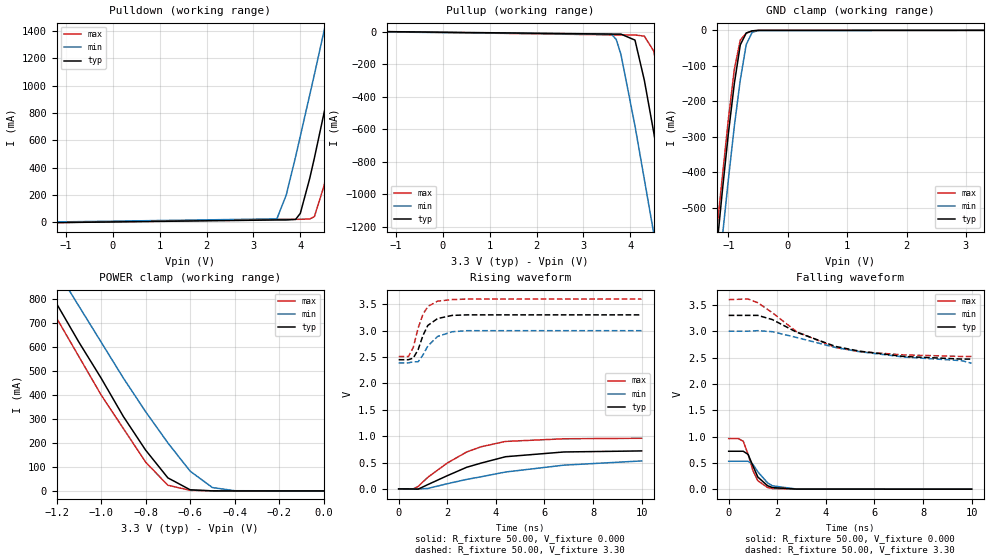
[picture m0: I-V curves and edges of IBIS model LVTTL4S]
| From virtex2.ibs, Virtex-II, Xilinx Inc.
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|   Model LVTTL4S
[Model]   LVTTL4S
Model_type   I/O
Polarity   Non-Inverting
Enable   Active-Low
Vinh = 2.0V
Vinl = 0.8V
Vmeas =   1.40V
Cref =  0pF
Rref =   1.00M
Vref =  0.000V
C_comp   10.00pF   10.00pF   10.00pF
[Temperature Range]   25.00   100.00   0.000
[Voltage Range]   3.30V   3.00V   3.60V
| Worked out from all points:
|   slope of the pulldown table from 0 to 0.495 V, typ, clamps not added: 64.8 ohm
|   slope of the pullup table from 0 to 0.495 V, typ, clamps not added: 95.5 ohm
|   GND clamp passes 1 mA (typ) near -0.57 V on its own axis
|   POWER clamp passes 1 mA (typ) near -0.52 V on its own axis
|   rising waveform, R_fixture 50.00, V_fixture 0.000: 20-80 % time 2.59ns typ, 4.21ns min, 2.05ns max; typ from 0 V to 0.72 V
|   rising waveform, R_fixture 50.00, V_fixture 3.30: 20-80 % time 511ps typ, 613ps min, 470ps max; typ from 2.45 V to 3.3 V
|   falling waveform, R_fixture 50.00, V_fixture 0.000: 20-80 % time 515ps typ, 584ps min, 453ps max; typ from 0.72 V to 0 V
|   falling waveform, R_fixture 50.00, V_fixture 3.30: 20-80 % time 3.06ns typ, 4.15ns min, 2.42ns max; typ from 3.3 V to 2.47 V
[Pulldown]
| voltage   I(typ)   I(min)   I(max)
-3.3V     -10.77mA   -7.22mA    -12.39mA
3.5V      17.22mA    24.99mA    22.01mA
3.7V      17.28mA    200mA      22.05mA
3.9V      21.2mA     480mA      22.09mA
4V        65.53mA    630mA      22.12mA
4.2V      320mA      930mA      24.26mA
4.3V      470mA      1.08A      41.45mA
4.5V      790mA      1.39A      260mA
4.9V      1.43A      2.01A      890mA
5.1V      1.76A      2.33A      1.21A
5.3V      2.09A      2.64A      1.54A
6.6V      4.26A      4.7A       3.7A
[Pullup]
| voltage   I(typ)   I(min)   I(max)
-3.3V     6.76mA     3.9mA      8.28mA
3.6V      -15.07mA   -16.2mA    -20.1mA
3.7V      -15.12mA   -48.43mA   -20.17mA
3.8V      -15.26mA   -140mA     -20.23mA
4.1V      -52.21mA   -580mA     -20.5mA
4.3V      -300mA     -910mA     -27.9mA
4.5V      -620mA     -1.24A     -120mA
4.7V      -960mA     -1.58A     -410mA
4.9V      -1.3A      -1.91A     -750mA
5.1V      -1.65A     -2.25A     -1.09A
5.3V      -2A        -2.6A      -1.43A
6.6V      -4.31A     -4.84A     -3.73A
[GND_clamp]
| voltage   I(typ)   I(min)   I(max)
-3.3V     -4.3A      -4.31A     -4.26A
-1.2V     -620mA     -740mA     -570mA
-1.1V     -450mA     -580mA     -410mA
-1V       -290mA     -420mA     -250mA
-900mV    -150mA     -270mA     -110mA
-800mV    -41.03mA   -140mA     -27.28mA
-700mV    -7.6mA     -40.21mA   -8.18mA
-600mV    -1.42mA    -5.61mA    -1.62mA
-500mV    -130uA     -670uA     -130uA
3.3V      67.85pA    43.48uA    45.6pA
[POWER_clamp]
| voltage   I(typ)   I(min)   I(max)
-3.3V     4.25A      4.22A      4.2A
-1.3V     940mA      1.07A      880mA
-1.2V     780mA      920mA      720mA
-1.1V     620mA      770mA      560mA
-1V       470mA      620mA      400mA
-900mV    310mA      470mA      260mA
-800mV    170mA      330mA      120mA
-700mV    54.34mA    200mA      23.62mA
-600mV    4.76mA     82.21mA    2.52mA
-500mV    280uA      14.02mA    260uA
-400mV    16.9uA     860uA      14.85uA
0V        67.85pA    2.04nA     61.89pA
[Ramp]
| variable   typ   min   max
dV/dt_r   0.43/2.60n   0.30/3.78n   0.58/2.00n
dV/dt_f   0.50/3.00n   0.34/3.61n   0.65/2.42n
R_load = 50.00
[Rising Waveform]
R_fixture = 50.00
V_fixture = 0.000
| time   V(typ)   V(min)   V(max)
0s        0V         0V         0V
600ps     -2.08mV    -200uV     -17.67uV
800ps     -5.41mV    -2.05mV    45.71mV
1.2ns     81.39mV    8.06mV     220mV
2ns       250mV      98.09mV    490mV
2.8ns     410mV      180mV      700mV
3.4ns     490mV      230mV      800mV
4.4ns     610mV      320mV      900mV
6.8ns     700mV      450mV      950mV
10ns      720mV      530mV      960mV
[Rising Waveform]
R_fixture = 50.00
V_fixture = 3.30
V_fixture_min = 3.00
V_fixture_max = 3.60
| time   V(typ)   V(min)   V(max)
0s        2.45V      2.39V      2.51V
400ps     2.45V      2.39V      2.51V
600ps     2.48V      2.41V      2.68V
800ps     2.64V      2.41V      3.05V
1ns       2.91V      2.54V      3.31V
1.2ns     3.1V       2.71V      3.46V
1.6ns     3.23V      2.89V      3.56V
2.2ns     3.29V      2.98V      3.59V
2.8ns     3.3V       3V         3.6V
10ns      3.3V       3V         3.6V
[Falling Waveform]
R_fixture = 50.00
V_fixture = 0.000
| time   V(typ)   V(min)   V(max)
0s        720mV      530mV      960mV
400ps     720mV      530mV      960mV
600ps     720mV      530mV      910mV
800ps     660mV      530mV      660mV
1ns       440mV      470mV      350mV
1.2ns     230mV      330mV      160mV
1.6ns     65.75mV    120mV      32.74mV
1.8ns     29.91mV    63.65mV    11.98mV
2.8ns     950uV      2.12mV     700uV
10ns      26.28uV    62.72uV    11.53uV
[Falling Waveform]
R_fixture = 50.00
V_fixture = 3.30
V_fixture_min = 3.00
V_fixture_max = 3.60
| time   V(typ)   V(min)   V(max)
0s        3.3V       3V         3.6V
800ps     3.3V       3V         3.61V
1.2ns     3.3V       3.01V      3.54V
1.8ns     3.22V      2.99V      3.35V
2.8ns     2.98V      2.88V      2.99V
4.4ns     2.71V      2.69V      2.69V
5.4ns     2.62V      2.61V      2.61V
7.2ns     2.52V      2.51V      2.55V
9.6ns     2.47V      2.44V      2.52V
10ns      2.47V      2.39V      2.52V
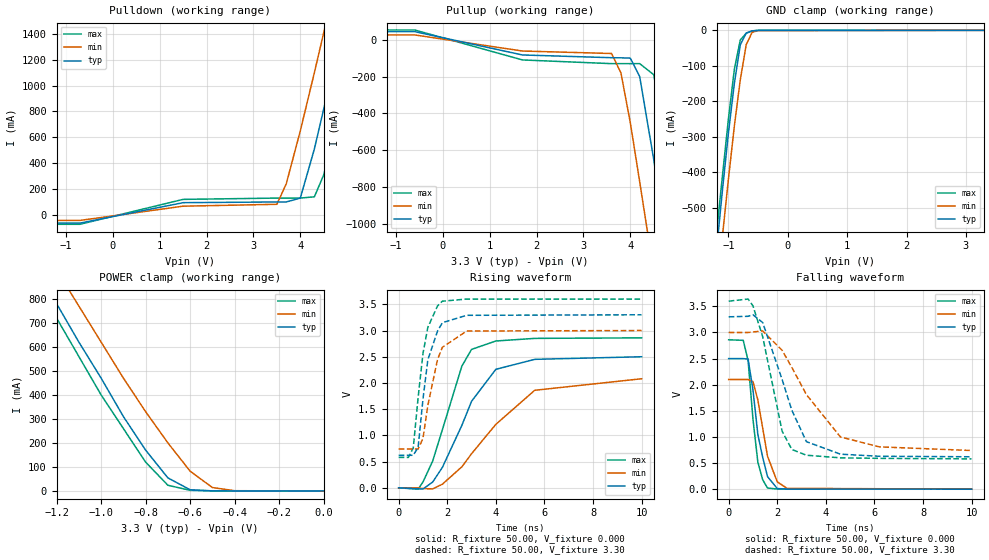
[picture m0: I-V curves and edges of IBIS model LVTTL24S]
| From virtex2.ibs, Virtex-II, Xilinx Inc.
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|   Model LVTTL24S
[Model]   LVTTL24S
Model_type   I/O
Polarity   Non-Inverting
Enable   Active-Low
Vinh = 2.0V
Vinl = 0.8V
Vmeas =   1.40V
Cref =  0pF
Rref =   1.00M
Vref =  0.000V
C_comp   10.00pF   10.00pF   10.00pF
[Temperature Range]   25.00   100.00   0.000
[Voltage Range]   3.30V   3.00V   3.60V
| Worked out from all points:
|   slope of the pulldown table from 0 to 0.495 V, typ, clamps not added: 11.1 ohm
|   slope of the pullup table from 0 to 0.495 V, typ, clamps not added: 15 ohm
|   GND clamp passes 1 mA (typ) near -0.57 V on its own axis
|   POWER clamp passes 1 mA (typ) near -0.52 V on its own axis
|   rising waveform, R_fixture 50.00, V_fixture 0.000: 20-80 % time 1.55ns typ, 2.36ns min, 1.13ns max; typ from 0 V to 2.5 V
|   rising waveform, R_fixture 50.00, V_fixture 3.30: 20-80 % time 535ps typ, 605ps min, 486ps max; typ from 0.62 V to 3.3 V
|   falling waveform, R_fixture 50.00, V_fixture 0.000: 20-80 % time 493ps typ, 524ps min, 357ps max; typ from 2.5 V to 0 V
|   falling waveform, R_fixture 50.00, V_fixture 3.30: 20-80 % time 1.08ns typ, 1.77ns min, 811ps max; typ from 3.3 V to 0.62 V
[Pulldown]
| voltage   I(typ)   I(min)   I(max)
-3.3V     -63.55mA   -42.85mA   -72.72mA
-700mV    -63.55mA   -42.85mA   -72.64mA
1.5V      94.54mA    67.4mA     120mA
3.5V      100mA      82mA       130mA
3.7V      100mA      240mA      130mA
4V        130mA      650mA      130mA
4.3V      510mA      1.1A       140mA
4.5V      820mA      1.41A      310mA
4.9V      1.47A      2.04A      930mA
5.1V      1.79A      2.35A      1.25A
5.3V      2.12A      2.67A      1.58A
6.6V      4.29A      4.73A      3.74A
[Pullup]
| voltage   I(typ)   I(min)   I(max)
-3.3V     43.55mA    25.59mA    52.52mA
-600mV    43.55mA    25.59mA    52.52mA
1.7V      -83mA      -61.63mA   -110mA
3.6V      -97.83mA   -75.1mA    -130mA
3.8V      -98.45mA   -180mA     -130mA
4V        -100mA     -450mA     -130mA
4.2V      -200mA     -770mA     -130mA
4.5V      -650mA     -1.26A     -190mA
4.9V      -1.33A     -1.93A     -780mA
5.1V      -1.68A     -2.27A     -1.12A
5.3V      -2.03A     -2.62A     -1.47A
6.6V      -4.33A     -4.85A     -3.76A
[GND_clamp]
| voltage   I(typ)   I(min)   I(max)
-3.3V     -4.3A      -4.31A     -4.26A
-1.2V     -620mA     -740mA     -570mA
-1.1V     -450mA     -580mA     -410mA
-1V       -290mA     -420mA     -250mA
-900mV    -150mA     -270mA     -110mA
-800mV    -41.03mA   -140mA     -27.28mA
-700mV    -7.6mA     -40.21mA   -8.18mA
-600mV    -1.42mA    -5.61mA    -1.62mA
-500mV    -130uA     -670uA     -130uA
3.3V      67.85pA    43.48uA    45.6pA
[POWER_clamp]
| voltage   I(typ)   I(min)   I(max)
-3.3V     4.25A      4.22A      4.2A
-1.3V     940mA      1.07A      880mA
-1.2V     780mA      920mA      720mA
-1.1V     620mA      770mA      560mA
-1V       470mA      620mA      400mA
-900mV    310mA      470mA      260mA
-800mV    170mA      330mA      120mA
-700mV    54.34mA    200mA      23.62mA
-600mV    4.76mA     82.21mA    2.52mA
-500mV    280uA      14.02mA    260uA
-400mV    16.9uA     860uA      14.85uA
0V        67.85pA    2.04nA     61.89pA
[Ramp]
| variable   typ   min   max
dV/dt_r   1.50/1.55n   1.25/2.35n   1.72/1.12n
dV/dt_f   1.61/1.13n   1.35/1.79n   1.81/0.80n
R_load = 50.00
[Rising Waveform]
R_fixture = 50.00
V_fixture = 0.000
| time   V(typ)   V(min)   V(max)
0s        0V         0V         0V
800ps     -19.43mV   -1.42mV    -26.19mV
1ns       -23.4mV    -14.97mV   110mV
1.4ns     110mV      -21.32mV   510mV
1.8ns     390mV      68.46mV    1.11V
2.6ns     1.19V      400mV      2.32V
3ns       1.65V      650mV      2.64V
4ns       2.26V      1.21V      2.8V
5.6ns     2.45V      1.86V      2.85V
10ns      2.5V       2.08V      2.86V
[Rising Waveform]
R_fixture = 50.00
V_fixture = 3.30
V_fixture_min = 3.00
V_fixture_max = 3.60
| time   V(typ)   V(min)   V(max)
0s        620mV      740mV      580mV
400ps     620mV      740mV      580mV
600ps     620mV      740mV      760mV
800ps     770mV      740mV      1.72V
1ns       1.69V      940mV      2.56V
1.2ns     2.44V      1.57V      3.06V
1.6ns     2.99V      2.45V      3.47V
1.8ns     3.15V      2.68V      3.56V
2.8ns     3.29V      2.99V      3.6V
10ns      3.3V       3V         3.6V
[Falling Waveform]
R_fixture = 50.00
V_fixture = 0.000
| time   V(typ)   V(min)   V(max)
0s        2.5V       2.1V       2.86V
600ps     2.5V       2.1V       2.85V
800ps     2.49V      2.1V       2.46V
1ns       1.9V       2.06V      1.34V
1.2ns     1.05V      1.71V      520mV
1.4ns     610mV      1.17V      180mV
1.6ns     240mV      630mV      21.62mV
2ns       11.37mV    140mV      2.42mV
2.4ns     2.38mV     16.07mV    1.74mV
10ns      13.6uV     51.08uV    3.58uV
[Falling Waveform]
R_fixture = 50.00
V_fixture = 3.30
V_fixture_min = 3.00
V_fixture_max = 3.60
| time   V(typ)   V(min)   V(max)
0s        3.3V       3V         3.6V
800ps     3.31V      3V         3.64V
1ns       3.34V      3.01V      3.51V
1.4ns     3.19V      3.03V      2.92V
2.2ns     2.1V       2.66V      1.11V
2.6ns     1.51V      2.33V      760mV
3.2ns     910mV      1.81V      650mV
4.6ns     670mV      1V         600mV
6.2ns     630mV      810mV      590mV
10ns      620mV      740mV      580mV
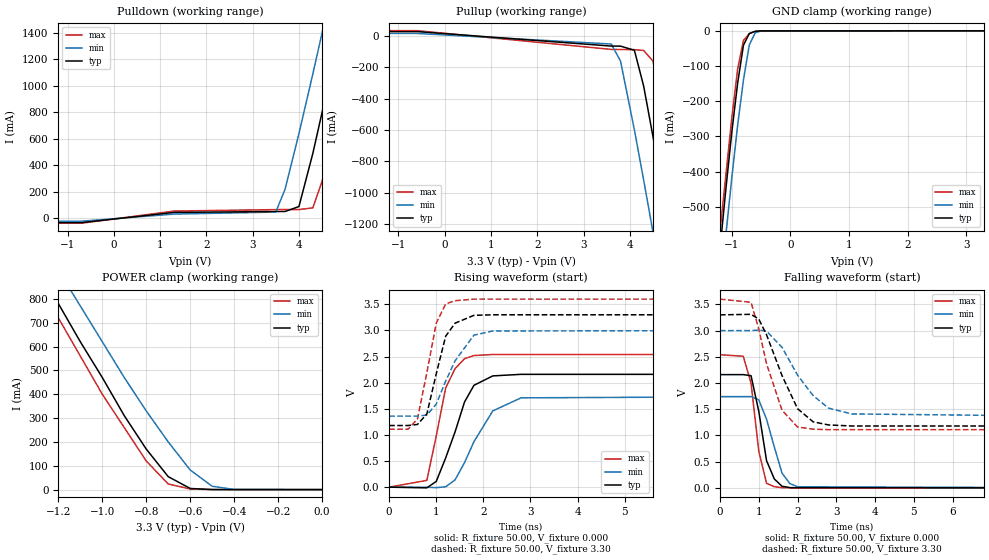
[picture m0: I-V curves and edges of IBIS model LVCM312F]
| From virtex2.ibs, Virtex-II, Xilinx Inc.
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|   Model LVCM312F
[Model]   LVCM312F
Model_type   I/O
Polarity   Non-Inverting
Enable   Active-Low
Vinh = 2.0V
Vinl = 0.8V
Vmeas =   1.65V
Cref =  0pF
Rref =   1.00M
Vref =  0.000V
C_comp   10.00pF   10.00pF   10.00pF
[Temperature Range]   25.00   100.00   0.000
[Voltage Range]   3.30V   3.00V   3.60V
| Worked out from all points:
|   slope of the pulldown table from 0 to 0.495 V, typ, clamps not added: 21.8 ohm
|   slope of the pullup table from 0 to 0.495 V, typ, clamps not added: 22.7 ohm
|   GND clamp passes 1 mA (typ) near -0.57 V on its own axis
|   POWER clamp passes 1 mA (typ) near -0.52 V on its own axis
|   rising waveform, R_fixture 50.00, V_fixture 0.000: 20-80 % time 518ps typ, 620ps min, 382ps max; typ from 0 V to 2.16 V
|   rising waveform, R_fixture 50.00, V_fixture 3.30: 20-80 % time 343ps typ, 504ps min, 323ps max; typ from 1.18 V to 3.3 V
|   falling waveform, R_fixture 50.00, V_fixture 0.000: 20-80 % time 329ps typ, 417ps min, 275ps max; typ from 2.16 V to 0 V
|   falling waveform, R_fixture 50.00, V_fixture 3.30: 20-80 % time 702ps typ, 905ps min, 570ps max; typ from 3.3 V to 1.18 V
[Pulldown]
| voltage   I(typ)   I(min)   I(max)
-3.3V     -32.1mA    -21.58mA   -36.83mA
-700mV    -32.1mA    -21.58mA   -36.83mA
1.3V      44.67mA    32.07mA    55.03mA
3.5V      51.66mA    47.4mA     66.01mA
3.7V      51.79mA    220mA      66.14mA
4V        89.06mA    640mA      66.32mA
4.3V      490mA      1.09A      79.21mA
4.5V      800mA      1.4A       280mA
4.9V      1.45A      2.02A      900mA
5.1V      1.78A      2.34A      1.23A
5.3V      2.11A      2.65A      1.56A
6.6V      4.27A      4.71A      3.72A
[Pullup]
| voltage   I(typ)   I(min)   I(max)
-3.3V     28.6mA     16.68mA    34.69mA
-600mV    28.6mA     16.68mA    34.69mA
3.6V      -63.99mA   -50.9mA    -85.36mA
3.8V      -64.43mA   -160mA     -85.91mA
4.1V      -90.87mA   -600mA     -86.68mA
4.3V      -320mA     -920mA     -92.25mA
4.5V      -640mA     -1.25A     -160mA
4.7V      -980mA     -1.59A     -440mA
4.9V      -1.32A     -1.93A     -770mA
5.1V      -1.67A     -2.27A     -1.11A
5.3V      -2.02A     -2.61A     -1.46A
6.6V      -4.32A     -4.85A     -3.75A
[GND_clamp]
| voltage   I(typ)   I(min)   I(max)
-3.3V     -4.3A      -4.31A     -4.26A
-1.2V     -620mA     -740mA     -570mA
-1.1V     -450mA     -580mA     -410mA
-1V       -290mA     -420mA     -250mA
-900mV    -150mA     -270mA     -110mA
-800mV    -41.03mA   -140mA     -27.28mA
-700mV    -7.6mA     -40.21mA   -8.18mA
-600mV    -1.42mA    -5.61mA    -1.62mA
-500mV    -130uA     -670uA     -130uA
3.3V      67.85pA    43.48uA    45.6pA
[POWER_clamp]
| voltage   I(typ)   I(min)   I(max)
-3.3V     4.25A      4.22A      4.2A
-1.3V     940mA      1.07A      880mA
-1.2V     780mA      920mA      720mA
-1.1V     620mA      770mA      560mA
-1V       470mA      620mA      400mA
-900mV    310mA      470mA      260mA
-800mV    170mA      330mA      120mA
-700mV    54.34mA    200mA      23.62mA
-600mV    4.76mA     82.21mA    2.52mA
-500mV    280uA      14.02mA    260uA
-400mV    16.9uA     860uA      14.85uA
0V        67.85pA    2.04nA     61.89pA
[Ramp]
| variable   typ   min   max
dV/dt_r   1.29/0.44n   1.04/0.60n   1.52/0.34n
dV/dt_f   1.27/0.65n   0.98/0.89n   1.50/0.50n
R_load = 50.00
[Rising Waveform]
R_fixture = 50.00
V_fixture = 0.000
| time   V(typ)   V(min)   V(max)
0s        0V         0V         0V
800ps     -13.48mV   -1.37mV    130mV
1ns       110mV      -9.52mV    980mV
1.2ns     560mV      6.51mV     1.9V
1.4ns     1.06V      140mV      2.27V
1.6ns     1.63V      470mV      2.46V
1.8ns     1.95V      870mV      2.52V
2.2ns     2.13V      1.46V      2.54V
2.8ns     2.16V      1.71V      2.54V
10ns      2.16V      1.74V      2.54V
[Rising Waveform]
R_fixture = 50.00
V_fixture = 3.30
V_fixture_min = 3.00
V_fixture_max = 3.60
| time   V(typ)   V(min)   V(max)
0s        1.18V      1.36V      1.11V
400ps     1.18V      1.36V      1.11V
600ps     1.2V       1.36V      1.3V
800ps     1.4V       1.38V      2.19V
1ns       2.17V      1.59V      3.14V
1.2ns     2.89V      2.03V      3.51V
1.4ns     3.14V      2.42V      3.57V
1.8ns     3.29V      2.91V      3.6V
2.2ns     3.3V       2.99V      3.6V
10ns      3.3V       3V         3.6V
[Falling Waveform]
R_fixture = 50.00
V_fixture = 0.000
| time   V(typ)   V(min)   V(max)
0s        2.16V      1.74V      2.54V
600ps     2.16V      1.74V      2.51V
800ps     2.14V      1.74V      2V
1ns       1.46V      1.68V      700mV
1.2ns     520mV      1.31V      87.3mV
1.4ns     170mV      780mV      22.72mV
1.6ns     30.16mV    280mV      3.53mV
1.8ns     5.55mV     81.67mV    1.05mV
2ns       1.52mV     21.29mV    590uV
10ns      -2.88uV    2.46uV     3.51uV
[Falling Waveform]
R_fixture = 50.00
V_fixture = 3.30
V_fixture_min = 3.00
V_fixture_max = 3.60
| time   V(typ)   V(min)   V(max)
0s        3.3V       3V         3.6V
800ps     3.31V      3V         3.54V
1ns       3.22V      3.01V      3.03V
1.2ns     2.92V      2.99V      2.37V
1.6ns     2.14V      2.68V      1.48V
2ns       1.51V      2.15V      1.16V
2.4ns     1.26V      1.76V      1.12V
2.8ns     1.2V       1.52V      1.11V
3.4ns     1.18V      1.41V      1.11V
10ns      1.18V      1.36V      1.11V
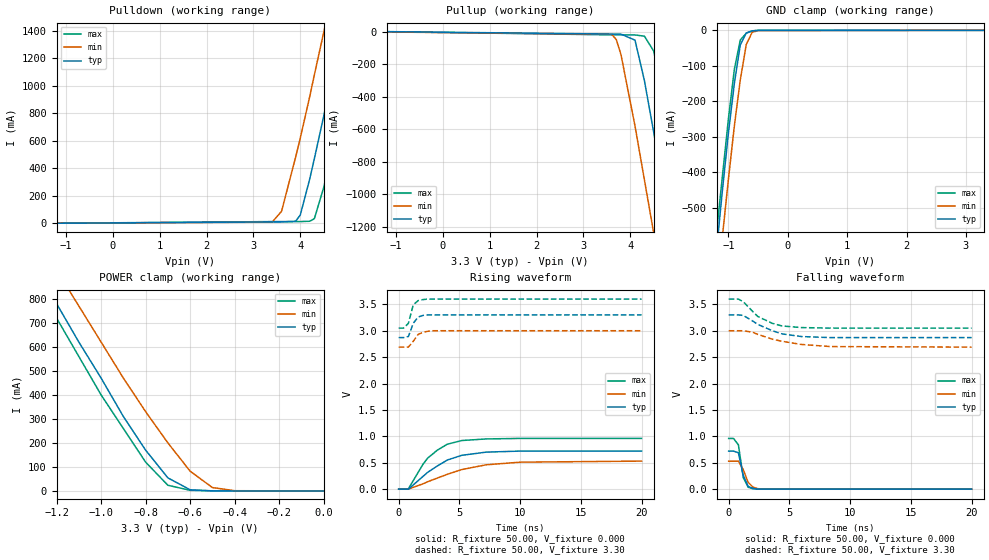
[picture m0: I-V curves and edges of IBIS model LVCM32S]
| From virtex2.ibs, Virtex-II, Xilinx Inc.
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|   Model LVCM32S
[Model]   LVCM32S
Model_type   I/O
Polarity   Non-Inverting
Enable   Active-Low
Vinh = 2.0V
Vinl = 0.8V
Vmeas =   1.65V
Cref =  0pF
Rref =   1.00M
Vref =  0.000V
C_comp   10.00pF   10.00pF   10.00pF
[Temperature Range]   25.00   100.00   0.000
[Voltage Range]   3.30V   3.00V   3.60V
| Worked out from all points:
|   slope of the pulldown table from 0 to 0.495 V, typ, clamps not added: 127 ohm
|   slope of the pullup table from 0 to 0.495 V, typ, clamps not added: 95.5 ohm
|   GND clamp passes 1 mA (typ) near -0.57 V on its own axis
|   POWER clamp passes 1 mA (typ) near -0.52 V on its own axis
|   rising waveform, R_fixture 50.00, V_fixture 0.000: 20-80 % time 2.73ns typ, 4.1ns min, 2.15ns max; typ from 0 V to 0.72 V
|   rising waveform, R_fixture 50.00, V_fixture 3.30: 20-80 % time 541ps typ, 655ps min, 377ps max; typ from 2.87 V to 3.3 V
|   falling waveform, R_fixture 50.00, V_fixture 0.000: 20-80 % time 518ps typ, 640ps min, 415ps max; typ from 0.72 V to 0 V
|   falling waveform, R_fixture 50.00, V_fixture 3.30: 20-80 % time 2.41ns typ, 3.2ns min, 1.96ns max; typ from 3.3 V to 2.87 V
[Pulldown]
| voltage   I(typ)   I(min)   I(max)
-3.3V     -5.48mA    -3.66mA    -6.34mA
3.4V      8.68mA     7.12mA     11.12mA
3.6V      8.7mA      86.09mA    11.15mA
3.9V      13.03mA    480mA      11.18mA
4V        59.94mA    620mA      11.2mA
4.2V      320mA      920mA      13.51mA
4.3V      470mA      1.08A      32.54mA
4.5V      780mA      1.39A      260mA
4.9V      1.43A      2.01A      880mA
5.1V      1.76A      2.32A      1.21A
5.3V      2.09A      2.64A      1.54A
6.6V      4.26A      4.7A       3.7A
[Pullup]
| voltage   I(typ)   I(min)   I(max)
-3.3V     6.76mA     3.9mA      8.28mA
3.6V      -15.07mA   -16.2mA    -20.1mA
3.7V      -15.12mA   -48.43mA   -20.17mA
3.8V      -15.26mA   -140mA     -20.23mA
4.1V      -52.21mA   -580mA     -20.5mA
4.3V      -300mA     -910mA     -27.9mA
4.5V      -620mA     -1.24A     -120mA
4.7V      -960mA     -1.58A     -410mA
4.9V      -1.3A      -1.91A     -750mA
5.1V      -1.65A     -2.25A     -1.09A
5.3V      -2A        -2.6A      -1.43A
6.6V      -4.31A     -4.84A     -3.73A
[GND_clamp]
| voltage   I(typ)   I(min)   I(max)
-3.3V     -4.3A      -4.31A     -4.26A
-1.2V     -620mA     -740mA     -570mA
-1.1V     -450mA     -580mA     -410mA
-1V       -290mA     -420mA     -250mA
-900mV    -150mA     -270mA     -110mA
-800mV    -41.03mA   -140mA     -27.28mA
-700mV    -7.6mA     -40.21mA   -8.18mA
-600mV    -1.42mA    -5.61mA    -1.62mA
-500mV    -130uA     -670uA     -130uA
3.3V      67.85pA    43.48uA    45.6pA
[POWER_clamp]
| voltage   I(typ)   I(min)   I(max)
-3.3V     4.25A      4.22A      4.2A
-1.3V     940mA      1.07A      880mA
-1.2V     780mA      920mA      720mA
-1.1V     620mA      770mA      560mA
-1V       470mA      620mA      400mA
-900mV    310mA      470mA      260mA
-800mV    170mA      330mA      120mA
-700mV    54.34mA    200mA      23.62mA
-600mV    4.76mA     82.21mA    2.52mA
-500mV    280uA      14.02mA    260uA
-400mV    16.9uA     860uA      14.85uA
0V        67.85pA    2.04nA     61.89pA
[Ramp]
| variable   typ   min   max
dV/dt_r   0.43/2.63n   0.32/4.05n   0.58/2.01n
dV/dt_f   0.26/2.31n   0.19/3.08n   0.33/1.84n
R_load = 50.00
[Rising Waveform]
R_fixture = 50.00
V_fixture = 0.000
| time   V(typ)   V(min)   V(max)
0s        0V         530nV      0V
800ps     -1.54mV    -150uV     5.14mV
2ns       240mV      99.95mV    470mV
2.4ns     320mV      140mV      590mV
3.2ns     440mV      210mV      740mV
4ns       550mV      280mV      850mV
5.2ns     640mV      370mV      920mV
7.2ns     700mV      460mV      950mV
10ns      720mV      510mV      960mV
20ns      720mV      530mV      960mV
[Rising Waveform]
R_fixture = 50.00
V_fixture = 3.30
V_fixture_min = 3.00
V_fixture_max = 3.60
| time   V(typ)   V(min)   V(max)
0s        2.87V      2.69V      3.05V
400ps     2.87V      2.69V      3.05V
800ps     2.89V      2.69V      3.14V
1.2ns     3.14V      2.8V       3.49V
1.6ns     3.26V      2.93V      3.57V
2ns       3.29V      2.97V      3.59V
2.4ns     3.3V       2.99V      3.6V
2.8ns     3.3V       3V         3.6V
20ns      3.3V       3V         3.6V
[Falling Waveform]
R_fixture = 50.00
V_fixture = 0.000
| time   V(typ)   V(min)   V(max)
0s        720mV      530mV      960mV
400ps     720mV      530mV      960mV
800ps     690mV      530mV      840mV
1.2ns     260mV      370mV      220mV
1.6ns     52.9mV     130mV      36.95mV
2ns       14.65mV    38.59mV    7.75mV
2.4ns     1.95mV     9.06mV     910uV
3.2ns     430uV      860uV      320uV
20ns      1.7uV      2.8uV      1.24uV
[Falling Waveform]
R_fixture = 50.00
V_fixture = 3.30
V_fixture_min = 3.00
V_fixture_max = 3.60
| time   V(typ)   V(min)   V(max)
0s        3.3V       3V         3.6V
800ps     3.3V       3V         3.6V
1.2ns     3.29V      3V         3.55V
2ns       3.18V      2.97V      3.36V
2.4ns     3.12V      2.93V      3.27V
3.6ns     3V         2.84V      3.14V
4.4ns     2.94V      2.8V       3.09V
6ns       2.89V      2.74V      3.06V
8.4ns     2.87V      2.7V       3.05V
20ns      2.87V      2.69V      3.05V
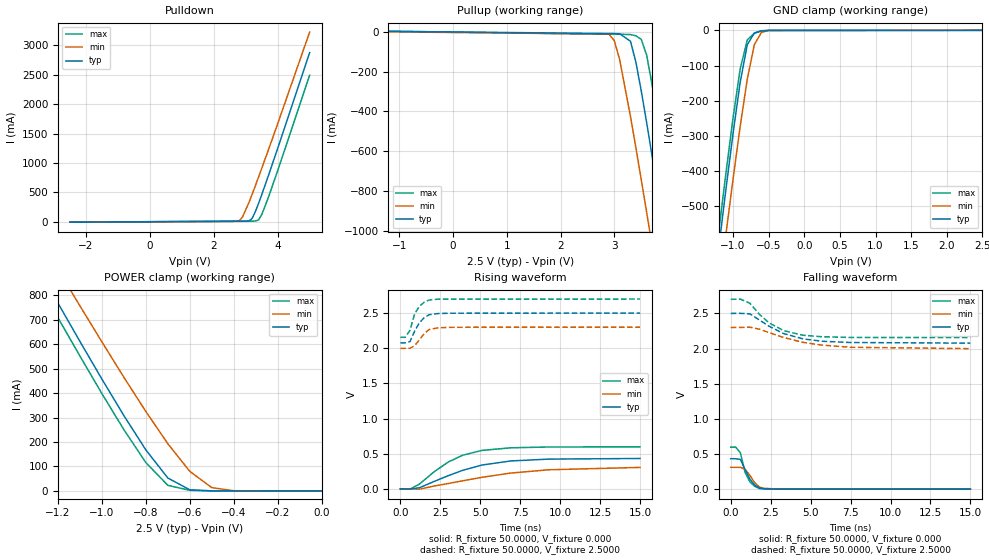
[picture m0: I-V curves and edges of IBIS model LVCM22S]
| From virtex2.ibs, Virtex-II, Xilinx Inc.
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|   Model LVCM22S
[Model]   LVCM22S
Model_type   I/O
Polarity   Non-Inverting
Enable   Active-Low
Vinh = 1.7V
Vinl = 0.7V
Vmeas =   1.2500V
Cref =  0pF
Rref =   1.0000M
Vref =  0.000V
C_comp   7.0000pF   6.0000pF   8.0000pF
[Temperature Range]   25.0000   100.0000   0.000
[Voltage Range]   2.5000V   2.3000V   2.7000V
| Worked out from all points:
|   slope of the pulldown table from 0 to 0.375 V, typ, clamps not added: 122 ohm
|   slope of the pullup table from 0 to 0.375 V, typ, clamps not added: 116 ohm
|   GND clamp passes 1 mA (typ) near -0.57 V on its own axis
|   POWER clamp passes 1 mA (typ) near -0.52 V on its own axis
|   rising waveform, R_fixture 50.0000, V_fixture 0.000: 20-80 % time 3.36ns typ, 5.09ns min, 2.41ns max; typ from 0 V to 0.433 V
|   rising waveform, R_fixture 50.0000, V_fixture 2.5000: 20-80 % time 677ps typ, 679ps min, 562ps max; typ from 2.08 V to 2.5 V
|   falling waveform, R_fixture 50.0000, V_fixture 0.000: 20-80 % time 635ps typ, 627ps min, 520ps max; typ from 0.433 V to 0 V
|   falling waveform, R_fixture 50.0000, V_fixture 2.5000: 20-80 % time 2.31ns typ, 3.08ns min, 1.78ns max; typ from 2.5 V to 2.08 V
[Pulldown]
| voltage   I(typ)   I(min)   I(max)
-2.5V     -5.481mA   -3.66mA    -6.342mA
2.6V      8.571mA    6.229mA    11mA
2.8V      8.604mA    18.89mA    11.04mA
2.9V      8.633mA    83.75mA    11.06mA
3.1V      12.78mA    327.5mA    11.1mA
3.2V      58.36mA    467.2mA    11.32mA
3.3V      171.9mA    611.7mA    13.35mA
3.4V      311.3mA    758.9mA    31.73mA
3.5V      460.3mA    908mA      121.4mA
3.7V      770.7mA    1.209A     402.1mA
4V        1.249A     1.668A     870.2mA
5V        2.877A     3.226A     2.492A
[Pullup]
| voltage   I(typ)   I(min)   I(max)
-2.5V     5.869mA    3.31mA     7.396mA
2.9V      -9.072mA   -11.85mA   -12.55mA
3V        -9.216mA   -45.04mA   -12.6mA
3.1V      -10.44mA   -141.9mA   -12.65mA
3.3V      -47.69mA   -425.5mA   -14.17mA
3.4V      -152.4mA   -582.2mA   -20.41mA
3.5V      -297mA     -743mA     -38.14mA
3.6V      -455.4mA   -906.4mA   -116.8mA
3.8V      -788.3mA   -1.238A    -410.7mA
4V        -1.13A     -1.574A    -743.1mA
4.2V      -1.477A    -1.913A    -1.085A
5V        -2.884A    -3.282A    -2.488A
[GND_clamp]
| voltage   I(typ)   I(min)   I(max)
-2.5V     -2.881A    -2.936A    -2.838A
-1.2V     -617mA     -740.6mA   -570.6mA
-1.1V     -452.1mA   -579.7mA   -406.1mA
-1V       -293.4mA   -423mA     -249mA
-900mV    -148mA     -273.4mA   -110.1mA
-800mV    -41mA      -138.5mA   -27.22mA
-700mV    -7.569mA   -40.19mA   -8.128mA
-600mV    -1.403mA   -5.589mA   -1.597mA
-500mV    -127.6uA   -662.5uA   -122uA
2.5V      397.5nA    2.548uA    351.3nA
[POWER_clamp]
| voltage   I(typ)   I(min)   I(max)
-2.5V     2.874A     2.908A     2.816A
-1.3V     925.8mA    1.055A     866.1mA
-1.2V     767.5mA    905.5mA    707.7mA
-1.1V     610.9mA    756.3mA    551.2mA
-1V       456.9mA    609.1mA    397.6mA
-900mV    307.7mA    464.5mA    250.2mA
-800mV    167.5mA    324.6mA    115.6mA
-700mV    52.75mA    192.9mA    22.81mA
-600mV    4.571mA    79.88mA    2.444mA
-500mV    271.3uA    13.45mA    251.8uA
-400mV    16.93uA    820.9uA    15.04uA
0V        397.5nA    368nA      428.7nA
[Ramp]
| variable   typ   min   max
dV/dt_r   0.2596/3.3458n   0.1834/5.0770n   0.3590/2.4854n
dV/dt_f   0.2538/2.2975n   0.1806/3.0775n   0.3264/1.8377n
R_load = 50.0000
[Rising Waveform]
R_fixture = 50.0000
V_fixture = 0.000
| time   V(typ)   V(min)   V(max)
0s        18.75uV    19.27uV    19.23uV
600ps     -1.302mV   -45.93uV   -3.675mV
1.2ns     17.12mV    -3.616mV   69.91mV
2.1ns     104.8mV    40.25mV    242.1mV
3ns       188.7mV    76.93mV    382.6mV
3.9ns     264.3mV    115.4mV    479.2mV
5.1ns     339.4mV    165.1mV    547.2mV
6.9ns     397.4mV    225.1mV    584.7mV
9.3ns     423.9mV    272.3mV    596.1mV
15ns      432.7mV    305.7mV    598.3mV
[Rising Waveform]
R_fixture = 50.0000
V_fixture = 2.5000
V_fixture_min = 2.3000
V_fixture_max = 2.7000
| time   V(typ)   V(min)   V(max)
0s        2.077V     1.999V     2.156V
300ps     2.077V     1.999V     2.156V
600ps     2.095V     2V         2.255V
900ps     2.248V     2.038V     2.495V
1.2ns     2.366V     2.123V     2.6V
1.5ns     2.437V     2.212V     2.657V
1.8ns     2.478V     2.267V     2.687V
2.4ns     2.495V     2.292V     2.699V
3.3ns     2.499V     2.299V     2.699V
15ns      2.5V       2.3V       2.7V
[Falling Waveform]
R_fixture = 50.0000
V_fixture = 0.000
| time   V(typ)   V(min)   V(max)
0s        433.1mV    310.8mV    598.3mV
300ps     433mV      310.8mV    598.5mV
600ps     423.9mV    311.1mV    519.4mV
900ps     277.3mV    280.9mV    236.6mV
1.2ns     140.3mV    195.3mV    103.2mV
1.5ns     57.22mV    90.85mV    40.1mV
1.8ns     14.84mV    29.46mV    8.6mV
2.1ns     5.989mV    12mV       3.188mV
3ns       432.7uV    1.022mV    409.4uV
15ns      1.629uV    42.31uV    57.82uV
[Falling Waveform]
R_fixture = 50.0000
V_fixture = 2.5000
V_fixture_min = 2.3000
V_fixture_max = 2.7000
| time   V(typ)   V(min)   V(max)
0s        2.5V       2.3V       2.7V
600ps     2.501V     2.3V       2.704V
1.2ns     2.493V     2.304V     2.644V
1.8ns     2.405V     2.275V     2.485V
2.4ns     2.317V     2.227V     2.365V
3.3ns     2.214V     2.158V     2.256V
4.5ns     2.139V     2.089V     2.19V
5.7ns     2.104V     2.049V     2.168V
7.5ns     2.086V     2.018V     2.158V
15ns      2.077V     1.999V     2.156V
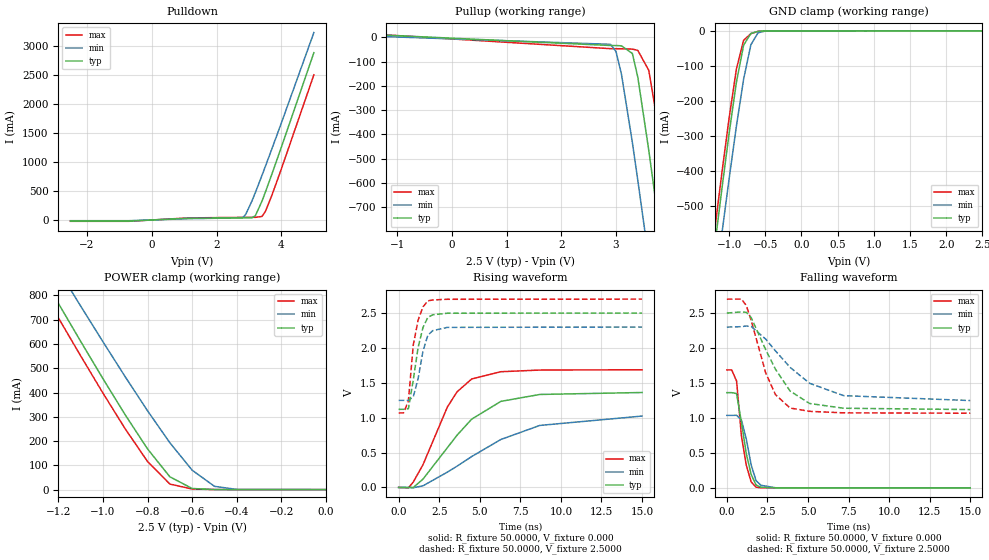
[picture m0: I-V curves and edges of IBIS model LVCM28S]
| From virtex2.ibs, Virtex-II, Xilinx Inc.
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|   Model LVCM28S
[Model]   LVCM28S
Model_type   I/O
Polarity   Non-Inverting
Enable   Active-Low
Vinh = 1.7V
Vinl = 0.7V
Vmeas =   1.2500V
Cref =  0pF
Rref =   1.0000M
Vref =  0.000V
C_comp   7.0000pF   6.0000pF   8.0000pF
[Temperature Range]   25.0000   100.0000   0.000
[Voltage Range]   2.5000V   2.3000V   2.7000V
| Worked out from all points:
|   slope of the pulldown table from 0 to 0.375 V, typ, clamps not added: 31.4 ohm
|   slope of the pullup table from 0 to 0.375 V, typ, clamps not added: 31.2 ohm
|   GND clamp passes 1 mA (typ) near -0.57 V on its own axis
|   POWER clamp passes 1 mA (typ) near -0.52 V on its own axis
|   rising waveform, R_fixture 50.0000, V_fixture 0.000: 20-80 % time 3.06ns typ, 4.76ns min, 2.02ns max; typ from 0 V to 1.36 V
|   rising waveform, R_fixture 50.0000, V_fixture 2.5000: 20-80 % time 632ps typ, 594ps min, 521ps max; typ from 1.12 V to 2.5 V
|   falling waveform, R_fixture 50.0000, V_fixture 0.000: 20-80 % time 629ps typ, 606ps min, 521ps max; typ from 1.36 V to 0 V
|   falling waveform, R_fixture 50.0000, V_fixture 2.5000: 20-80 % time 1.95ns typ, 2.84ns min, 1.36ns max; typ from 2.5 V to 1.12 V
[Pulldown]
| voltage   I(typ)   I(min)   I(max)
-2.5V     -21.46mA   -14.42mA   -24.66mA
-700mV    -21.46mA   -14.42mA   -24.66mA
1.1V      27.29mA    19.74mA    33.24mA
2.8V      34.1mA     35.31mA    43.63mA
2.9V      34.17mA    95.43mA    43.7mA
3.1V      37.35mA    336mA      43.82mA
3.2V      75.55mA    475.3mA    44.03mA
3.4V      322.2mA    766.6mA    59.14mA
3.5V      470.5mA    915.6mA    138.9mA
3.7V      780.3mA    1.217A     415.2mA
4V        1.258A     1.675A     882.3mA
5V        2.886A     3.233A     2.504A
[Pullup]
| voltage   I(typ)   I(min)   I(max)
-2.5V     21.93mA    12.45mA    27.44mA
2.9V      -33.99mA   -29.15mA   -47.02mA
3V        -34.2mA    -58.65mA   -47.21mA
3.1V      -35.29mA   -151.4mA   -47.4mA
3.3V      -66.71mA   -432.6mA   -48.79mA
3.4V      -164.6mA   -588.9mA   -54.27mA
3.6V      -464.4mA   -912.8mA   -136.1mA
3.7V      -628.6mA   -1.078A    -268.6mA
3.8V      -796.6mA   -1.244A    -423.5mA
4V        -1.138A    -1.58A     -754.7mA
4.2V      -1.485A    -1.919A    -1.096A
5V        -2.892A    -3.288A    -2.498A
[GND_clamp]
| voltage   I(typ)   I(min)   I(max)
-2.5V     -2.881A    -2.936A    -2.838A
-1.2V     -617mA     -740.6mA   -570.6mA
-1.1V     -452.1mA   -579.7mA   -406.1mA
-1V       -293.4mA   -423mA     -249mA
-900mV    -148mA     -273.4mA   -110.1mA
-800mV    -41mA      -138.5mA   -27.22mA
-700mV    -7.569mA   -40.19mA   -8.128mA
-600mV    -1.403mA   -5.589mA   -1.597mA
-500mV    -127.6uA   -662.5uA   -122uA
2.5V      397.5nA    2.548uA    351.3nA
[POWER_clamp]
| voltage   I(typ)   I(min)   I(max)
-2.5V     2.874A     2.908A     2.816A
-1.3V     925.8mA    1.055A     866.1mA
-1.2V     767.5mA    905.5mA    707.7mA
-1.1V     610.9mA    756.3mA    551.2mA
-1V       456.9mA    609.1mA    397.6mA
-900mV    307.7mA    464.5mA    250.2mA
-800mV    167.5mA    324.6mA    115.6mA
-700mV    52.75mA    192.9mA    22.81mA
-600mV    4.571mA    79.88mA    2.444mA
-500mV    271.3uA    13.45mA    251.8uA
-400mV    16.93uA    820.9uA    15.04uA
0V        397.5nA    368nA      428.7nA
[Ramp]
| variable   typ   min   max
dV/dt_r   0.8166/3.0503n   0.6138/4.7554n   1.0122/2.0714n
dV/dt_f   0.8280/1.9480n   0.6306/2.8423n   0.9792/1.4204n
R_load = 50.0000
[Rising Waveform]
R_fixture = 50.0000
V_fixture = 0.000
| time   V(typ)   V(min)   V(max)
0s        9.398uV    10.7uV     9.176uV
600ps     -2.015mV   79.52uV    -6.366mV
900ps     -1.339mV   -4.328mV   76.62mV
1.5ns     119.5mV    23.16mV    326.3mV
3ns       568.7mV    219mV      1.152V
3.6ns     749.2mV    304.8mV    1.371V
4.5ns     978.9mV    442.7mV    1.555V
6.3ns     1.234V     687.5mV    1.659V
8.7ns     1.333V     888.9mV    1.683V
15ns      1.361V     1.023V     1.687V
[Rising Waveform]
R_fixture = 50.0000
V_fixture = 2.5000
V_fixture_min = 2.3000
V_fixture_max = 2.7000
| time   V(typ)   V(min)   V(max)
0s        1.12V      1.248V     1.068V
300ps     1.12V      1.248V     1.068V
600ps     1.129V     1.248V     1.242V
900ps     1.54V      1.299V     2.041V
1.2ns     2.01V      1.561V     2.4V
1.5ns     2.294V     1.955V     2.589V
1.8ns     2.439V     2.183V     2.675V
2.1ns     2.475V     2.248V     2.688V
3ns       2.498V     2.295V     2.698V
15ns      2.5V       2.3V       2.7V
[Falling Waveform]
R_fixture = 50.0000
V_fixture = 0.000
| time   V(typ)   V(min)   V(max)
0s        1.362V     1.037V     1.687V
300ps     1.362V     1.037V     1.687V
600ps     1.349V     1.038V     1.529V
900ps     938mV      970.6mV    743.5mV
1.2ns     489.7mV    698.6mV    322.6mV
1.5ns     191.7mV    328.7mV    85.59mV
1.8ns     41.81mV    103.6mV    9.649mV
2.1ns     8.224mV    36.85mV    1.891mV
3ns       1.041mV    1.594mV    1.278mV
15ns      39.19uV    27.65uV    23.52uV
[Falling Waveform]
R_fixture = 50.0000
V_fixture = 2.5000
V_fixture_min = 2.3000
V_fixture_max = 2.7000
| time   V(typ)   V(min)   V(max)
0s        2.5V       2.3V       2.7V
900ps     2.518V     2.306V     2.7V
1.2ns     2.511V     2.316V     2.609V
1.5ns     2.436V     2.309V     2.397V
2.4ns     1.974V     2.127V     1.641V
3ns       1.696V     1.959V     1.333V
3.9ns     1.385V     1.724V     1.142V
5.1ns     1.207V     1.496V     1.095V
7.2ns     1.139V     1.319V     1.073V
15ns      1.12V      1.249V     1.068V
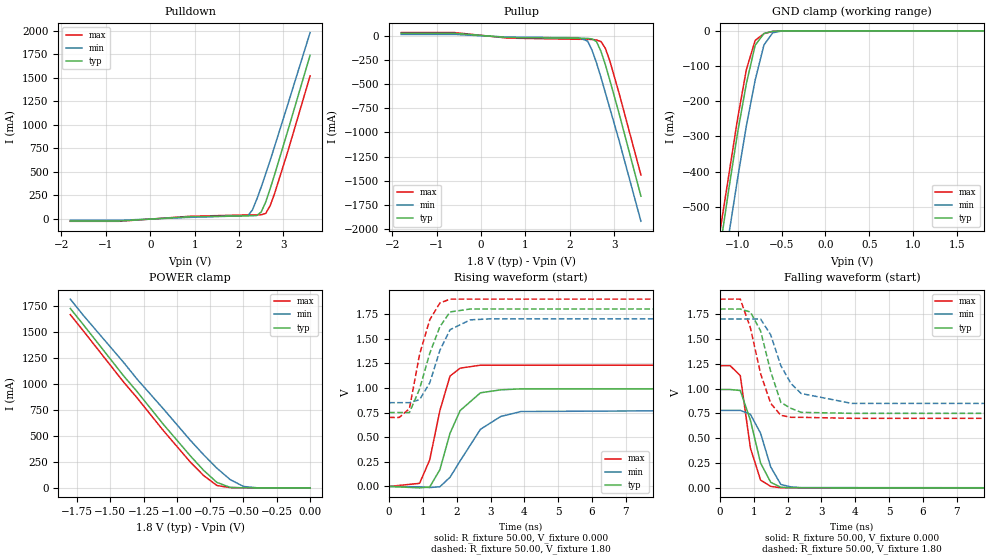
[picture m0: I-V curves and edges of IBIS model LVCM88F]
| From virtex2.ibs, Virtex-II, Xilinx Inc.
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|   Model LVCM88F
[Model]   LVCM88F
Model_type   I/O
Polarity   Non-Inverting
Enable   Active-Low
Vinh = 1.19V
Vinl = 0.4V
Vmeas =   0.90V
Cref =  0pF
Rref =   1.00M
Vref =  0.000V
C_comp   10.00pF   10.00pF   10.00pF
[Temperature Range]   25.00   100.00   0.000
[Voltage Range]   1.80V   1.70V   1.90V
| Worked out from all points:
|   slope of the pulldown table from 0 to 0.27 V, typ, clamps not added: 30.3 ohm
|   slope of the pullup table from 0 to 0.27 V, typ, clamps not added: 28.7 ohm
|   GND clamp passes 1 mA (typ) near -0.57 V on its own axis
|   POWER clamp passes 1 mA (typ) near -0.52 V on its own axis
|   rising waveform, R_fixture 50.00, V_fixture 0.000: 20-80 % time 632ps typ, 952ps min, 514ps max; typ from 0 V to 0.99 V
|   rising waveform, R_fixture 50.00, V_fixture 1.80: 20-80 % time 604ps typ, 567ps min, 492ps max; typ from 0.75 V to 1.8 V
|   falling waveform, R_fixture 50.00, V_fixture 0.000: 20-80 % time 492ps typ, 509ps min, 384ps max; typ from 0.99 V to 0 V
|   falling waveform, R_fixture 50.00, V_fixture 1.80: 20-80 % time 519ps typ, 680ps min, 562ps max; typ from 1.8 V to 0.75 V
[Pulldown]
| voltage   I(typ)   I(min)   I(max)
-1.8V     -21.46mA   -14.43mA   -24.67mA
-700mV    -21.46mA   -14.43mA   -24.67mA
900mV     24.04mA    17.53mA    28.95mA
2.2V      33.62mA    34.8mA     43.05mA
2.3V      33.91mA    95.09mA    43.19mA
2.4V      36.92mA    210mA      43.46mA
2.5V      75.26mA    340mA      45.12mA
2.6V      180mA      480mA      58.72mA
2.7V      320mA      620mA      140mA
2.8V      470mA      770mA      270mA
3.1V      940mA      1.22A      720mA
3.6V      1.74A      1.98A      1.52A
[Pullup]
| voltage   I(typ)   I(min)   I(max)
-1.8V     26.84mA    15.08mA    34.32mA
-600mV    26.84mA    15.08mA    34.32mA
600mV     -17.12mA   -12.88mA   -23.16mA
2.2V      -24.66mA   -18.96mA   -35.1mA
2.4V      -26.04mA   -54.01mA   -35.57mA
2.5V      -31.53mA   -150mA     -36.83mA
2.6V      -59.55mA   -280mA     -42.59mA
2.7V      -160mA     -430mA     -58.29mA
2.8V      -300mA     -590mA     -130mA
2.9V      -460mA     -750mA     -260mA
3.1V      -790mA     -1.07A     -580mA
3.6V      -1.66A     -1.92A     -1.44A
[GND_clamp]
| voltage   I(typ)   I(min)   I(max)
-1.8V     -1.65A     -1.74A     -1.6A
-1.2V     -620mA     -740mA     -570mA
-1.1V     -450mA     -580mA     -410mA
-1V       -290mA     -420mA     -250mA
-900mV    -150mA     -270mA     -110mA
-800mV    -40.97mA   -140mA     -27.17mA
-700mV    -7.54mA    -40.17mA   -8.08mA
-600mV    -1.39mA    -5.57mA    -1.57mA
-500mV    -120uA     -660uA     -120uA
1.8V      34.27pA    98.88nA    22.46pA
[POWER_clamp]
| voltage   I(typ)   I(min)   I(max)
-1.8V     1.73A      1.82A      1.67A
-1.7V     1.57A      1.66A      1.51A
-1.4V     1.08A      1.21A      1.02A
-1.3V     930mA      1.05A      870mA
-1.1V     610mA      760mA      550mA
-900mV    310mA      460mA      250mA
-800mV    170mA      320mA      120mA
-700mV    52.75mA    190mA      22.81mA
-600mV    4.57mA     79.88mA    2.44mA
-500mV    270uA      13.45mA    250uA
-400mV    16.38uA    820uA      14.46uA
0V        34.27pA    1.07nA     29.84pA
[Ramp]
| variable   typ   min   max
dV/dt_r   0.60/0.68n   0.47/0.90n   0.74/0.50n
dV/dt_f   0.63/0.52n   0.51/0.73n   0.72/0.41n
R_load = 50.00
[Rising Waveform]
R_fixture = 50.00
V_fixture = 0.000
| time   V(typ)   V(min)   V(max)
0s        0V         0V         0V
900ps     -14.11mV   -3.39mV    31.8mV
1.2ns     -4.99mV    -11.3mV    270mV
1.5ns     170mV      -2.72mV    770mV
1.8ns     540mV      93.12mV    1.12V
2.1ns     770mV      260mV      1.2V
2.7ns     950mV      580mV      1.23V
3.3ns     980mV      710mV      1.23V
3.9ns     990mV      760mV      1.23V
15ns      990mV      780mV      1.23V
[Rising Waveform]
R_fixture = 50.00
V_fixture = 1.80
V_fixture_min = 1.70
V_fixture_max = 1.90
| time   V(typ)   V(min)   V(max)
0s        750mV      850mV      700mV
300ps     750mV      850mV      700mV
600ps     750mV      850mV      790mV
900ps     990mV      880mV      1.34V
1.2ns     1.35V      1.05V      1.69V
1.5ns     1.62V      1.38V      1.86V
1.8ns     1.77V      1.59V      1.9V
2.4ns     1.8V       1.69V      1.9V
3ns       1.8V       1.7V       1.9V
15ns      1.8V       1.7V       1.9V
[Falling Waveform]
R_fixture = 50.00
V_fixture = 0.000
| time   V(typ)   V(min)   V(max)
0s        990mV      780mV      1.23V
300ps     990mV      780mV      1.23V
600ps     980mV      780mV      1.13V
900ps     680mV      740mV      400mV
1.2ns     250mV      550mV      78.25mV
1.5ns     55.76mV    210mV      14.41mV
1.8ns     5.78mV     34.31mV    1.55mV
2.1ns     1.39mV     9.34mV     68.3uV
2.4ns     620uV      2.36mV     -130uV
15ns      9.14uV     13.39uV    22.49uV
[Falling Waveform]
R_fixture = 50.00
V_fixture = 1.80
V_fixture_min = 1.70
V_fixture_max = 1.90
| time   V(typ)   V(min)   V(max)
0s        1.8V       1.7V       1.9V
600ps     1.8V       1.7V       1.9V
900ps     1.77V      1.7V       1.61V
1.2ns     1.58V      1.7V       1.15V
1.5ns     1.17V      1.54V      850mV
1.8ns     860mV      1.23V      730mV
2.1ns     800mV      1.05V      710mV
2.4ns     760mV      950mV      710mV
3.9ns     750mV      850mV      700mV
15ns      750mV      850mV      700mV
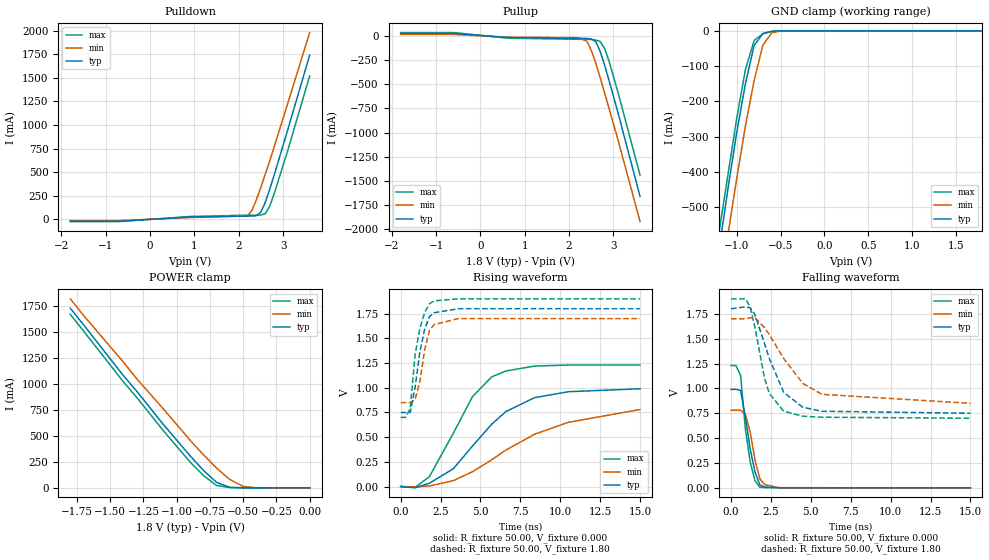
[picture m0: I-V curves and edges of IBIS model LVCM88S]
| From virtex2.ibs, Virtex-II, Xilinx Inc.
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|   Model LVCM88S
[Model]   LVCM88S
Model_type   I/O
Polarity   Non-Inverting
Enable   Active-Low
Vinh = 1.19V
Vinl = 0.4V
Vmeas =   0.90V
Cref =  0pF
Rref =   1.00M
Vref =  0.000V
C_comp   10.00pF   10.00pF   10.00pF
[Temperature Range]   25.00   100.00   0.000
[Voltage Range]   1.80V   1.70V   1.90V
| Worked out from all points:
|   slope of the pulldown table from 0 to 0.27 V, typ, clamps not added: 30.3 ohm
|   slope of the pullup table from 0 to 0.27 V, typ, clamps not added: 28.7 ohm
|   GND clamp passes 1 mA (typ) near -0.57 V on its own axis
|   POWER clamp passes 1 mA (typ) near -0.52 V on its own axis
|   rising waveform, R_fixture 50.00, V_fixture 0.000: 20-80 % time 3.53ns typ, 5.46ns min, 2.4ns max; typ from 0 V to 0.99 V
|   rising waveform, R_fixture 50.00, V_fixture 1.80: 20-80 % time 648ps typ, 592ps min, 629ps max; typ from 0.75 V to 1.8 V
|   falling waveform, R_fixture 50.00, V_fixture 0.000: 20-80 % time 642ps typ, 605ps min, 541ps max; typ from 0.99 V to 0 V
|   falling waveform, R_fixture 50.00, V_fixture 1.80: 20-80 % time 1.5ns typ, 2.36ns min, 1ns max; typ from 1.8 V to 0.75 V
[Pulldown]
| voltage   I(typ)   I(min)   I(max)
-1.8V     -21.46mA   -14.43mA   -24.67mA
-700mV    -21.46mA   -14.43mA   -24.67mA
900mV     24.04mA    17.53mA    28.95mA
2.2V      33.62mA    34.8mA     43.05mA
2.3V      33.91mA    95.09mA    43.19mA
2.4V      36.92mA    210mA      43.46mA
2.5V      75.26mA    340mA      45.12mA
2.6V      180mA      480mA      58.72mA
2.7V      320mA      620mA      140mA
2.8V      470mA      770mA      270mA
3.1V      940mA      1.22A      720mA
3.6V      1.74A      1.98A      1.52A
[Pullup]
| voltage   I(typ)   I(min)   I(max)
-1.8V     26.84mA    15.08mA    34.32mA
-600mV    26.84mA    15.08mA    34.32mA
600mV     -17.12mA   -12.88mA   -23.16mA
2.2V      -24.66mA   -18.96mA   -35.1mA
2.4V      -26.04mA   -54.01mA   -35.57mA
2.5V      -31.53mA   -150mA     -36.83mA
2.6V      -59.55mA   -280mA     -42.59mA
2.7V      -160mA     -430mA     -58.29mA
2.8V      -300mA     -590mA     -130mA
2.9V      -460mA     -750mA     -260mA
3.1V      -790mA     -1.07A     -580mA
3.6V      -1.66A     -1.92A     -1.44A
[GND_clamp]
| voltage   I(typ)   I(min)   I(max)
-1.8V     -1.65A     -1.74A     -1.6A
-1.2V     -620mA     -740mA     -570mA
-1.1V     -450mA     -580mA     -410mA
-1V       -290mA     -420mA     -250mA
-900mV    -150mA     -270mA     -110mA
-800mV    -40.97mA   -140mA     -27.17mA
-700mV    -7.54mA    -40.17mA   -8.08mA
-600mV    -1.39mA    -5.57mA    -1.57mA
-500mV    -120uA     -660uA     -120uA
1.8V      34.27pA    98.88nA    22.46pA
[POWER_clamp]
| voltage   I(typ)   I(min)   I(max)
-1.8V     1.73A      1.82A      1.67A
-1.7V     1.57A      1.66A      1.51A
-1.4V     1.08A      1.21A      1.02A
-1.3V     930mA      1.05A      870mA
-1.1V     610mA      760mA      550mA
-900mV    310mA      460mA      250mA
-800mV    170mA      320mA      120mA
-700mV    52.75mA    190mA      22.81mA
-600mV    4.57mA     79.88mA    2.44mA
-500mV    270uA      13.45mA    250uA
-400mV    16.38uA    820uA      14.46uA
0V        34.27pA    1.07nA     29.84pA
[Ramp]
| variable   typ   min   max
dV/dt_r   0.59/3.54n   0.45/4.89n   0.74/2.42n
dV/dt_f   0.63/1.50n   0.51/2.33n   0.72/1.05n
R_load = 50.00
[Rising Waveform]
R_fixture = 50.00
V_fixture = 0.000
| time   V(typ)   V(min)   V(max)
0s        0V         0V         0V
900ps     -13.24mV   -3.48mV    -8.33mV
1.8ns     33.79mV    5.98mV     100mV
3.3ns     180mV      59.36mV    540mV
4.5ns     410mV      150mV      910mV
5.7ns     630mV      270mV      1.11V
6.6ns     760mV      370mV      1.17V
8.4ns     900mV      530mV      1.22V
10.5ns    960mV      650mV      1.23V
15ns      990mV      780mV      1.23V
[Rising Waveform]
R_fixture = 50.00
V_fixture = 1.80
V_fixture_min = 1.70
V_fixture_max = 1.90
| time   V(typ)   V(min)   V(max)
0s        750mV      850mV      700mV
300ps     750mV      850mV      700mV
600ps     750mV      850mV      790mV
900ps     1V         880mV      1.33V
1.2ns     1.36V      1.06V      1.6V
1.5ns     1.59V      1.38V      1.76V
1.8ns     1.72V      1.58V      1.85V
2.1ns     1.76V      1.64V      1.88V
3.6ns     1.8V       1.7V       1.9V
15ns      1.8V       1.7V       1.9V
[Falling Waveform]
R_fixture = 50.00
V_fixture = 0.000
| time   V(typ)   V(min)   V(max)
0s        990mV      780mV      1.23V
300ps     990mV      780mV      1.23V
600ps     980mV      780mV      1.13V
900ps     710mV      740mV      590mV
1.2ns     390mV      560mV      260mV
1.5ns     160mV      280mV      70.79mV
1.8ns     31.93mV    92.62mV    7.26mV
2.1ns     7.92mV     33.8mV     2.66mV
3ns       470uV      1.29mV     940uV
15ns      -9.23uV    -2.65uV    39.44uV
[Falling Waveform]
R_fixture = 50.00
V_fixture = 1.80
V_fixture_min = 1.70
V_fixture_max = 1.90
| time   V(typ)   V(min)   V(max)
0s        1.8V       1.7V       1.9V
900ps     1.82V      1.7V       1.9V
1.2ns     1.81V      1.71V      1.82V
1.5ns     1.74V      1.71V      1.61V
2.1ns     1.45V      1.61V      1.1V
2.4ns     1.3V       1.54V      950mV
3.3ns     960mV      1.3V       770mV
4.5ns     810mV      1.05V      720mV
5.7ns     770mV      940mV      710mV
15ns      750mV      850mV      700mV
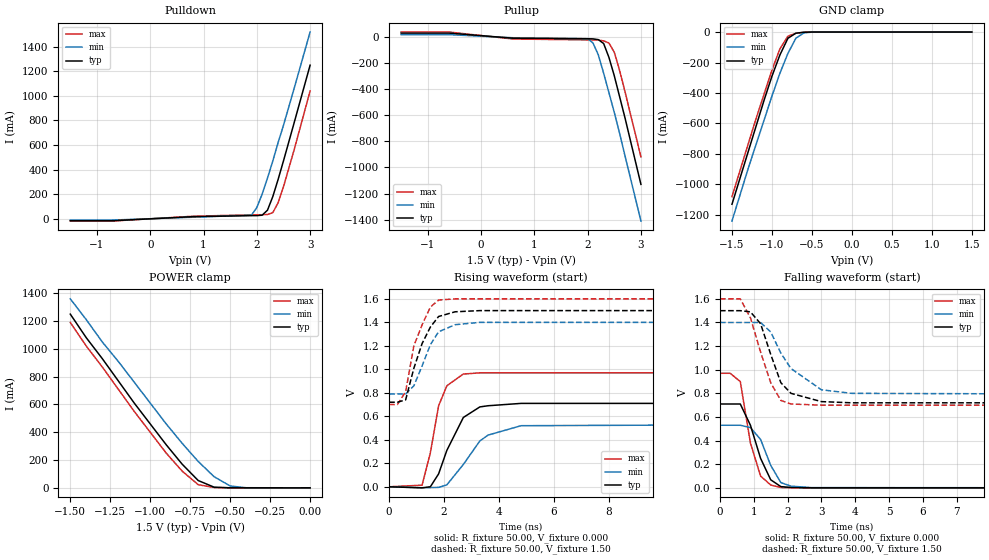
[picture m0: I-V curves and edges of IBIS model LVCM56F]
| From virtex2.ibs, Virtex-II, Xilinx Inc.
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|   Model LVCM56F
[Model]   LVCM56F
Model_type   I/O
Polarity   Non-Inverting
Enable   Active-Low
Vinh = 1.05V
Vinl = 0.3V
Vmeas =   0.75V
Cref =  0pF
Rref =   1.00M
Vref =  0.000V
C_comp   10.00pF   10.00pF   10.00pF
[Temperature Range]   25.00   100.00   0.000
[Voltage Range]   1.50V   1.40V   1.60V
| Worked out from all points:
|   slope of the pulldown table from 0 to 0.225 V, typ, clamps not added: 39.5 ohm
|   slope of the pullup table from 0 to 0.225 V, typ, clamps not added: 33.1 ohm
|   GND clamp passes 1 mA (typ) near -0.57 V on its own axis
|   POWER clamp passes 1 mA (typ) near -0.52 V on its own axis
|   rising waveform, R_fixture 50.00, V_fixture 0.000: 20-80 % time 792ps typ, 1.05ns min, 556ps max; typ from 0 V to 0.71 V
|   rising waveform, R_fixture 50.00, V_fixture 1.50: 20-80 % time 715ps typ, 694ps min, 626ps max; typ from 0.72 V to 1.5 V
|   falling waveform, R_fixture 50.00, V_fixture 0.000: 20-80 % time 542ps typ, 515ps min, 428ps max; typ from 0.71 V to 0 V
|   falling waveform, R_fixture 50.00, V_fixture 1.50: 20-80 % time 594ps typ, 878ps min, 599ps max; typ from 1.5 V to 0.72 V
[Pulldown]
| voltage   I(typ)   I(min)   I(max)
-1.5V     -16.22mA   -10.87mA   -18.68mA
-700mV    -16.22mA   -10.87mA   -18.68mA
800mV     16.72mA    12.21mA    20.07mA
1.9V      24.96mA    29.13mA    31.96mA
2V        25.29mA    91.07mA    32.16mA
2.1V      28.62mA    200mA      32.48mA
2.2V      69.4mA     330mA      34.31mA
2.3V      180mA      470mA      49.41mA
2.4V      320mA      620mA      130mA
2.5V      470mA      760mA      260mA
2.7V      780mA      1.06A      560mA
3V        1.25A      1.52A      1.04A
[Pullup]
| voltage   I(typ)   I(min)   I(max)
-1.5V     26.08mA    14.27mA    34.28mA
-600mV    26.08mA    14.27mA    34.28mA
600mV     -12.96mA   -9.43mA    -19.07mA
2V        -16.84mA   -17.11mA   -25.75mA
2.1V      -18.05mA   -49.15mA   -26mA
2.2V      -23.74mA   -140mA     -27.32mA
2.3V      -53.45mA   -280mA     -33.3mA
2.4V      -160mA     -430mA     -49.8mA
2.5V      -300mA     -580mA     -120mA
2.6V      -460mA     -740mA     -260mA
2.7V      -620mA     -910mA     -420mA
3V        -1.13A     -1.41A     -920mA
[GND_clamp]
| voltage   I(typ)   I(min)   I(max)
-1.5V     -1.13A     -1.24A     -1.08A
-1.3V     -790mA     -900mA     -740mA
-1.2V     -620mA     -740mA     -570mA
-1.1V     -450mA     -580mA     -410mA
-1V       -290mA     -420mA     -250mA
-900mV    -150mA     -270mA     -110mA
-800mV    -40.96mA   -140mA     -27.15mA
-700mV    -7.52mA    -40.16mA   -8.06mA
-600mV    -1.38mA    -5.56mA    -1.57mA
-500mV    -120uA     -650uA     -120uA
1.5V      27.96pA    98.69nA    16.96pA
[POWER_clamp]
| voltage   I(typ)   I(min)   I(max)
-1.5V     1.25A      1.36A      1.19A
-1.4V     1.08A      1.21A      1.02A
-1.3V     930mA      1.05A      870mA
-1.2V     770mA      910mA      710mA
-1.1V     610mA      760mA      550mA
-900mV    310mA      460mA      250mA
-800mV    170mA      320mA      120mA
-700mV    52.75mA    190mA      22.81mA
-600mV    4.57mA     79.88mA    2.44mA
-500mV    270uA      13.45mA    250uA
-400mV    16.38uA    820uA      14.46uA
0V        27.96pA    880pA      24.27pA
[Ramp]
| variable   typ   min   max
dV/dt_r   0.43/0.77n   0.32/1.01n   0.58/0.58n
dV/dt_f   0.47/0.64n   0.36/0.90n   0.54/0.51n
R_load = 50.00
[Rising Waveform]
R_fixture = 50.00
V_fixture = 0.000
| time   V(typ)   V(min)   V(max)
0s        0V         0V         0V
1.2ns     -9.08mV    -8.17mV    13.85mV
1.5ns     140uV      -6.76mV    290mV
1.8ns     110mV      -5.36mV    690mV
2.1ns     310mV      16.47mV    860mV
2.7ns     590mV      190mV      960mV
3.3ns     680mV      390mV      970mV
3.6ns     690mV      440mV      970mV
4.8ns     710mV      520mV      970mV
15ns      710mV      530mV      970mV
[Rising Waveform]
R_fixture = 50.00
V_fixture = 1.50
V_fixture_min = 1.40
V_fixture_max = 1.60
| time   V(typ)   V(min)   V(max)
0s        720mV      790mV      700mV
300ps     720mV      790mV      700mV
600ps     740mV      790mV      810mV
900ps     1.01V      860mV      1.2V
1.2ns     1.22V      1.03V      1.38V
1.5ns     1.36V      1.21V      1.53V
1.8ns     1.45V      1.32V      1.59V
2.4ns     1.49V      1.38V      1.6V
3.3ns     1.5V       1.4V       1.6V
15ns      1.5V       1.4V       1.6V
[Falling Waveform]
R_fixture = 50.00
V_fixture = 0.000
| time   V(typ)   V(min)   V(max)
0s        710mV      530mV      970mV
300ps     710mV      530mV      970mV
600ps     710mV      530mV      900mV
900ps     530mV      510mV      380mV
1.2ns     250mV      410mV      100mV
1.5ns     68.16mV    190mV      24.03mV
1.8ns     10.33mV    44.55mV    3.22mV
2.1ns     2.99mV     14.22mV    1.05mV
2.7ns     270uV      1.96mV     -30.55uV
15ns      11.51uV    8.69uV     22.94uV
[Falling Waveform]
R_fixture = 50.00
V_fixture = 1.50
V_fixture_min = 1.40
V_fixture_max = 1.60
| time   V(typ)   V(min)   V(max)
0s        1.5V       1.4V       1.6V
600ps     1.5V       1.4V       1.6V
900ps     1.49V      1.4V       1.44V
1.2ns     1.39V      1.4V       1.15V
1.5ns     1.13V      1.32V      890mV
1.8ns     890mV      1.14V      740mV
2.1ns     800mV      1.01V      710mV
3ns       730mV      830mV      700mV
3.9ns     720mV      800mV      700mV
15ns      720mV      790mV      700mV
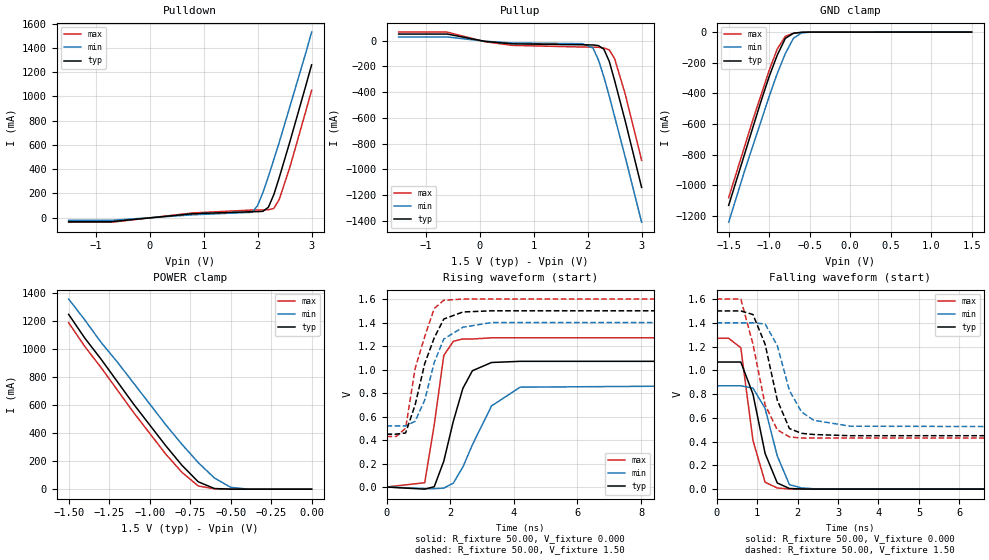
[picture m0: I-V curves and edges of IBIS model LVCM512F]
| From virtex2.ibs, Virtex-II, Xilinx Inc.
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|   Model LVCM512F
[Model]   LVCM512F
Model_type   I/O
Polarity   Non-Inverting
Enable   Active-Low
Vinh = 1.05V
Vinl = 0.3V
Vmeas =   0.75V
Cref =  0pF
Rref =   1.00M
Vref =  0.000V
C_comp   10.00pF   10.00pF   10.00pF
[Temperature Range]   25.00   100.00   0.000
[Voltage Range]   1.50V   1.40V   1.60V
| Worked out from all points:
|   slope of the pulldown table from 0 to 0.225 V, typ, clamps not added: 20.1 ohm
|   slope of the pullup table from 0 to 0.225 V, typ, clamps not added: 17 ohm
|   GND clamp passes 1 mA (typ) near -0.57 V on its own axis
|   POWER clamp passes 1 mA (typ) near -0.52 V on its own axis
|   rising waveform, R_fixture 50.00, V_fixture 0.000: 20-80 % time 640ps typ, 914ps min, 415ps max; typ from 0 V to 1.07 V
|   rising waveform, R_fixture 50.00, V_fixture 1.50: 20-80 % time 688ps typ, 619ps min, 611ps max; typ from 0.45 V to 1.5 V
|   falling waveform, R_fixture 50.00, V_fixture 0.000: 20-80 % time 466ps typ, 460ps min, 366ps max; typ from 1.07 V to 0 V
|   falling waveform, R_fixture 50.00, V_fixture 1.50: 20-80 % time 497ps typ, 547ps min, 481ps max; typ from 1.5 V to 0.45 V
[Pulldown]
| voltage   I(typ)   I(min)   I(max)
-1.5V     -32.11mA   -21.59mA   -36.84mA
-700mV    -32.11mA   -21.59mA   -36.84mA
800mV     33.08mA    24.24mA    39.59mA
1.9V      49.73mA    45.02mA    63.61mA
2V        50.15mA    100mA      64.01mA
2.1V      52.79mA    210mA      64.44mA
2.2V      86.76mA    340mA      66.01mA
2.3V      190mA      480mA      77.23mA
2.4V      330mA      620mA      150mA
2.6V      630mA      920mA      420mA
2.9V      1.1A       1.37A      890mA
3V        1.26A      1.53A      1.05A
[Pullup]
| voltage   I(typ)   I(min)   I(max)
-1.5V     50.74mA    28.13mA    65.93mA
-600mV    50.74mA    28.13mA    65.93mA
100mV     -6.48mA    -4.83mA    -8.79mA
600mV     -25.34mA   -18.46mA   -37.18mA
1.9V      -32.61mA   -24.05mA   -50.11mA
2.1V      -34.08mA   -57.96mA   -50.86mA
2.2V      -39.4mA    -150mA     -52.11mA
2.3V      -65.85mA   -280mA     -57.61mA
2.4V      -160mA     -430mA     -72.2mA
2.5V      -310mA     -590mA     -140mA
2.7V      -630mA     -910mA     -420mA
3V        -1.14A     -1.41A     -930mA
[GND_clamp]
| voltage   I(typ)   I(min)   I(max)
-1.5V     -1.13A     -1.24A     -1.08A
-1.3V     -790mA     -900mA     -740mA
-1.2V     -620mA     -740mA     -570mA
-1.1V     -450mA     -580mA     -410mA
-1V       -290mA     -420mA     -250mA
-900mV    -150mA     -270mA     -110mA
-800mV    -40.96mA   -140mA     -27.15mA
-700mV    -7.52mA    -40.16mA   -8.06mA
-600mV    -1.38mA    -5.56mA    -1.57mA
-500mV    -120uA     -650uA     -120uA
1.5V      27.96pA    98.69nA    16.96pA
[POWER_clamp]
| voltage   I(typ)   I(min)   I(max)
-1.5V     1.25A      1.36A      1.19A
-1.4V     1.08A      1.21A      1.02A
-1.3V     930mA      1.05A      870mA
-1.2V     770mA      910mA      710mA
-1.1V     610mA      760mA      550mA
-900mV    310mA      460mA      250mA
-800mV    170mA      320mA      120mA
-700mV    52.75mA    190mA      22.81mA
-600mV    4.57mA     79.88mA    2.44mA
-500mV    270uA      13.45mA    250uA
-400mV    16.38uA    820uA      14.46uA
0V        27.96pA    880pA      24.27pA
[Ramp]
| variable   typ   min   max
dV/dt_r   0.64/0.62n   0.52/0.91n   0.76/0.41n
dV/dt_f   0.63/0.42n   0.53/0.57n   0.70/0.33n
R_load = 50.00
[Rising Waveform]
R_fixture = 50.00
V_fixture = 0.000
| time   V(typ)   V(min)   V(max)
0s        0V         0V         0V
1.2ns     -18.33mV   -12.96mV   36.47mV
1.5ns     2.51mV     -14.02mV   530mV
1.8ns     220mV      -9.5mV     1.12V
2.1ns     560mV      33.17mV    1.24V
2.4ns     840mV      170mV      1.26V
2.7ns     990mV      360mV      1.26V
3.3ns     1.06V      690mV      1.27V
4.2ns     1.07V      850mV      1.27V
15ns      1.07V      870mV      1.27V
[Rising Waveform]
R_fixture = 50.00
V_fixture = 1.50
V_fixture_min = 1.40
V_fixture_max = 1.60
| time   V(typ)   V(min)   V(max)
0s        450mV      520mV      430mV
300ps     450mV      520mV      430mV
600ps     460mV      520mV      500mV
900ps     700mV      560mV      1.01V
1.2ns     1.05V      740mV      1.28V
1.5ns     1.27V      1.06V      1.52V
1.8ns     1.43V      1.26V      1.59V
2.4ns     1.49V      1.36V      1.6V
3.3ns     1.5V       1.4V       1.6V
15ns      1.5V       1.4V       1.6V
[Falling Waveform]
R_fixture = 50.00
V_fixture = 0.000
| time   V(typ)   V(min)   V(max)
0s        1.07V      870mV      1.27V
300ps     1.07V      870mV      1.27V
600ps     1.07V      870mV      1.19V
900ps     800mV      850mV      410mV
1.2ns     300mV      680mV      57.96mV
1.5ns     52.2mV     280mV      10.03mV
1.8ns     5.72mV     38.19mV    1.49mV
2.1ns     1.78mV     10.46mV    190uV
2.4ns     750uV      3.53mV     47.91uV
15ns      1.06uV     13.77uV    10uV
[Falling Waveform]
R_fixture = 50.00
V_fixture = 1.50
V_fixture_min = 1.40
V_fixture_max = 1.60
| time   V(typ)   V(min)   V(max)
0s        1.5V       1.4V       1.6V
600ps     1.5V       1.4V       1.6V
900ps     1.47V      1.4V       1.22V
1.2ns     1.22V      1.39V      710mV
1.5ns     750mV      1.21V      500mV
1.8ns     510mV      830mV      440mV
2.1ns     470mV      650mV      430mV
2.4ns     460mV      580mV      430mV
3.3ns     450mV      530mV      430mV
15ns      450mV      520mV      430mV
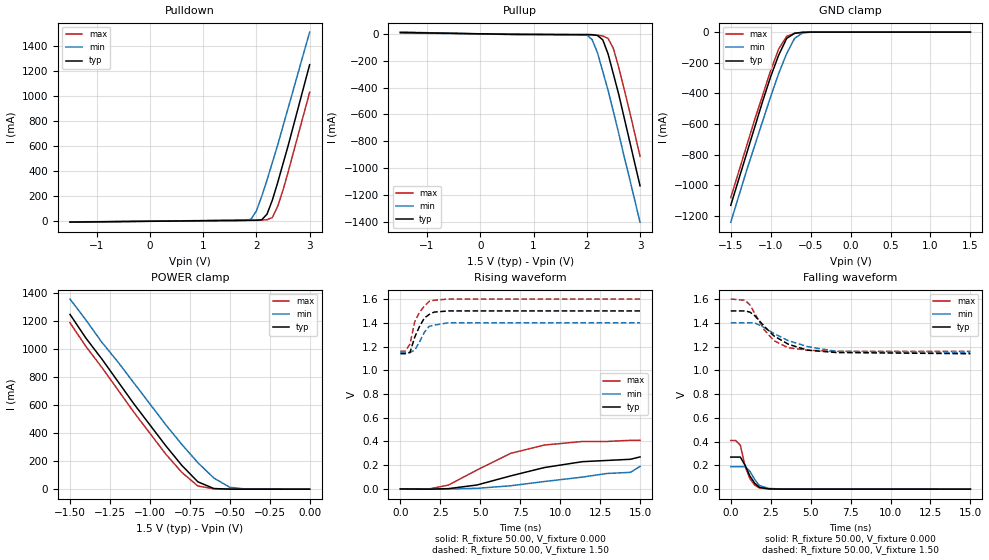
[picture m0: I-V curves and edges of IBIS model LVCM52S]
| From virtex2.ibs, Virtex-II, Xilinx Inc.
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|   Model LVCM52S
[Model]   LVCM52S
Model_type   I/O
Polarity   Non-Inverting
Enable   Active-Low
Vinh = 1.05V
Vinl = 0.3V
Vmeas =   0.75V
Cref =  0pF
Rref =   1.00M
Vref =  0.000V
C_comp   10.00pF   10.00pF   10.00pF
[Temperature Range]   25.00   100.00   0.000
[Voltage Range]   1.50V   1.40V   1.60V
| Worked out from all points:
|   slope of the pulldown table from 0 to 0.225 V, typ, clamps not added: 116 ohm
|   slope of the pullup table from 0 to 0.225 V, typ, clamps not added: 95 ohm
|   GND clamp passes 1 mA (typ) near -0.57 V on its own axis
|   POWER clamp passes 1 mA (typ) near -0.52 V on its own axis
|   rising waveform, R_fixture 50.00, V_fixture 0.000: 20-80 % time 5.24ns typ, 6.91ns min, 3.93ns max; typ from 0 V to 0.27 V
|   rising waveform, R_fixture 50.00, V_fixture 1.50: 20-80 % time 705ps typ, 651ps min, 688ps max; typ from 1.14 V to 1.5 V
|   falling waveform, R_fixture 50.00, V_fixture 0.000: 20-80 % time 647ps typ, 567ps min, 562ps max; typ from 0.27 V to 0 V
|   falling waveform, R_fixture 50.00, V_fixture 1.50: 20-80 % time 2.03ns typ, 2.6ns min, 1.37ns max; typ from 1.5 V to 1.14 V
[Pulldown]
| voltage   I(typ)   I(min)   I(max)
-1.5V     -5.49mA    -3.66mA    -6.35mA
1.7V      8.25mA     5.89mA     10.55mA
1.8V      8.32mA     6.68mA     10.67mA
1.9V      8.39mA     18.67mA    10.75mA
2V        8.66mA     83.6mA     10.82mA
2.1V      12.6mA     200mA      11.08mA
2.2V      58.25mA    330mA      13.14mA
2.3V      170mA      470mA      31.58mA
2.4V      310mA      610mA      120mA
2.5V      460mA      760mA      250mA
2.6V      610mA      910mA      400mA
3V        1.25A      1.51A      1.03A
[Pullup]
| voltage   I(typ)   I(min)   I(max)
-1.5V     9.06mA     4.92mA     12.02mA
600mV     -4.5mA     -3.27mA    -6.63mA
2V        -5.91mA    -9.56mA    -8.92mA
2.1V      -7.15mA    -43.26mA   -9.08mA
2.2V      -13.13mA   -140mA     -10.48mA
2.3V      -45.23mA   -280mA     -16.79mA
2.4V      -150mA     -420mA     -34.91mA
2.5V      -300mA     -580mA     -110mA
2.6V      -450mA     -740mA     -250mA
2.7V      -620mA     -910mA     -410mA
2.8V      -790mA     -1.07A     -570mA
3V        -1.13A     -1.4A      -910mA
[GND_clamp]
| voltage   I(typ)   I(min)   I(max)
-1.5V     -1.13A     -1.24A     -1.08A
-1.3V     -790mA     -900mA     -740mA
-1.2V     -620mA     -740mA     -570mA
-1.1V     -450mA     -580mA     -410mA
-1V       -290mA     -420mA     -250mA
-900mV    -150mA     -270mA     -110mA
-800mV    -40.96mA   -140mA     -27.15mA
-700mV    -7.52mA    -40.16mA   -8.06mA
-600mV    -1.38mA    -5.56mA    -1.57mA
-500mV    -120uA     -650uA     -120uA
1.5V      27.96pA    98.69nA    16.96pA
[POWER_clamp]
| voltage   I(typ)   I(min)   I(max)
-1.5V     1.25A      1.36A      1.19A
-1.4V     1.08A      1.21A      1.02A
-1.3V     930mA      1.05A      870mA
-1.2V     770mA      910mA      710mA
-1.1V     610mA      760mA      550mA
-900mV    310mA      460mA      250mA
-800mV    170mA      320mA      120mA
-700mV    52.75mA    190mA      22.81mA
-600mV    4.57mA     79.88mA    2.44mA
-500mV    270uA      13.45mA    250uA
-400mV    16.38uA    820uA      14.46uA
0V        27.96pA    880pA      24.27pA
[Ramp]
| variable   typ   min   max
dV/dt_r   0.15/4.83n   89.34m/5.30n   0.24/3.82n
dV/dt_f   0.21/1.95n   0.15/2.71n   0.26/1.44n
R_load = 50.00
[Rising Waveform]
R_fixture = 50.00
V_fixture = 0.000
| time   V(typ)   V(min)   V(max)
0s        0V         0V         0V
1.8ns     -1.76mV    -1.39mV    560uV
3ns       2.61mV     -130uV     32.41mV
4.8ns     33.47mV    5.32mV     160mV
6.9ns     110mV      26.84mV    300mV
9ns       180mV      62.4mV     370mV
11.4ns    230mV      100mV      400mV
12.9ns    240mV      130mV      400mV
14.4ns    250mV      140mV      410mV
15ns      270mV      190mV      410mV
[Rising Waveform]
R_fixture = 50.00
V_fixture = 1.50
V_fixture_min = 1.40
V_fixture_max = 1.60
| time   V(typ)   V(min)   V(max)
0s        1.14V      1.15V      1.16V
300ps     1.14V      1.15V      1.16V
600ps     1.15V      1.15V      1.22V
900ps     1.28V      1.17V      1.41V
1.2ns     1.37V      1.24V      1.49V
1.5ns     1.44V      1.32V      1.54V
1.8ns     1.47V      1.37V      1.58V
2.1ns     1.49V      1.38V      1.59V
3ns       1.5V       1.4V       1.6V
15ns      1.5V       1.4V       1.6V
[Falling Waveform]
R_fixture = 50.00
V_fixture = 0.000
| time   V(typ)   V(min)   V(max)
0s        270mV      190mV      410mV
300ps     270mV      190mV      410mV
600ps     270mV      190mV      370mV
900ps     200mV      190mV      190mV
1.2ns     110mV      150mV      87.61mV
1.5ns     49.67mV    81.61mV    34.57mV
1.8ns     14.94mV    29.74mV    9.89mV
2.4ns     2.3mV      5.84mV     1.22mV
3.3ns     160uV      760uV      160uV
15ns      -1.31uV    40.41uV    -14.49uV
[Falling Waveform]
R_fixture = 50.00
V_fixture = 1.50
V_fixture_min = 1.40
V_fixture_max = 1.60
| time   V(typ)   V(min)   V(max)
0s        1.5V       1.4V       1.6V
900ps     1.5V       1.4V       1.59V
1.2ns     1.49V      1.4V       1.55V
1.5ns     1.46V      1.4V       1.48V
2.1ns     1.37V      1.36V      1.34V
2.7ns     1.29V      1.31V      1.25V
3.6ns     1.22V      1.25V      1.19V
4.8ns     1.17V      1.2V       1.17V
6.6ns     1.15V      1.16V      1.16V
15ns      1.14V      1.15V      1.16V
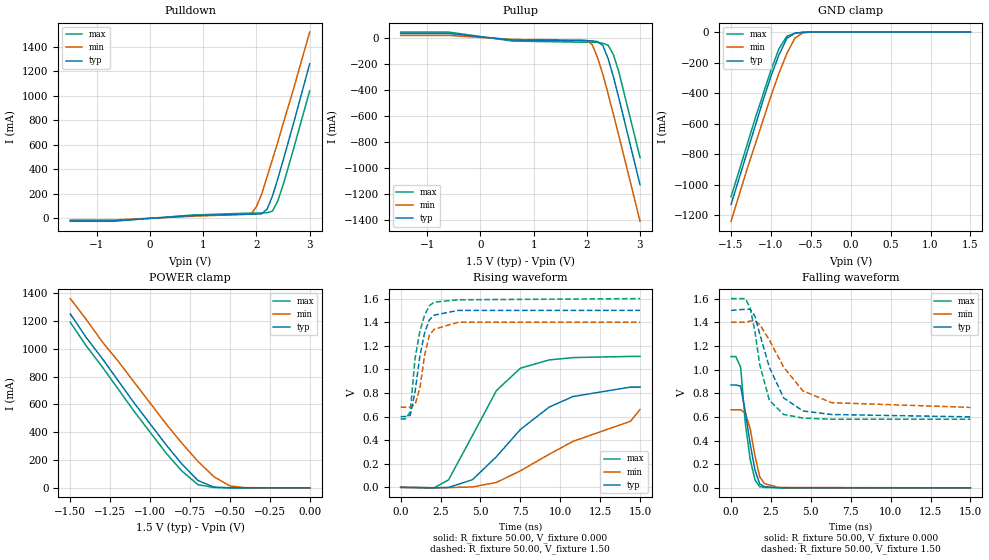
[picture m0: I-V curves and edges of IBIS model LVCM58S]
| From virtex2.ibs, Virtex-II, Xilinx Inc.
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|   Model LVCM58S
[Model]   LVCM58S
Model_type   I/O
Polarity   Non-Inverting
Enable   Active-Low
Vinh = 1.05V
Vinl = 0.3V
Vmeas =   0.75V
Cref =  0pF
Rref =   1.00M
Vref =  0.000V
C_comp   10.00pF   10.00pF   10.00pF
[Temperature Range]   25.00   100.00   0.000
[Voltage Range]   1.50V   1.40V   1.60V
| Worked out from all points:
|   slope of the pulldown table from 0 to 0.225 V, typ, clamps not added: 29.9 ohm
|   slope of the pullup table from 0 to 0.225 V, typ, clamps not added: 25.4 ohm
|   GND clamp passes 1 mA (typ) near -0.57 V on its own axis
|   POWER clamp passes 1 mA (typ) near -0.52 V on its own axis
|   rising waveform, R_fixture 50.00, V_fixture 0.000: 20-80 % time 3.9ns typ, 6.06ns min, 2.69ns max; typ from 0 V to 0.85 V
|   rising waveform, R_fixture 50.00, V_fixture 1.50: 20-80 % time 672ps typ, 574ps min, 667ps max; typ from 0.6 V to 1.5 V
|   falling waveform, R_fixture 50.00, V_fixture 0.000: 20-80 % time 644ps typ, 597ps min, 549ps max; typ from 0.87 V to 0 V
|   falling waveform, R_fixture 50.00, V_fixture 1.50: 20-80 % time 1.42ns typ, 2.1ns min, 904ps max; typ from 1.5 V to 0.6 V
[Pulldown]
| voltage   I(typ)   I(min)   I(max)
-1.5V     -21.47mA   -14.42mA   -24.67mA
-700mV    -21.47mA   -14.42mA   -24.67mA
800mV     22.14mA    16.2mA     26.52mA
1.9V      33.17mA    34.37mA    42.43mA
2V        33.53mA    94.82mA    42.7mA
2.1V      36.6mA     200mA      43.05mA
2.2V      75.06mA    340mA      44.78mA
2.3V      180mA      480mA      58.46mA
2.4V      320mA      620mA      140mA
2.5V      470mA      770mA      270mA
2.7V      780mA      1.06A      570mA
3V        1.26A      1.52A      1.04A
[Pullup]
| voltage   I(typ)   I(min)   I(max)
-1.5V     34.03mA    18.7mA     44.55mA
-600mV    34.03mA    18.7mA     44.55mA
600mV     -16.93mA   -12.32mA   -24.89mA
1.9V      -21.75mA   -16.25mA   -33.42mA
2V        -21.99mA   -20.67mA   -33.66mA
2.1V      -23.18mA   -51.96mA   -33.96mA
2.2V      -28.75mA   -150mA     -35.25mA
2.3V      -57.37mA   -280mA     -41.07mA
2.4V      -160mA     -430mA     -56.91mA
2.5V      -300mA     -590mA     -130mA
2.6V      -460mA     -750mA     -260mA
3V        -1.13A     -1.41A     -920mA
[GND_clamp]
| voltage   I(typ)   I(min)   I(max)
-1.5V     -1.13A     -1.24A     -1.08A
-1.3V     -790mA     -900mA     -740mA
-1.2V     -620mA     -740mA     -570mA
-1.1V     -450mA     -580mA     -410mA
-1V       -290mA     -420mA     -250mA
-900mV    -150mA     -270mA     -110mA
-800mV    -40.96mA   -140mA     -27.15mA
-700mV    -7.52mA    -40.16mA   -8.06mA
-600mV    -1.38mA    -5.56mA    -1.57mA
-500mV    -120uA     -650uA     -120uA
1.5V      27.96pA    98.69nA    16.96pA
[POWER_clamp]
| voltage   I(typ)   I(min)   I(max)
-1.5V     1.25A      1.36A      1.19A
-1.4V     1.08A      1.21A      1.02A
-1.3V     930mA      1.05A      870mA
-1.2V     770mA      910mA      710mA
-1.1V     610mA      760mA      550mA
-900mV    310mA      460mA      250mA
-800mV    170mA      320mA      120mA
-700mV    52.75mA    190mA      22.81mA
-600mV    4.57mA     79.88mA    2.44mA
-500mV    270uA      13.45mA    250uA
-400mV    16.38uA    820uA      14.46uA
0V        27.96pA    880pA      24.27pA
[Ramp]
| variable   typ   min   max
dV/dt_r   0.51/3.98n   0.34/4.76n   0.67/2.67n
dV/dt_f   0.54/1.39n   0.43/2.08n   0.61/0.95n
R_load = 50.00
[Rising Waveform]
R_fixture = 50.00
V_fixture = 0.000
| time   V(typ)   V(min)   V(max)
0s        0V         0V         0V
2.1ns     -4.04mV    -3.71mV    -3.21mV
3ns       -950uV     -2.12mV    63.32mV
4.5ns     64.93mV    3.52mV     440mV
6ns       260mV      41.87mV    820mV
7.5ns     490mV      140mV      1.01V
9.3ns     680mV      280mV      1.08V
10.8ns    770mV      390mV      1.1V
14.4ns    850mV      560mV      1.11V
15ns      850mV      660mV      1.11V
[Rising Waveform]
R_fixture = 50.00
V_fixture = 1.50
V_fixture_min = 1.40
V_fixture_max = 1.60
| time   V(typ)   V(min)   V(max)
0s        600mV      680mV      580mV
300ps     600mV      680mV      580mV
600ps     610mV      680mV      640mV
900ps     810mV      700mV      1.09V
1.2ns     1.11V      840mV      1.32V
1.5ns     1.31V      1.12V      1.46V
1.8ns     1.42V      1.29V      1.54V
2.1ns     1.46V      1.34V      1.57V
3.6ns     1.5V       1.4V       1.59V
15ns      1.5V       1.4V       1.6V
[Falling Waveform]
R_fixture = 50.00
V_fixture = 0.000
| time   V(typ)   V(min)   V(max)
0s        870mV      660mV      1.11V
300ps     870mV      660mV      1.11V
600ps     860mV      660mV      1.02V
900ps     640mV      630mV      540mV
1.2ns     370mV      500mV      240mV
1.5ns     150mV      270mV      66.81mV
1.8ns     32.04mV    91.74mV    9.11mV
2.1ns     9.2mV      35.3mV     3.4mV
3ns       680uV      2.65mV     640uV
15ns      -55.39uV   14.43uV    35.15uV
[Falling Waveform]
R_fixture = 50.00
V_fixture = 1.50
V_fixture_min = 1.40
V_fixture_max = 1.60
| time   V(typ)   V(min)   V(max)
0s        1.5V       1.4V       1.6V
900ps     1.51V      1.4V       1.6V
1.2ns     1.51V      1.41V      1.52V
1.5ns     1.45V      1.41V      1.32V
1.8ns     1.3V       1.38V      1.04V
2.4ns     1.02V      1.25V      740mV
3.3ns     760mV      1.02V      620mV
4.5ns     650mV      820mV      590mV
6.3ns     620mV      720mV      580mV
15ns      600mV      680mV      580mV
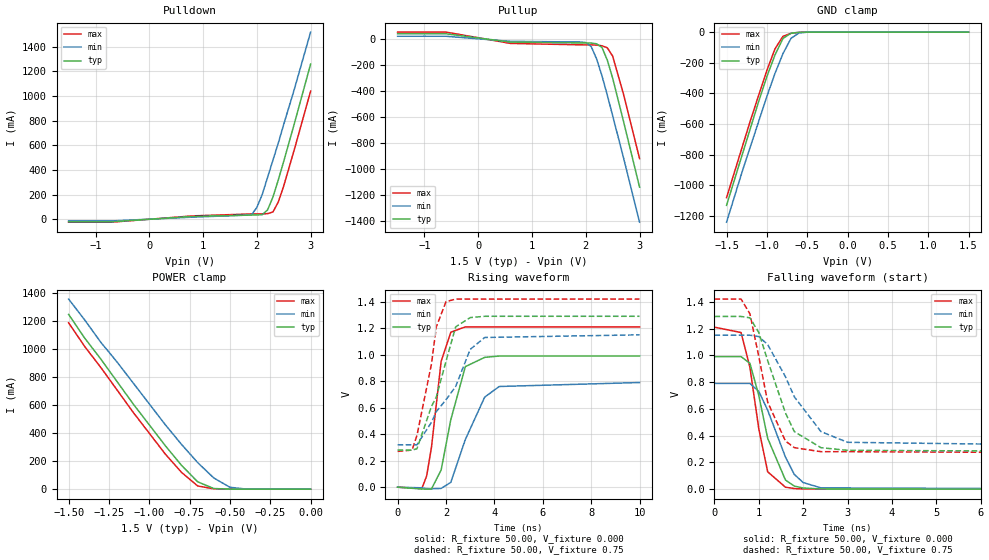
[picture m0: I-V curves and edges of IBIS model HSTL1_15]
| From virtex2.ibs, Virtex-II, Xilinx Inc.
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|   Model HSTL1_15
[Model]   HSTL1_15
Model_type   I/O
Polarity   Non-Inverting
Enable   Active-Low
Vinh = 0.85V
Vinl = 0.65V
Vmeas =   0.75V
Cref =  0pF
Rref =  50.00
Vref =   0.75V
C_comp   10.00pF   10.00pF   10.00pF
[Temperature Range]   25.00   100.00   0.000
[Voltage Range]   1.50V   1.40V   1.60V
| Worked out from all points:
|   slope of the pulldown table from 0 to 0.225 V, typ, clamps not added: 29.9 ohm
|   slope of the pullup table from 0 to 0.225 V, typ, clamps not added: 20.1 ohm
|   GND clamp passes 1 mA (typ) near -0.57 V on its own axis
|   POWER clamp passes 1 mA (typ) near -0.52 V on its own axis
|   rising waveform, R_fixture 50.00, V_fixture 0.000: 20-80 % time 677ps typ, 944ps min, 476ps max; typ from 0 V to 0.99 V
|   rising waveform, R_fixture 50.00, V_fixture 0.75: 20-80 % time 1.07ns typ, 1.47ns min, 656ps max; typ from 0.28 V to 1.29 V
|   falling waveform, R_fixture 50.00, V_fixture 0.000: 20-80 % time 480ps typ, 586ps min, 375ps max; typ from 0.99 V to 0 V
|   falling waveform, R_fixture 50.00, V_fixture 0.75: 20-80 % time 648ps typ, 805ps min, 501ps max; typ from 1.29 V to 0.28 V
[Pulldown]
| voltage   I(typ)   I(min)   I(max)
-1.5V     -21.47mA   -14.42mA   -24.67mA
-700mV    -21.47mA   -14.42mA   -24.67mA
800mV     22.14mA    16.2mA     26.52mA
1.9V      33.17mA    34.37mA    42.43mA
2V        33.53mA    94.82mA    42.7mA
2.1V      36.6mA     200mA      43.05mA
2.2V      75.06mA    340mA      44.78mA
2.3V      180mA      480mA      58.46mA
2.4V      320mA      620mA      140mA
2.5V      470mA      770mA      270mA
2.7V      780mA      1.06A      570mA
3V        1.26A      1.52A      1.04A
[Pullup]
| voltage   I(typ)   I(min)   I(max)
-1.5V     42.91mA    23.69mA    55.94mA
-600mV    42.91mA    23.69mA    55.94mA
600mV     -21.39mA   -15.57mA   -31.41mA
1.9V      -27.5mA    -20.38mA   -42.26mA
2V        -27.77mA   -24.68mA   -42.56mA
2.1V      -28.95mA   -55.13mA   -42.91mA
2.2V      -34.38mA   -150mA     -44.18mA
2.3V      -61.84mA   -280mA     -49.83mA
2.4V      -160mA     -430mA     -64.98mA
2.5V      -300mA     -590mA     -130mA
2.7V      -630mA     -910mA     -420mA
3V        -1.14A     -1.41A     -920mA
[GND_clamp]
| voltage   I(typ)   I(min)   I(max)
-1.5V     -1.13A     -1.24A     -1.08A
-1.3V     -790mA     -900mA     -740mA
-1.2V     -620mA     -740mA     -570mA
-1.1V     -450mA     -580mA     -410mA
-1V       -290mA     -420mA     -250mA
-900mV    -150mA     -270mA     -110mA
-800mV    -40.96mA   -140mA     -27.15mA
-700mV    -7.52mA    -40.16mA   -8.06mA
-600mV    -1.38mA    -5.56mA    -1.57mA
-500mV    -120uA     -650uA     -120uA
1.5V      27.96pA    98.69nA    16.96pA
[POWER_clamp]
| voltage   I(typ)   I(min)   I(max)
-1.5V     1.25A      1.36A      1.19A
-1.4V     1.08A      1.21A      1.02A
-1.3V     930mA      1.05A      870mA
-1.2V     770mA      910mA      710mA
-1.1V     610mA      760mA      550mA
-900mV    310mA      460mA      250mA
-800mV    170mA      320mA      120mA
-700mV    52.75mA    190mA      22.81mA
-600mV    4.57mA     79.88mA    2.44mA
-500mV    270uA      13.45mA    250uA
-400mV    16.38uA    820uA      14.46uA
0V        27.96pA    880pA      24.27pA
[Ramp]
| variable   typ   min   max
dV/dt_r   0.59/0.65n   0.47/0.92n   0.72/0.44n
dV/dt_f   0.54/0.69n   0.43/1.01n   0.61/0.52n
R_load = 50.00
[Rising Waveform]
R_fixture = 50.00
V_fixture = 0.000
| time   V(typ)   V(min)   V(max)
0s        0V         0V         0V
1ns       -13.99mV   -4.92mV    -11.17mV
1.2ns     -15mV      -10.76mV   84.15mV
1.4ns     -13.85mV   -12.15mV   300mV
1.8ns     130mV      -9.39mV    950mV
2.2ns     510mV      36.62mV    1.17V
2.8ns     910mV      360mV      1.21V
3.6ns     980mV      680mV      1.21V
4.2ns     990mV      760mV      1.21V
10ns      990mV      790mV      1.21V
[Rising Waveform]
R_fixture = 50.00
V_fixture = 0.75
V_fixture_min = 0.70
V_fixture_max = 0.80
| time   V(typ)   V(min)   V(max)
0s        280mV      320mV      270mV
600ps     280mV      320mV      280mV
800ps     290mV      320mV      390mV
1.4ns     610mV      490mV      930mV
1.6ns     680mV      570mV      1.21V
2ns       950mV      660mV      1.4V
2.4ns     1.21V      760mV      1.42V
3ns       1.28V      1.04V      1.42V
3.6ns     1.29V      1.13V      1.42V
10ns      1.29V      1.15V      1.42V
[Falling Waveform]
R_fixture = 50.00
V_fixture = 0.000
| time   V(typ)   V(min)   V(max)
0s        990mV      790mV      1.21V
600ps     990mV      790mV      1.17V
800ps     940mV      790mV      910mV
1ns       700mV      730mV      450mV
1.2ns     380mV      590mV      130mV
1.6ns     68.59mV    240mV      14.66mV
1.8ns     23.08mV    110mV      4.58mV
2ns       8.52mV     49.37mV    1.84mV
2.4ns     1.68mV     9.68mV     720uV
10ns      -1.8uV     -2.88uV    -3.05uV
[Falling Waveform]
R_fixture = 50.00
V_fixture = 0.75
V_fixture_min = 0.70
V_fixture_max = 0.80
| time   V(typ)   V(min)   V(max)
0s        1.29V      1.15V      1.42V
600ps     1.29V      1.15V      1.42V
800ps     1.28V      1.15V      1.31V
1ns       1.17V      1.14V      990mV
1.2ns     960mV      1.08V      650mV
1.6ns     570mV      840mV      360mV
1.8ns     430mV      690mV      310mV
2.4ns     310mV      430mV      280mV
3ns       290mV      350mV      280mV
10ns      280mV      320mV      270mV
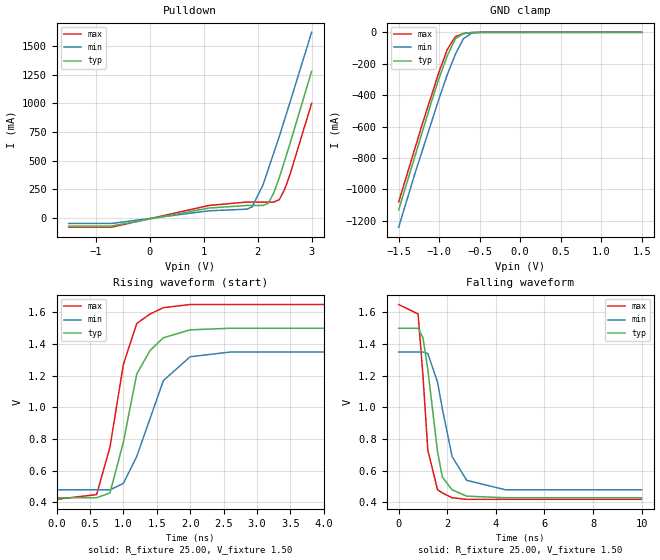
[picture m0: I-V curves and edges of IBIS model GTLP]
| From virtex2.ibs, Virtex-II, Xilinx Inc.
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|   Model GTLP
[Model]   GTLP
Model_type   I/O_open_drain
Polarity   Non-Inverting
Enable   Active-Low
Vinh = 1.1V
Vinl = 0.9V
Vmeas =   1.00V
Cref =  0F
Rref =  25.00
Vref =   1.50V
C_comp   10.00pF   10.00pF   10.00pF
[Temperature Range]   25.00   100.00   0.000
[Voltage Range]   1.50V   1.35V   1.65V
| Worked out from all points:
|   slope of the pulldown table from 0 to 0.225 V, typ, clamps not added: 9.45 ohm
|   GND clamp passes 1 mA (typ) near -0.57 V on its own axis
|   rising waveform, R_fixture 25.00, V_fixture 1.50: 20-80 % time 386ps typ, 453ps min, 359ps max; typ from 0.43 V to 1.5 V
|   falling waveform, R_fixture 25.00, V_fixture 1.50: 20-80 % time 541ps typ, 715ps min, 380ps max; typ from 1.5 V to 0.43 V
[Pulldown]
| voltage   I(typ)   I(min)   I(max)
-1.5V     -68.82mA   -46.42mA   -79.05mA
-700mV    -68.82mA   -46.42mA   -78.65mA
1.1V      87.62mA    63.65mA    110mA
1.8V      110mA      77.77mA    140mA
1.9V      110mA      98.04mA    140mA
2.1V      110mA      290mA      140mA
2.2V      130mA      430mA      140mA
2.3V      220mA      570mA      140mA
2.4V      350mA      710mA      160mA
2.5V      500mA      860mA      250mA
2.6V      650mA      1.01A      380mA
3V        1.28A      1.62A      1A
[GND_clamp]
| voltage   I(typ)   I(min)   I(max)
-1.5V     -1.13A     -1.24A     -1.08A
-1.3V     -790mA     -900mA     -740mA
-1.2V     -620mA     -740mA     -570mA
-1.1V     -450mA     -580mA     -410mA
-1V       -290mA     -420mA     -250mA
-900mV    -150mA     -270mA     -110mA
-800mV    -40.96mA   -140mA     -27.15mA
-700mV    -7.52mA    -40.16mA   -8.07mA
-600mV    -1.38mA    -5.56mA    -1.57mA
-500mV    -120uA     -650uA     -120uA
1.5V      27.96pA    460nA      15.61pA
[Ramp]
| variable   typ   min   max
dV/dt_r   0.64/0.33n   0.52/0.39n   0.74/0.31n
dV/dt_f   0.64/0.46n   0.52/0.70n   0.74/0.33n
R_load = 25.00
[Rising Waveform]
R_fixture = 25.00
V_fixture = 1.50
V_fixture_min = 1.35
V_fixture_max = 1.65
| time   V(typ)   V(min)   V(max)
0s        430mV      480mV      420mV
600ps     430mV      480mV      450mV
800ps     460mV      480mV      750mV
1ns       780mV      520mV      1.27V
1.2ns     1.21V      690mV      1.53V
1.4ns     1.36V      930mV      1.59V
1.6ns     1.44V      1.17V      1.63V
2ns       1.49V      1.32V      1.65V
2.6ns     1.5V       1.35V      1.65V
10ns      1.5V       1.35V      1.65V
[Falling Waveform]
R_fixture = 25.00
V_fixture = 1.50
V_fixture_min = 1.35
V_fixture_max = 1.65
| time   V(typ)   V(min)   V(max)
0s        1.5V       1.35V      1.65V
800ps     1.5V       1.35V      1.59V
1ns       1.44V      1.35V      1.2V
1.2ns     1.24V      1.34V      730mV
1.6ns     720mV      1.16V      480mV
1.8ns     560mV      990mV      460mV
2.2ns     480mV      690mV      430mV
2.8ns     440mV      540mV      420mV
4.4ns     430mV      480mV      420mV
10ns      430mV      480mV      420mV
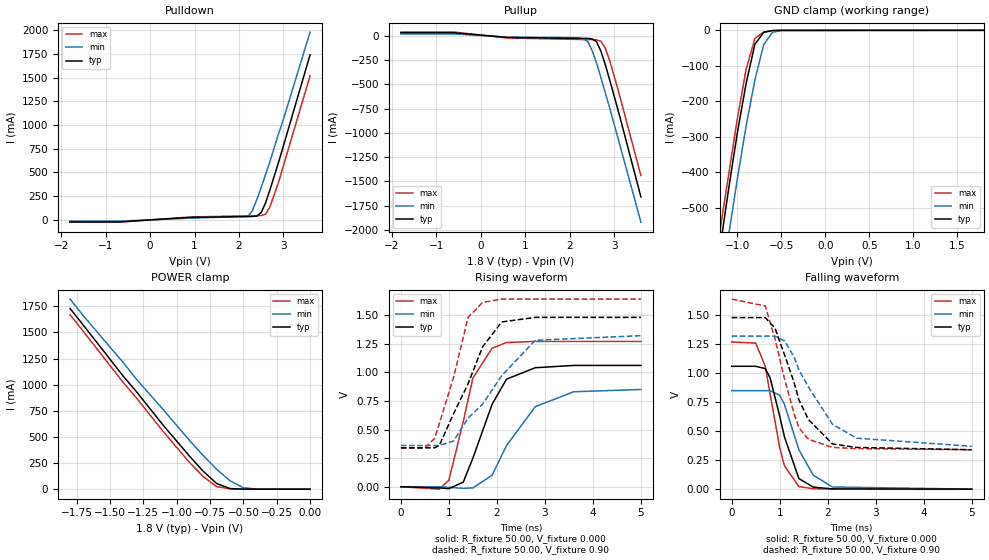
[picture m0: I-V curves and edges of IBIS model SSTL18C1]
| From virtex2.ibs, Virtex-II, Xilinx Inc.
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|   Model SSTL18C1
[Model]   SSTL18C1
Model_type   I/O
Polarity   Non-Inverting
Enable   Active-Low
Vinh = 1.025v
Vinl = 0.775v
Vmeas =   0.90V
Cref =  0pF
Rref =  50.00
Vref =   0.90V
C_comp   10.00pF   10.00pF   10.00pF
[Temperature Range]   25.00   100.00   0.000
[Voltage Range]   1.80V   1.70V   1.90V
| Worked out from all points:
|   slope of the pulldown table from 0 to 0.27 V, typ, clamps not added: 29.1 ohm
|   slope of the pullup table from 0 to 0.27 V, typ, clamps not added: 26.6 ohm
|   GND clamp passes 1 mA (typ) near -0.61 V on its own axis
|   POWER clamp passes 1 mA (typ) near -0.51 V on its own axis
|   rising waveform, R_fixture 50.00, V_fixture 0.000: 20-80 % time 588ps typ, 760ps min, 432ps max; typ from 0 V to 1.06 V
|   rising waveform, R_fixture 50.00, V_fixture 0.90: 20-80 % time 726ps typ, 1.04ns min, 496ps max; typ from 0.34 V to 1.48 V
|   falling waveform, R_fixture 50.00, V_fixture 0.000: 20-80 % time 396ps typ, 471ps min, 348ps max; typ from 1.06 V to 0 V
|   falling waveform, R_fixture 50.00, V_fixture 0.90: 20-80 % time 616ps typ, 791ps min, 492ps max; typ from 1.48 V to 0.34 V
[Pulldown]
| voltage   I(typ)   I(min)   I(max)
-1.8V     -22.43mA   -14.43mA   -25.5mA
-700mV    -22.43mA   -14.43mA   -25.5mA
900mV     24.93mA    17.53mA    29.31mA
2.2V      34.25mA    34.8mA     41.86mA
2.3V      34.66mA    95.09mA    41.97mA
2.4V      38.31mA    210mA      42.34mA
2.5V      76.54mA    340mA      44.73mA
2.6V      180mA      480mA      59.03mA
2.7V      320mA      620mA      140mA
2.9V      620mA      920mA      410mA
3V        780mA      1.06A      570mA
3.6V      1.74A      1.98A      1.52A
[Pullup]
| voltage   I(typ)   I(min)   I(max)
-1.8V     29.35mA    17.06mA    36.57mA
-600mV    29.35mA    17.06mA    36.57mA
600mV     -18.84mA   -14.55mA   -24.59mA
2.2V      -28.12mA   -21.34mA   -38.85mA
2.4V      -29.08mA   -55.84mA   -39.41mA
2.5V      -33.23mA   -150mA     -40.04mA
2.6V      -60.46mA   -280mA     -43.55mA
2.7V      -160mA     -430mA     -57.58mA
2.8V      -300mA     -590mA     -130mA
2.9V      -460mA     -750mA     -260mA
3.1V      -790mA     -1.08A     -580mA
3.6V      -1.66A     -1.92A     -1.44A
[GND_clamp]
| voltage   I(typ)   I(min)   I(max)
-1.8V     -1.65A     -1.74A     -1.6A
-1.2V     -620mA     -740mA     -570mA
-1.1V     -450mA     -580mA     -410mA
-1V       -290mA     -420mA     -250mA
-900mV    -150mA     -270mA     -110mA
-800mV    -39.2mA    -140mA     -23mA
-700mV    -5.61mA    -40.17mA   -4.8mA
-600mV    -750uA     -5.57mA    -620uA
-500mV    -57.3uA    -660uA     -36.33uA
1.8V      30.92pA    98.88nA    20.22pA
[POWER_clamp]
| voltage   I(typ)   I(min)   I(max)
-1.8V     1.73A      1.82A      1.67A
-1.7V     1.57A      1.66A      1.51A
-1.4V     1.08A      1.21A      1.02A
-1.3V     930mA      1.05A      870mA
-1.1V     610mA      760mA      550mA
-900mV    310mA      460mA      250mA
-800mV    170mA      320mA      120mA
-700mV    53.56mA    190mA      24.17mA
-600mV    5.5mA      79.88mA    3.5mA
-500mV    490uA      13.45mA    470uA
-400mV    34.21uA    820uA      28.36uA
0V        30.92pA    1.07nA     28.99pA
[Ramp]
| variable   typ   min   max
dV/dt_r   0.64/0.57n   0.51/0.80n   0.76/0.43n
dV/dt_f   0.64/0.76n   0.50/1.09n   0.72/0.59n
R_load = 50.00
[Rising Waveform]
R_fixture = 50.00
V_fixture = 0.000
| time   V(typ)   V(min)   V(max)
0s        0V         0V         0V
800ps     -9.52mV    -300uV     -21.25mV
1ns       -17.24mV   -5.02mV    56.09mV
1.3ns     40.76mV    -14.5mV    570mV
1.5ns     250mV      -9.9mV     950mV
1.9ns     720mV      100mV      1.21V
2.2ns     940mV      360mV      1.26V
2.8ns     1.04V      700mV      1.27V
3.6ns     1.06V      830mV      1.27V
5ns       1.06V      850mV      1.27V
[Rising Waveform]
R_fixture = 50.00
V_fixture = 0.90
V_fixture_min = 0.79
V_fixture_max = 1.01
| time   V(typ)   V(min)   V(max)
0s        340mV      360mV      340mV
500ps     340mV      360mV      340mV
700ps     340mV      360mV      420mV
800ps     360mV      360mV      550mV
1.1ns     640mV      400mV      960mV
1.4ns     900mV      600mV      1.48V
1.7ns     1.22V      720mV      1.61V
2.1ns     1.44V      970mV      1.64V
2.8ns     1.48V      1.28V      1.64V
5ns       1.48V      1.32V      1.64V
[Falling Waveform]
R_fixture = 50.00
V_fixture = 0.000
| time   V(typ)   V(min)   V(max)
0s        1.06V      850mV      1.27V
500ps     1.06V      850mV      1.26V
700ps     1.04V      850mV      1.06V
800ps     960mV      850mV      820mV
1ns       630mV      810mV      360mV
1.1ns     450mV      730mV      200mV
1.4ns     91.35mV    340mV      22.19mV
1.7ns     17.79mV    120mV      3.93mV
2.1ns     2.31mV     18.83mV    1.06mV
5ns       21.01uV    110uV      3.42uV
[Falling Waveform]
R_fixture = 50.00
V_fixture = 0.90
V_fixture_min = 0.79
V_fixture_max = 1.01
| time   V(typ)   V(min)   V(max)
0s        1.48V      1.32V      1.64V
700ps     1.48V      1.32V      1.58V
900ps     1.39V      1.32V      1.3V
1.1ns     1.16V      1.28V      950mV
1.3ns     920mV      1.14V      650mV
1.4ns     770mV      1.03V      530mV
1.6ns     600mV      880mV      430mV
2.1ns     390mV      560mV      360mV
2.6ns     360mV      440mV      350mV
5ns       340mV      370mV      340mV
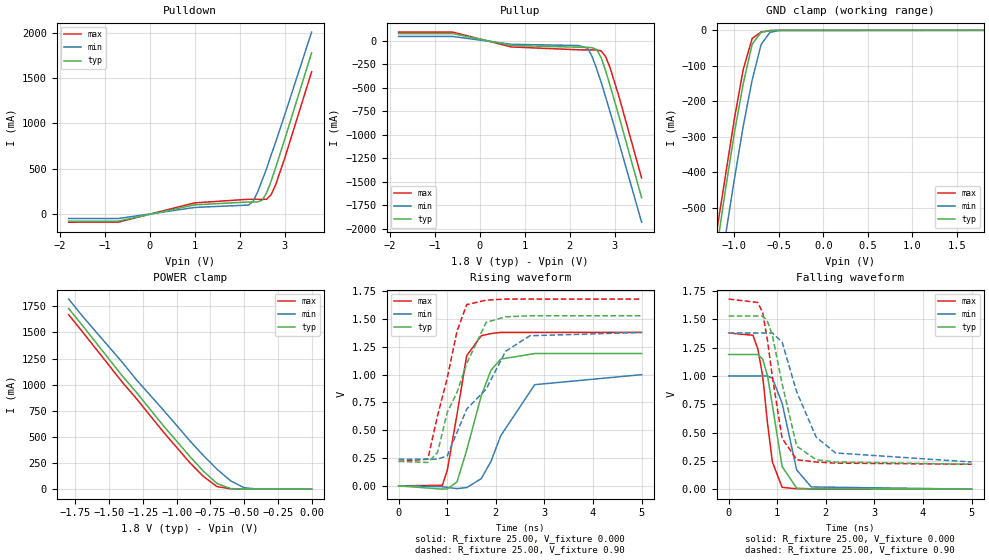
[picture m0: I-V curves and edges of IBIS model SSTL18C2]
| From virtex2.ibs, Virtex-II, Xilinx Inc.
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|   Model SSTL18C2
[Model]   SSTL18C2
Model_type   I/O
Polarity   Non-Inverting
Enable   Active-Low
Vinh = 1.025v
Vinl = 0.775v
Vmeas =   0.90V
Cref =  0pF
Rref =  25.00
Vref =   0.90V
C_comp   10.00pF   10.00pF   10.00pF
[Temperature Range]   25.00   100.00   0.000
[Voltage Range]   1.80V   1.70V   1.90V
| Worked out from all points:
|   slope of the pulldown table from 0 to 0.27 V, typ, clamps not added: 8.03 ohm
|   slope of the pullup table from 0 to 0.27 V, typ, clamps not added: 10.7 ohm
|   GND clamp passes 1 mA (typ) near -0.61 V on its own axis
|   POWER clamp passes 1 mA (typ) near -0.51 V on its own axis
|   rising waveform, R_fixture 25.00, V_fixture 0.000: 20-80 % time 448ps typ, 672ps min, 312ps max; typ from 0 V to 1.19 V
|   rising waveform, R_fixture 25.00, V_fixture 0.90: 20-80 % time 635ps typ, 945ps min, 446ps max; typ from 0.22 V to 1.53 V
|   falling waveform, R_fixture 25.00, V_fixture 0.000: 20-80 % time 266ps typ, 314ps min, 233ps max; typ from 1.19 V to 0 V
|   falling waveform, R_fixture 25.00, V_fixture 0.90: 20-80 % time 381ps typ, 563ps min, 304ps max; typ from 1.53 V to 0.22 V
[Pulldown]
| voltage   I(typ)   I(min)   I(max)
-1.8V     -82.52mA   -53.41mA   -93.7mA
-700mV    -82.52mA   -53.41mA   -93.17mA
1V        98.33mA    69.33mA    120mA
2.2V      130mA      95.95mA    160mA
2.3V      130mA      140mA      160mA
2.4V      130mA      240mA      160mA
2.5V      150mA      370mA      160mA
2.6V      230mA      500mA      160mA
2.7V      360mA      650mA      210mA
2.8V      510mA      790mA      320mA
3V        820mA      1.09A      610mA
3.6V      1.78A      2.01A      1.57A
[Pullup]
| voltage   I(typ)   I(min)   I(max)
-1.8V     73.28mA    43.61mA    89.83mA
-600mV    73.28mA    43.61mA    89.83mA
700mV     -51.79mA   -39.78mA   -67.86mA
2.2V      -71.3mA    -53.17mA   -98.46mA
2.4V      -72.65mA   -80.97mA   -99.83mA
2.5V      -76.03mA   -170mA     -100mA
2.6V      -95.5mA    -300mA     -100mA
2.7V      -180mA     -440mA     -110mA
2.8V      -320mA     -600mA     -170mA
2.9V      -480mA     -760mA     -290mA
3.1V      -810mA     -1.09A     -600mA
3.6V      -1.67A     -1.93A     -1.46A
[GND_clamp]
| voltage   I(typ)   I(min)   I(max)
-1.8V     -1.65A     -1.74A     -1.6A
-1.2V     -620mA     -740mA     -570mA
-1.1V     -450mA     -580mA     -410mA
-1V       -290mA     -420mA     -250mA
-900mV    -150mA     -270mA     -110mA
-800mV    -39.2mA    -140mA     -23mA
-700mV    -5.61mA    -40.17mA   -4.8mA
-600mV    -750uA     -5.57mA    -620uA
-500mV    -57.3uA    -660uA     -36.33uA
1.8V      30.92pA    98.88nA    20.22pA
[POWER_clamp]
| voltage   I(typ)   I(min)   I(max)
-1.8V     1.73A      1.82A      1.67A
-1.7V     1.57A      1.66A      1.51A
-1.4V     1.08A      1.21A      1.02A
-1.3V     930mA      1.05A      870mA
-1.1V     610mA      760mA      550mA
-900mV    310mA      460mA      250mA
-800mV    170mA      320mA      120mA
-700mV    53.56mA    190mA      24.17mA
-600mV    5.5mA      79.88mA    3.5mA
-500mV    490uA      13.45mA    470uA
-400mV    34.21uA    820uA      28.36uA
0V        30.92pA    1.07nA     28.99pA
[Ramp]
| variable   typ   min   max
dV/dt_r   0.71/0.43n   0.60/0.66n   0.83/0.31n
dV/dt_f   0.81/0.46n   0.68/0.73n   0.88/0.34n
R_load = 25.00
[Rising Waveform]
R_fixture = 25.00
V_fixture = 0.000
| time   V(typ)   V(min)   V(max)
0s        0V         0V         0V
900ps     -29.86mV   -8.08mV    5.3mV
1ns       -27.54mV   -13.9mV    140mV
1.2ns     34.85mV    -24.91mV   640mV
1.4ns     320mV      -15.51mV   1.17V
1.7ns     810mV      64.77mV    1.35V
1.9ns     1.04V      220mV      1.37V
2.1ns     1.14V      450mV      1.38V
2.8ns     1.19V      910mV      1.38V
5ns       1.19V      1V         1.38V
[Rising Waveform]
R_fixture = 25.00
V_fixture = 0.90
V_fixture_min = 0.79
V_fixture_max = 1.01
| time   V(typ)   V(min)   V(max)
0s        220mV      240mV      220mV
600ps     210mV      240mV      240mV
800ps     300mV      240mV      630mV
1ns       660mV      270mV      970mV
1.2ns     840mV      480mV      1.39V
1.4ns     1.1V       690mV      1.63V
1.8ns     1.47V      870mV      1.67V
2.2ns     1.52V      1.21V      1.68V
2.7ns     1.53V      1.35V      1.68V
5ns       1.53V      1.38V      1.68V
[Falling Waveform]
R_fixture = 25.00
V_fixture = 0.000
| time   V(typ)   V(min)   V(max)
0s        1.19V      1V         1.38V
500ps     1.19V      1V         1.36V
600ps     1.19V      1V         1.24V
700ps     1.15V      1V         1V
800ps     1V         1V         580mV
900ps     740mV      980mV      240mV
1.1ns     200mV      760mV      16.16mV
1.4ns     8.65mV     170mV      3.3mV
1.7ns     3.19mV     19.83mV    1.92mV
5ns       27.91uV    110uV      8.75uV
[Falling Waveform]
R_fixture = 25.00
V_fixture = 0.90
V_fixture_min = 0.79
V_fixture_max = 1.01
| time   V(typ)   V(min)   V(max)
0s        1.53V      1.38V      1.68V
600ps     1.53V      1.38V      1.65V
700ps     1.53V      1.38V      1.56V
800ps     1.48V      1.38V      1.31V
900ps     1.36V      1.38V      990mV
1.1ns     930mV      1.3V       450mV
1.4ns     380mV      860mV      260mV
1.8ns     260mV      460mV      240mV
2.2ns     240mV      320mV      230mV
5ns       220mV      240mV      220mV
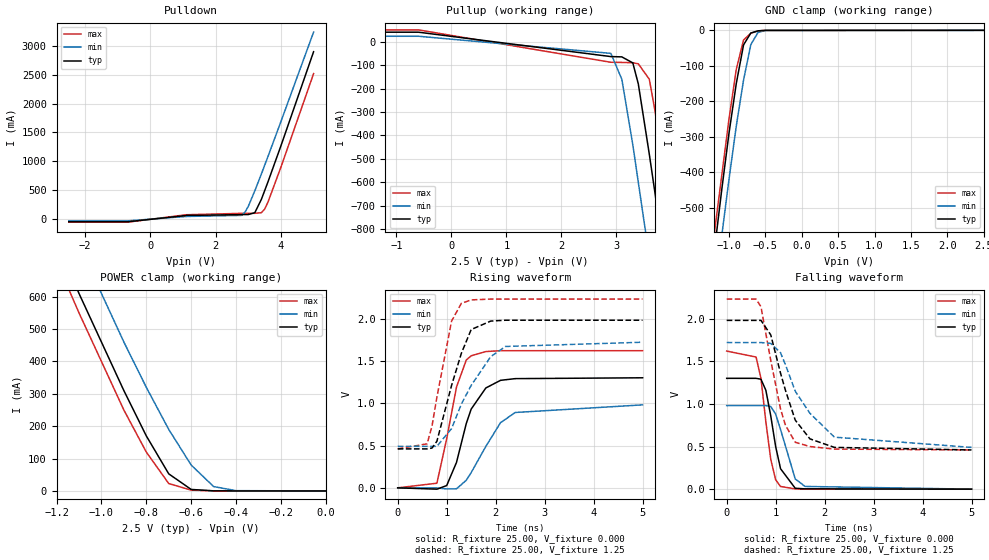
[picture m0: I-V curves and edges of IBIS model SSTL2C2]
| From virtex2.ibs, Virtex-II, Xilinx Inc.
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|   Model SSTL2C2
[Model]   SSTL2C2
Model_type   I/O
Polarity   Non-Inverting
Enable   Active-Low
Vinh = 1.43V
Vinl = 1.07V
Vmeas =   1.25V
Cref =  0pF
Rref =  25.00
Vref =   1.25V
C_comp   10.00pF   10.00pF   10.00pF
[Temperature Range]   25.00   100.00   0.000
[Voltage Range]   2.50V   2.30V   2.70V
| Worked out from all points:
|   slope of the pulldown table from 0 to 0.375 V, typ, clamps not added: 14.1 ohm
|   slope of the pullup table from 0 to 0.375 V, typ, clamps not added: 16.9 ohm
|   GND clamp passes 1 mA (typ) near -0.57 V on its own axis
|   POWER clamp passes 1 mA (typ) near -0.52 V on its own axis
|   rising waveform, R_fixture 25.00, V_fixture 0.000: 20-80 % time 446ps typ, 603ps min, 336ps max; typ from 0 V to 1.3 V
|   rising waveform, R_fixture 25.00, V_fixture 1.25: 20-80 % time 455ps typ, 673ps min, 338ps max; typ from 0.46 V to 1.98 V
|   falling waveform, R_fixture 25.00, V_fixture 0.000: 20-80 % time 252ps typ, 299ps min, 210ps max; typ from 1.3 V to 0 V
|   falling waveform, R_fixture 25.00, V_fixture 1.25: 20-80 % time 484ps typ, 738ps min, 372ps max; typ from 1.98 V to 0.46 V
[Pulldown]
| voltage   I(typ)   I(min)   I(max)
-2.5V     -48mA      -32.31mA   -55mA
-700mV    -48mA      -32.31mA   -55mA
1.1V      61.04mA    44.25mA    74.2mA
2.8V      76.79mA    63.42mA    98.27mA
2.9V      76.93mA    120mA      98.42mA
3V        77.16mA    220mA      98.56mA
3.2V      110mA      490mA      98.9mA
3.4V      340mA      780mA      110mA
3.5V      490mA      930mA      170mA
3.6V      640mA      1.08A      290mA
4V        1.27A      1.69A      900mA
5V        2.9A       3.24A      2.52A
[Pullup]
| voltage   I(typ)   I(min)   I(max)
-2.5V     40.73mA    23.34mA    50.54mA
-600mV    40.73mA    23.34mA    50.54mA
2.9V      -63.41mA   -49.71mA   -87.72mA
3.1V      -64.71mA   -160mA     -88.43mA
3.3V      -90.38mA   -440mA     -89.78mA
3.4V      -180mA     -600mA     -94.42mA
3.6V      -480mA     -920mA     -160mA
3.7V      -640mA     -1.08A     -290mA
3.8V      -810mA     -1.25A     -440mA
4V        -1.15A     -1.59A     -770mA
4.2V      -1.49A     -1.93A     -1.11A
5V        -2.9A      -3.29A     -2.51A
[GND_clamp]
| voltage   I(typ)   I(min)   I(max)
-2.5V     -2.88A     -2.94A     -2.84A
-1.2V     -620mA     -740mA     -570mA
-1.1V     -450mA     -580mA     -410mA
-1V       -290mA     -420mA     -250mA
-900mV    -150mA     -270mA     -110mA
-800mV    -41mA      -140mA     -27.22mA
-700mV    -7.57mA    -40.19mA   -8.13mA
-600mV    -1.4mA     -5.59mA    -1.6mA
-500mV    -130uA     -660uA     -120uA
2.5V      49.34pA    2.1uA      32.91pA
[POWER_clamp]
| voltage   I(typ)   I(min)   I(max)
-2.5V     2.87A      2.91A      2.82A
-1.3V     930mA      1.05A      870mA
-1.2V     770mA      910mA      710mA
-1.1V     610mA      760mA      550mA
-900mV    310mA      460mA      250mA
-800mV    170mA      320mA      120mA
-700mV    52.75mA    190mA      22.81mA
-600mV    4.57mA     79.88mA    2.44mA
-500mV    270uA      13.45mA    250uA
-400mV    16.38uA    820uA      14.46uA
0V        49.34pA    1.47nA     44.79pA
[Ramp]
| variable   typ   min   max
dV/dt_r   0.78/0.44n   0.59/0.61n   0.97/0.33n
dV/dt_f   0.88/0.72n   0.68/1.06n   1.03/0.52n
R_load = 25.00
[Rising Waveform]
R_fixture = 25.00
V_fixture = 0.000
| time   V(typ)   V(min)   V(max)
0s        0V         0V         0V
800ps     -15.79mV   -2.14mV    54.42mV
1ns       26.86mV    -12.92mV   580mV
1.2ns     300mV      -11.68mV   1.19V
1.4ns     760mV      89.38mV    1.51V
1.5ns     930mV      180mV      1.56V
1.8ns     1.18V      490mV      1.61V
2.1ns     1.27V      770mV      1.62V
2.4ns     1.29V      890mV      1.62V
5ns       1.3V       980mV      1.62V
[Rising Waveform]
R_fixture = 25.00
V_fixture = 1.25
V_fixture_min = 1.11
V_fixture_max = 1.39
| time   V(typ)   V(min)   V(max)
0s        460mV      490mV      460mV
600ps     460mV      490mV      520mV
700ps     470mV      490mV      730mV
800ps     550mV      490mV      1.07V
1.1ns     1.21V      700mV      1.97V
1.3ns     1.59V      990mV      2.18V
1.5ns     1.87V      1.21V      2.22V
1.9ns     1.97V      1.55V      2.23V
2.2ns     1.98V      1.67V      2.23V
5ns       1.98V      1.72V      2.23V
[Falling Waveform]
R_fixture = 25.00
V_fixture = 0.000
| time   V(typ)   V(min)   V(max)
0s        1.3V       980mV      1.62V
600ps     1.3V       980mV      1.55V
700ps     1.29V      980mV      1.3V
800ps     1.16V      980mV      790mV
900ps     860mV      970mV      350mV
1ns       500mV      880mV      110mV
1.1ns     240mV      700mV      31.7mV
1.4ns     10.72mV    120mV      3.04mV
1.6ns     3.72mV     32.06mV    2.02mV
5ns       9.32uV     62.63uV    0V
[Falling Waveform]
R_fixture = 25.00
V_fixture = 1.25
V_fixture_min = 1.11
V_fixture_max = 1.39
| time   V(typ)   V(min)   V(max)
0s        1.98V      1.72V      2.23V
600ps     1.98V      1.72V      2.23V
700ps     1.98V      1.72V      2.14V
900ps     1.81V      1.71V      1.51V
1.1ns     1.36V      1.6V       940mV
1.2ns     1.16V      1.46V      750mV
1.4ns     810mV      1.15V      550mV
1.7ns     590mV      890mV      500mV
2.2ns     490mV      610mV      470mV
5ns       460mV      490mV      460mV
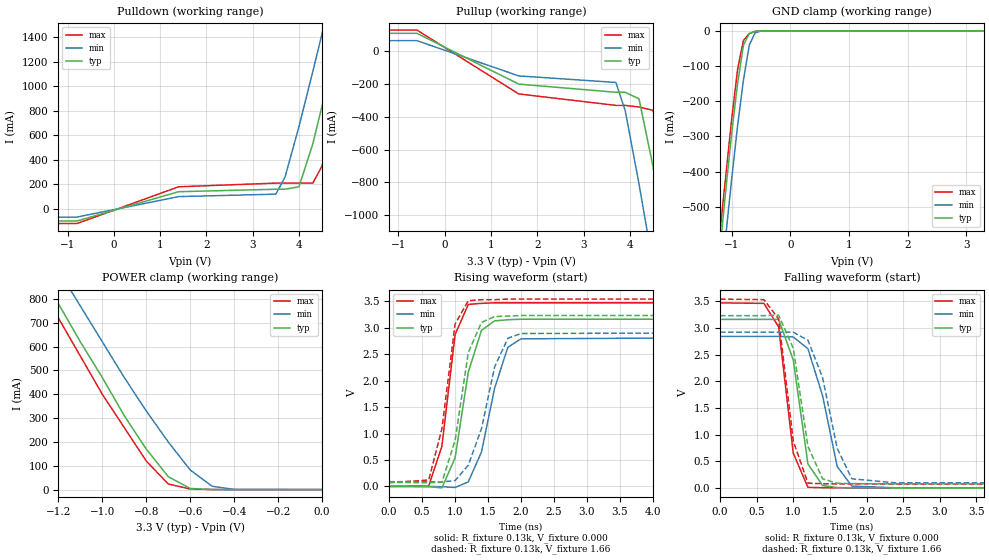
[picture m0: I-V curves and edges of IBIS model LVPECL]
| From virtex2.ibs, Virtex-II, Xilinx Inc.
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|   Model LVPECL
[Model]   LVPECL
Model_type   I/O
Polarity   Non-Inverting
Enable   Active-Low
Vinh = 1.49V
Vinl = 0.86V
Vmeas =   1.65V
Cref =  0pF
Rref =   1.00M
Vref =  0.000V
C_comp   10.00pF   10.00pF   10.00pF
[Temperature Range]   25.00   100.00   0.000
[Voltage Range]   3.30V   3.00V   3.60V
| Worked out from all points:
|   slope of the pulldown table from 0 to 0.495 V, typ, clamps not added: 7.13 ohm
|   slope of the pullup table from 0 to 0.495 V, typ, clamps not added: 6.12 ohm
|   GND clamp passes 1 mA (typ) near -0.57 V on its own axis
|   POWER clamp passes 1 mA (typ) near -0.52 V on its own axis
|   rising waveform, R_fixture 0.13k, V_fixture 0.000: 20-80 % time 282ps typ, 336ps min, 209ps max; typ from 0 V to 3.16 V
|   rising waveform, R_fixture 0.13k, V_fixture 1.66: 20-80 % time 266ps typ, 361ps min, 244ps max; typ from 0.075 V to 3.23 V
|   falling waveform, R_fixture 0.13k, V_fixture 0.000: 20-80 % time 215ps typ, 298ps min, 176ps max; typ from 3.16 V to 0 V
|   falling waveform, R_fixture 0.13k, V_fixture 1.66: 20-80 % time 222ps typ, 311ps min, 201ps max; typ from 3.23 V to 0.075 V
[Pulldown]
| voltage   I(typ)   I(min)   I(max)
-3.3V     -99.1mA    -67.11mA   -120mA
-800mV    -99.1mA    -67.11mA   -120mA
1.4V      140mA      100mA      180mA
3.5V      160mA      120mA      210mA
3.7V      160mA      260mA      210mA
4V        180mA      670mA      210mA
4.3V      530mA      1.12A      210mA
4.5V      840mA      1.43A      350mA
4.9V      1.49A      2.05A      960mA
5.1V      1.81A      2.37A      1.28A
5.3V      2.14A      2.68A      1.61A
6.6V      4.31A      4.74A      3.76A
[Pullup]
| voltage   I(typ)   I(min)   I(max)
-3.3V     110mA      65.31mA    130mA
-600mV    110mA      65.31mA    130mA
1.6V      -200mA     -150mA     -260mA
3.7V      -250mA     -190mA     -330mA
3.9V      -250mA     -360mA     -330mA
4.2V      -290mA     -810mA     -340mA
4.5V      -700mA     -1.3A      -360mA
4.7V      -1.04A     -1.63A     -540mA
4.9V      -1.38A     -1.97A     -850mA
5.1V      -1.73A     -2.31A     -1.19A
5.3V      -2.08A     -2.65A     -1.53A
6.6V      -4.38A     -4.89A     -3.83A
[GND_clamp]
| voltage   I(typ)   I(min)   I(max)
-3.3V     -4.3A      -4.31A     -4.26A
-1.2V     -620mA     -740mA     -570mA
-1.1V     -450mA     -580mA     -410mA
-1V       -290mA     -420mA     -250mA
-900mV    -150mA     -270mA     -110mA
-800mV    -41.03mA   -140mA     -27.28mA
-700mV    -7.6mA     -40.21mA   -8.18mA
-600mV    -1.42mA    -5.61mA    -1.62mA
-500mV    -130uA     -670uA     -130uA
3.3V      560pA      43.48uA    470pA
[POWER_clamp]
| voltage   I(typ)   I(min)   I(max)
-3.3V     4.25A      4.22A      4.2A
-1.3V     940mA      1.07A      880mA
-1.2V     780mA      920mA      720mA
-1.1V     620mA      770mA      560mA
-1V       470mA      620mA      400mA
-900mV    310mA      470mA      260mA
-800mV    170mA      330mA      120mA
-700mV    54.34mA    200mA      23.62mA
-600mV    4.76mA     82.21mA    2.52mA
-500mV    280uA      14.02mA    260uA
-400mV    16.91uA    860uA      14.85uA
0V        560pA      2.48nA     590pA
[Ramp]
| variable   typ   min   max
dV/dt_r   1.90/0.22n   1.71/0.29n   2.08/0.18n
dV/dt_f   1.89/0.21n   1.69/0.28n   2.07/0.16n
R_load = 0.13k
[Rising Waveform]
R_fixture = 0.13k
V_fixture = 0.000
| time   V(typ)   V(min)   V(max)
0s        0V         0V         0V
600ps     -6.99mV    21.1uV     10.23mV
800ps     -27.52mV   -5.28mV    760mV
1ns       540mV      -20.55mV   2.87V
1.2ns     2.16V      85.94mV    3.44V
1.4ns     2.95V      650mV      3.46V
1.6ns     3.13V      1.86V      3.47V
1.8ns     3.15V      2.63V      3.47V
2ns       3.16V      2.79V      3.47V
10ns      3.16V      2.84V      3.47V
[Rising Waveform]
R_fixture = 0.13k
V_fixture = 1.66
V_fixture_min = 1.51
V_fixture_max = 1.81
| time   V(typ)   V(min)   V(max)
0s        75.49mV    89.72mV    72.1mV
600ps     70.42mV    89.74mV    120mV
800ps     77.54mV    85.72mV    1.09V
1ns       870mV      110mV      3.07V
1.2ns     2.53V      400mV      3.51V
1.4ns     3.1V       1.09V      3.53V
1.6ns     3.21V      2.26V      3.53V
1.8ns     3.22V      2.8V       3.54V
2ns       3.23V      2.89V      3.54V
10ns      3.23V      2.92V      3.54V
[Falling Waveform]
R_fixture = 0.13k
V_fixture = 0.000
| time   V(typ)   V(min)   V(max)
0s        3.16V      2.84V      3.47V
600ps     3.16V      2.84V      3.46V
800ps     3.16V      2.84V      3.02V
1ns       2.4V       2.83V      650mV
1.2ns     450mV      2.61V      9.78mV
1.4ns     44.51mV    1.73V      3.34mV
1.6ns     4.88mV     400mV      1.18mV
1.8ns     1.75mV     33.07mV    420uV
2.4ns     140uV      1.15mV     21.23uV
10ns      1.74uV     790nV      -1.44uV
[Falling Waveform]
R_fixture = 0.13k
V_fixture = 1.66
V_fixture_min = 1.51
V_fixture_max = 1.81
| time   V(typ)   V(min)   V(max)
0s        3.23V      2.92V      3.54V
600ps     3.23V      2.92V      3.53V
800ps     3.24V      2.92V      3.17V
1ns       2.62V      2.92V      880mV
1.2ns     780mV      2.77V      88.64mV
1.4ns     170mV      2.07V      77.77mV
1.6ns     86.53mV    740mV      74.1mV
1.8ns     79.47mV    170mV      72.84mV
2.4ns     75.86mV    93.58mV    72.14mV
10ns      75.49mV    89.72mV    72.1mV
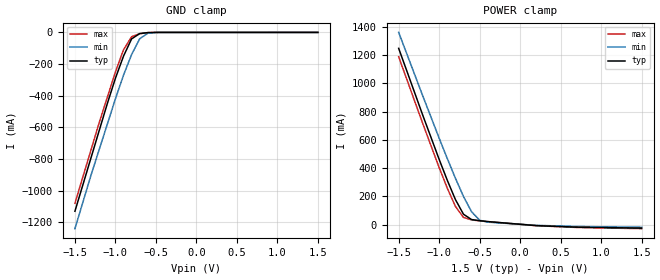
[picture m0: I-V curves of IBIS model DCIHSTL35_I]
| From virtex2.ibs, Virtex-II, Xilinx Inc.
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|   Model DCIHSTL35_I
[Model]   DCIHSTL35_I
Model_type   Input
Vinh = 1.0V
Vinl = 0.8V
Polarity   Non-Inverting
C_comp   10.00pF   10.00pF   10.00pF
[Temperature Range]   25.00   100.00   0.000
[Voltage Range]   1.50V   1.40V   1.60V
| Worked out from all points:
|   GND clamp passes 1 mA (typ) near -0.57 V on its own axis
|   POWER clamp passes 1 mA (typ) near -0.02 V on its own axis
[GND_clamp]
| voltage   I(typ)   I(min)   I(max)
-1.5V     -1.13A     -1.24A     -1.08A
-1.3V     -790mA     -900mA     -740mA
-1.2V     -620mA     -740mA     -570mA
-1.1V     -450mA     -580mA     -410mA
-1V       -290mA     -420mA     -250mA
-900mV    -150mA     -270mA     -110mA
-800mV    -40.96mA   -140mA     -27.15mA
-700mV    -7.52mA    -40.16mA   -8.06mA
-600mV    -1.38mA    -5.56mA    -1.57mA
-500mV    -120uA     -650uA     -120uA
1.5V      27.96pA    98.69nA    16.96pA
[POWER_clamp]
| voltage   I(typ)   I(min)   I(max)
-1.5V     1.248A     1.361A     1.188A
-1.2V     770.4mA    907.5mA    711mA
-1V       461.4mA    611.8mA    403mA
-900mV    313.9mA    467.9mA    257.7mA
-800mV    177.8mA    328.9mA    129.1mA
-700mV    72.97mA    199.1mA    50.22mA
-600mV    35.13mA    90.36mA    32.66mA
-500mV    26.86mA    30.52mA    25.83mA
-400mV    20.88mA    16.81mA    20.27mA
200mV     -7.873mA   -5.895mA   -8.244mA
700mV     -18.8mA    -13.98mA   -21.01mA
1.5V      -25.68mA   -19.49mA   -29.35mA
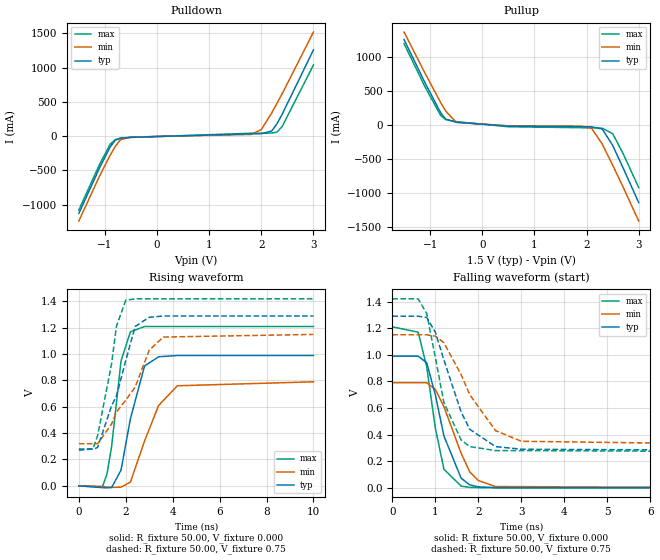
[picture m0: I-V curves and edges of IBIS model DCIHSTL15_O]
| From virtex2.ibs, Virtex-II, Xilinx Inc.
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|   Model DCIHSTL15_O
[Model]   DCIHSTL15_O
Model_type   Output
Polarity   Non-Inverting
Vmeas =   0.75V
Cref =  0pF
Rref =  50.00
Vref =   0.75V
C_comp   10.00pF   10.00pF   10.00pF
[Temperature Range]   25.00   100.00   0.000
[Voltage Range]   1.50V   1.40V   1.60V
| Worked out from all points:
|   slope of the pulldown table from 0 to 0.225 V, typ, clamps not added: 29.9 ohm
|   slope of the pullup table from 0 to 0.225 V, typ, clamps not added: 20.1 ohm
|   rising waveform, R_fixture 50.00, V_fixture 0.000: 20-80 % time 670ps typ, 942ps min, 477ps max; typ from 0 V to 0.99 V
|   rising waveform, R_fixture 50.00, V_fixture 0.75: 20-80 % time 1.06ns typ, 1.45ns min, 645ps max; typ from 0.28 V to 1.29 V
|   falling waveform, R_fixture 50.00, V_fixture 0.000: 20-80 % time 480ps typ, 580ps min, 379ps max; typ from 0.99 V to 0 V
|   falling waveform, R_fixture 50.00, V_fixture 0.75: 20-80 % time 657ps typ, 792ps min, 502ps max; typ from 1.29 V to 0.28 V
[Pulldown]
| voltage   I(typ)   I(min)   I(max)
-1.5V     -1.13A     -1.24A     -1.08A
-1.1V     -460mA     -580mA     -410mA
-900mV    -160mA     -280mA     -120mA
-800mV    -58.16mA   -150mA     -50.97mA
-700mV    -28.99mA   -51.77mA   -32.73mA
-500mV    -16.91mA   -13.5mA    -19.35mA
1.8V      32.93mA    24.13mA    42.08mA
2V        33.53mA    94.82mA    42.7mA
2.2V      75.06mA    340mA      44.78mA
2.3V      180mA      480mA      58.46mA
2.4V      320mA      620mA      140mA
3V        1.26A      1.52A      1.04A
[Pullup]
| voltage   I(typ)   I(min)   I(max)
-1.5V     1.25A      1.36A      1.19A
-1.1V     620mA      760mA      560mA
-800mV    180mA      330mA      140mA
-700mV    81.89mA    200mA      75.95mA
-500mV    37.18mA    37.14mA    47.08mA
500mV     -19.65mA   -14.37mA   -28.39mA
1.9V      -27.5mA    -20.38mA   -42.26mA
2.1V      -28.95mA   -55.13mA   -42.91mA
2.3V      -61.84mA   -280mA     -49.83mA
2.5V      -300mA     -590mA     -130mA
2.7V      -630mA     -910mA     -420mA
3V        -1.14A     -1.41A     -920mA
[Ramp]
| variable   typ   min   max
dV/dt_r   0.59/0.66n   0.47/0.92n   0.72/0.44n
dV/dt_f   0.54/0.69n   0.43/1.01n   0.61/0.52n
R_load = 50.00
[Rising Waveform]
R_fixture = 50.00
V_fixture = 0.000
| time   V(typ)   V(min)   V(max)
0s        0V         0V         0V
1ns       -13.8mV    -3.82mV    -10.26mV
1.2ns     -15.41mV   -9.83mV    88.66mV
1.4ns     -12.89mV   -12.17mV   300mV
1.8ns     120mV      -10.05mV   950mV
2.2ns     510mV      27.91mV    1.17V
2.8ns     910mV      340mV      1.21V
3.4ns     980mV      610mV      1.21V
4.2ns     990mV      760mV      1.21V
10ns      990mV      790mV      1.21V
[Rising Waveform]
R_fixture = 50.00
V_fixture = 0.75
V_fixture_min = 0.70
V_fixture_max = 0.80
| time   V(typ)   V(min)   V(max)
0s        280mV      320mV      270mV
600ps     280mV      320mV      280mV
800ps     290mV      320mV      380mV
1.4ns     610mV      470mV      930mV
1.6ns     680mV      560mV      1.21V
2ns       950mV      650mV      1.41V
2.4ns     1.21V      750mV      1.42V
3ns       1.28V      1.03V      1.42V
3.6ns     1.29V      1.13V      1.42V
10ns      1.29V      1.15V      1.42V
[Falling Waveform]
R_fixture = 50.00
V_fixture = 0.000
| time   V(typ)   V(min)   V(max)
0s        990mV      790mV      1.21V
600ps     990mV      790mV      1.17V
800ps     940mV      790mV      910mV
1ns       700mV      740mV      450mV
1.2ns     390mV      610mV      140mV
1.6ns     72.42mV    260mV      12.94mV
1.8ns     22.41mV    120mV      3.7mV
2ns       7.19mV     54.9mV     1.72mV
2.4ns     1.61mV     9.77mV     710uV
10ns      -1.45uV    -2.69uV    -550nV
[Falling Waveform]
R_fixture = 50.00
V_fixture = 0.75
V_fixture_min = 0.70
V_fixture_max = 0.80
| time   V(typ)   V(min)   V(max)
0s        1.29V      1.15V      1.42V
600ps     1.29V      1.15V      1.42V
800ps     1.28V      1.15V      1.31V
1ns       1.17V      1.14V      980mV
1.2ns     960mV      1.09V      640mV
1.6ns     570mV      850mV      360mV
1.8ns     440mV      700mV      310mV
2.4ns     310mV      430mV      280mV
3ns       290mV      350mV      280mV
10ns      280mV      320mV      270mV
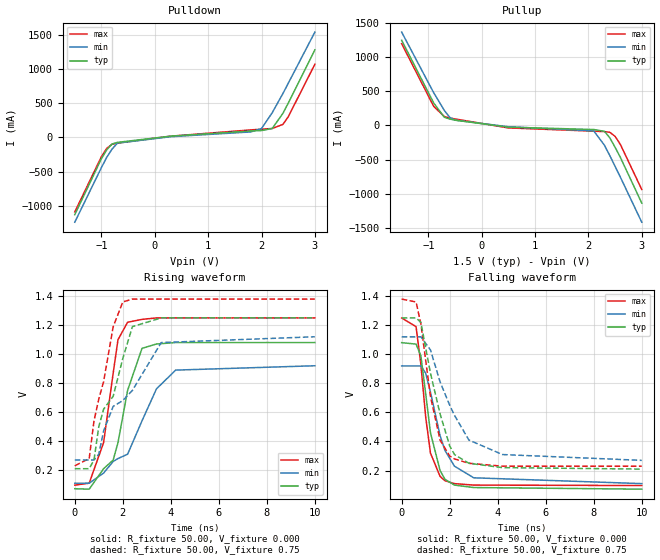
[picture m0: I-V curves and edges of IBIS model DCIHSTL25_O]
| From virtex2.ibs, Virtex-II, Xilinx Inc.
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|   Model DCIHSTL25_O
[Model]   DCIHSTL25_O
Model_type   Output
Polarity   Non-Inverting
Vmeas =   0.75V
Cref =  0pF
Rref =  50.00
Vref =   0.75V
C_comp   10.00pF   10.00pF   10.00pF
[Temperature Range]   25.00   100.00   0.000
[Voltage Range]   1.50V   1.40V   1.60V
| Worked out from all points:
|   slope of the pulldown table from 0 to 0.225 V, typ, clamps not added: 11 ohm
|   slope of the pullup table from 0 to 0.225 V, typ, clamps not added: 11.1 ohm
|   rising waveform, R_fixture 50.00, V_fixture 0.000: 20-80 % time 765ps typ, 1.67ns min, 655ps max; typ from 0.072 V to 1.08 V
|   rising waveform, R_fixture 50.00, V_fixture 0.75: 20-80 % time 1.17ns typ, 1.78ns min, 825ps max; typ from 0.21 V to 1.25 V
|   falling waveform, R_fixture 50.00, V_fixture 0.000: 20-80 % time 592ps typ, 822ps min, 463ps max; typ from 1.08 V to 0.072 V
|   falling waveform, R_fixture 50.00, V_fixture 0.75: 20-80 % time 865ps typ, 1.3ns min, 687ps max; typ from 1.25 V to 0.21 V
[Pulldown]
| voltage   I(typ)   I(min)   I(max)
-1.5V     -1.13A     -1.24A     -1.09A
-1V       -310mA     -440mA     -280mA
-900mV    -180mA     -290mA     -160mA
-800mV    -95.82mA   -170mA     -100mA
-700mV    -72.67mA   -83.99mA   -83.93mA
300mV     18.39mA    10.36mA    18.29mA
1.8V      94.12mA    79.91mA    110mA
2V        100mA      130mA      120mA
2.2V      130mA      360mA      130mA
2.4V      350mA      640mA      190mA
2.5V      500mA      790mA      300mA
3V        1.28A      1.54A      1.07A
[Pullup]
| voltage   I(typ)   I(min)   I(max)
-1.5V     1.25A      1.37A      1.2A
-900mV    330mA      480mA      280mA
-700mV    120mA      220mA      130mA
-600mV    93.98mA    120mA      110mA
-500mV    77.65mA    77.26mA    95.22mA
500mV     -25.46mA   -19.19mA   -36.42mA
2.1V      -59.79mA   -80.22mA   -84.14mA
2.3V      -86.18mA   -290mA     -90.45mA
2.4V      -180mA     -440mA     -100mA
2.5V      -320mA     -600mA     -160mA
2.6V      -470mA     -760mA     -280mA
3V        -1.14A     -1.42A     -940mA
[Ramp]
| variable   typ   min   max
dV/dt_r   0.60/0.75n   0.48/1.66n   0.69/0.56n
dV/dt_f   0.63/0.97n   0.50/1.68n   0.68/0.75n
R_load = 50.00
[Rising Waveform]
R_fixture = 50.00
V_fixture = 0.000
| time   V(typ)   V(min)   V(max)
0s        71.78mV    110mV      96.67mV
600ps     68.85mV    110mV      110mV
1.2ns     210mV      180mV      390mV
1.6ns     270mV      260mV      870mV
1.8ns     390mV      280mV      1.1V
2.2ns     750mV      310mV      1.22V
2.8ns     1.04V      540mV      1.24V
3.4ns     1.07V      760mV      1.25V
4.2ns     1.08V      890mV      1.25V
10ns      1.08V      920mV      1.25V
[Rising Waveform]
R_fixture = 50.00
V_fixture = 0.75
V_fixture_min = 0.70
V_fixture_max = 0.80
| time   V(typ)   V(min)   V(max)
0s        210mV      270mV      230mV
600ps     210mV      270mV      280mV
800ps     270mV      270mV      540mV
1ns       500mV      310mV      690mV
1.2ns     620mV      470mV      810mV
1.6ns     710mV      640mV      1.19V
2ns       970mV      680mV      1.36V
2.4ns     1.19V      750mV      1.38V
3.6ns     1.25V      1.08V      1.38V
10ns      1.25V      1.12V      1.38V
[Falling Waveform]
R_fixture = 50.00
V_fixture = 0.000
| time   V(typ)   V(min)   V(max)
0s        1.08V      920mV      1.25V
600ps     1.07V      920mV      1.19V
800ps     990mV      920mV      930mV
1ns       730mV      870mV      570mV
1.2ns     460mV      740mV      320mV
1.6ns     200mV      440mV      160mV
1.8ns     140mV      340mV      130mV
2.2ns     100mV      230mV      110mV
3ns       82.91mV    150mV      100mV
10ns      71.84mV    110mV      96.69mV
[Falling Waveform]
R_fixture = 50.00
V_fixture = 0.75
V_fixture_min = 0.70
V_fixture_max = 0.80
| time   V(typ)   V(min)   V(max)
0s        1.25V      1.12V      1.38V
600ps     1.25V      1.12V      1.36V
800ps     1.22V      1.12V      1.21V
1.2ns     870mV      1.03V      710mV
1.6ns     590mV      810mV      410mV
2ns       370mV      650mV      300mV
2.2ns     310mV      580mV      280mV
2.8ns     250mV      410mV      250mV
4.2ns     220mV      310mV      230mV
10ns      210mV      270mV      230mV
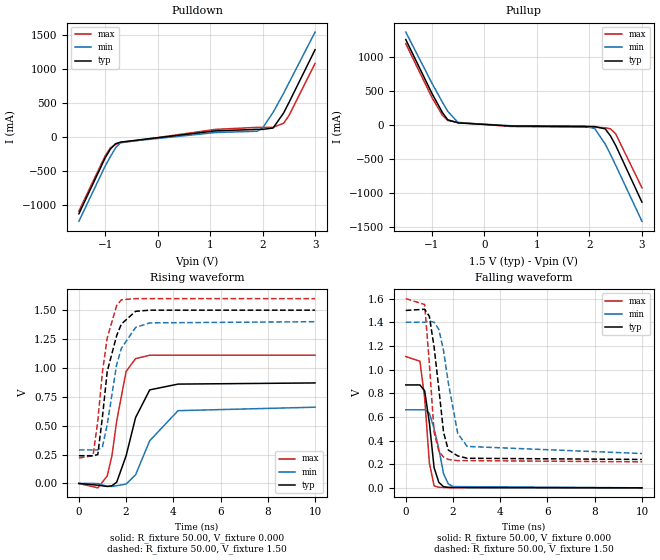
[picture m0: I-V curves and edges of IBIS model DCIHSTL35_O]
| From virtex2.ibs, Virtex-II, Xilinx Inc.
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|   Model DCIHSTL35_O
[Model]   DCIHSTL35_O
Model_type   Output
Polarity   Non-Inverting
Vmeas =   0.90V
Cref =  0pF
Rref =  50.00
Vref =   1.50V
C_comp   10.00pF   10.00pF   10.00pF
[Temperature Range]   25.00   100.00   0.000
[Voltage Range]   1.50V   1.40V   1.60V
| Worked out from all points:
|   slope of the pulldown table from 0 to 0.225 V, typ, clamps not added: 9.45 ohm
|   slope of the pullup table from 0 to 0.225 V, typ, clamps not added: 25.4 ohm
|   rising waveform, R_fixture 50.00, V_fixture 0.000: 20-80 % time 728ps typ, 960ps min, 524ps max; typ from 0 V to 0.87 V
|   rising waveform, R_fixture 50.00, V_fixture 1.50: 20-80 % time 608ps typ, 616ps min, 509ps max; typ from 0.24 V to 1.5 V
|   falling waveform, R_fixture 50.00, V_fixture 0.000: 20-80 % time 306ps typ, 432ps min, 278ps max; typ from 0.87 V to 0 V
|   falling waveform, R_fixture 50.00, V_fixture 1.50: 20-80 % time 433ps typ, 559ps min, 301ps max; typ from 1.5 V to 0.24 V
[Pulldown]
| voltage   I(typ)   I(min)   I(max)
-1.5V     -1.13A     -1.24A     -1.09A
-1V       -310mA     -430mA     -280mA
-900mV    -180mA     -290mA     -160mA
-800mV    -100mA     -160mA     -110mA
-700mV    -76.34mA   -79.31mA   -86.72mA
1.1V      87.62mA    63.65mA    110mA
1.9V      110mA      83.13mA    140mA
2V        110mA      130mA      140mA
2.2V      130mA      360mA      140mA
2.4V      350mA      640mA      200mA
2.5V      500mA      790mA      310mA
3V        1.28A      1.54A      1.08A
[Pullup]
| voltage   I(typ)   I(min)   I(max)
-1.5V     1.25A      1.36A      1.19A
-1V       460mA      610mA      400mA
-800mV    180mA      330mA      140mA
-700mV    75.36mA    200mA      64.35mA
-500mV    29.65mA    32.15mA    37.6mA
500mV     -15.56mA   -11.38mA   -22.51mA
1.9V      -21.75mA   -16.25mA   -33.42mA
2.1V      -23.18mA   -51.96mA   -33.96mA
2.3V      -57.37mA   -280mA     -41.07mA
2.4V      -160mA     -430mA     -56.91mA
2.5V      -300mA     -590mA     -130mA
3V        -1.13A     -1.41A     -920mA
[Ramp]
| variable   typ   min   max
dV/dt_r   0.52/0.71n   0.40/0.95n   0.67/0.50n
dV/dt_f   0.76/0.36n   0.67/0.55n   0.83/0.28n
R_load = 50.00
[Rising Waveform]
R_fixture = 50.00
V_fixture = 0.000
| time   V(typ)   V(min)   V(max)
0s        0V         0V         0V
800ps     -15.21mV   -750uV     -37.97mV
1.2ns     -25.88mV   -25.04mV   64.91mV
1.4ns     -20.1mV    -26.06mV   240mV
1.6ns     10.46mV    -19.7mV    540mV
2ns       240mV      -5.18mV    970mV
2.4ns     570mV      74.49mV    1.08V
3ns       810mV      370mV      1.11V
4.2ns     860mV      630mV      1.11V
10ns      870mV      660mV      1.11V
[Rising Waveform]
R_fixture = 50.00
V_fixture = 1.50
V_fixture_min = 1.40
V_fixture_max = 1.60
| time   V(typ)   V(min)   V(max)
0s        240mV      290mV      220mV
600ps     240mV      290mV      240mV
800ps     250mV      290mV      540mV
1ns       580mV      320mV      970mV
1.2ns     970mV      510mV      1.26V
1.6ns     1.28V      1.03V      1.54V
1.8ns     1.38V      1.17V      1.59V
2.4ns     1.49V      1.35V      1.6V
3ns       1.5V       1.39V      1.6V
10ns      1.5V       1.4V       1.6V
[Falling Waveform]
R_fixture = 50.00
V_fixture = 0.000
| time   V(typ)   V(min)   V(max)
0s        870mV      660mV      1.11V
600ps     870mV      660mV      1.07V
800ps     820mV      660mV      760mV
1ns       550mV      630mV      210mV
1.2ns     170mV      500mV      16.51mV
1.4ns     46.73mV    330mV      4.84mV
1.6ns     9.53mV     120mV      3.24mV
1.8ns     4.03mV     33.47mV    1.96mV
2ns       2.6mV      10.45mV    1.41mV
10ns      -600nV     0V         760nV
[Falling Waveform]
R_fixture = 50.00
V_fixture = 1.50
V_fixture_min = 1.40
V_fixture_max = 1.60
| time   V(typ)   V(min)   V(max)
0s        1.5V       1.4V       1.6V
800ps     1.51V      1.4V       1.55V
1ns       1.45V      1.41V      1.05V
1.2ns     1.19V      1.4V       470mV
1.4ns     840mV      1.34V      310mV
1.6ns     470mV      1.16V      260mV
1.8ns     320mV      890mV      240mV
2.2ns     270mV      460mV      230mV
2.6ns     250mV      350mV      230mV
10ns      240mV      290mV      220mV
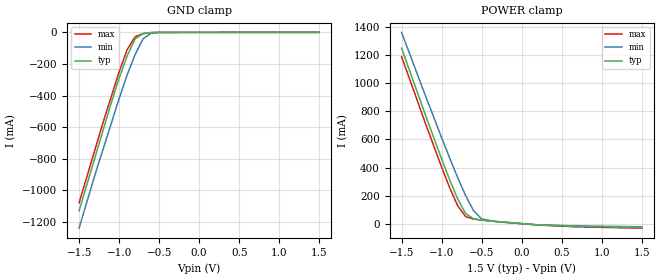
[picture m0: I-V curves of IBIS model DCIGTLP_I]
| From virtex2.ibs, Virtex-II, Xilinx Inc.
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|   Model DCIGTLP_I
[Model]   DCIGTLP_I
Model_type   Input
Vinh = 1.1V
Vinl = 0.9V
Polarity   Non-Inverting
C_comp   10.00pF   10.00pF   10.00pF
[Temperature Range]   25.00   100.00   0.000
[Voltage Range]   1.50V   1.35V   1.65V
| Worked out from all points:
|   GND clamp passes 1 mA (typ) near -0.57 V on its own axis
|   POWER clamp passes 1 mA (typ) near -0.02 V on its own axis
[GND_clamp]
| voltage   I(typ)   I(min)   I(max)
-1.5V     -1.13A     -1.24A     -1.08A
-1.3V     -790mA     -900mA     -740mA
-1.2V     -620mA     -740mA     -570mA
-1.1V     -450mA     -580mA     -410mA
-1V       -290mA     -420mA     -250mA
-900mV    -150mA     -270mA     -110mA
-800mV    -40.96mA   -140mA     -27.15mA
-700mV    -7.52mA    -40.16mA   -8.07mA
-600mV    -1.38mA    -5.56mA    -1.57mA
-500mV    -120uA     -650uA     -120uA
1.5V      27.96pA    460nA      15.61pA
[POWER_clamp]
| voltage   I(typ)   I(min)   I(max)
-1.5V     1.248A     1.361A     1.188A
-1.2V     770.4mA    907.7mA    711mA
-1V       461.4mA    612.1mA    403.1mA
-900mV    313.9mA    468.4mA    257.8mA
-800mV    177.8mA    329.7mA    129.4mA
-700mV    72.97mA    200.3mA    50.69mA
-600mV    35.13mA    92.72mA    33.15mA
-500mV    26.86mA    34.44mA    26.28mA
-300mV    15.22mA    14.3mA     15.23mA
200mV     -7.873mA   -6.898mA   -8.518mA
700mV     -18.8mA    -15.64mA   -22.09mA
1.5V      -25.68mA   -21.16mA   -30.83mA
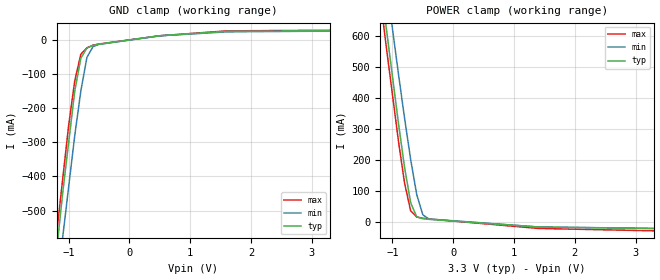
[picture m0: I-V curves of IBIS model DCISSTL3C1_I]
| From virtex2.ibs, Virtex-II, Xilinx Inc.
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|   Model DCISSTL3C1_I
[Model]   DCISSTL3C1_I
Model_type   Input
Vinh = 1.7V
Vinl = 1.3V
Polarity   Non-Inverting
C_comp   10.00pF   10.00pF   10.00pF
[Temperature Range]   25.00   100.00   0.000
[Voltage Range]   3.30V   3.00V   3.60V
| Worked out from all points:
|   GND clamp passes 1 mA (typ) near -0.04 V on its own axis
|   POWER clamp passes 1 mA (typ) near -0.06 V on its own axis
[GND_clamp]
| voltage   I(typ)   I(min)   I(max)
-3.3V     -4.3A      -4.31A     -4.26A
-1.2V     -620mA     -740mA     -570mA
-1.1V     -450mA     -580mA     -410mA
-1V       -300mA     -430mA     -250mA
-900mV    -150mA     -280mA     -120mA
-800mV    -54.01mA   -150mA     -42.4mA
-700mV    -24mA      -51.84mA   -23.98mA
-600mV    -16.42mA   -20.12mA   -15.99mA
-500mV    -12.98mA   -13.59mA   -12.47mA
500mV     11.71mA    11.39mA    11.59mA
1.6V      24.44mA    23.02mA    25.9mA
3.3V      26mA       25.18mA    27.78mA
[POWER_clamp]
| voltage   I(typ)   I(min)   I(max)
-3.3V     4.254A     4.222A     4.196A
-1.3V     941.8mA    1.075A     881.3mA
-1.2V     781.2mA    922.7mA    720.7mA
-1.1V     622.4mA    771.2mA    562.1mA
-900mV    315.6mA    475mA      258.2mA
-800mV    174.5mA    333.3mA    123.9mA
-700mV    60.87mA    200.2mA    34.54mA
-600mV    14.89mA    86.98mA    14.92mA
-500mV    9.292mA    21.84mA    10.85mA
-400mV    7.216mA    8.404mA    8.491mA
1.4V      -17.49mA   -17.44mA   -22.15mA
3.3V      -22.37mA   -21.94mA   -29.81mA
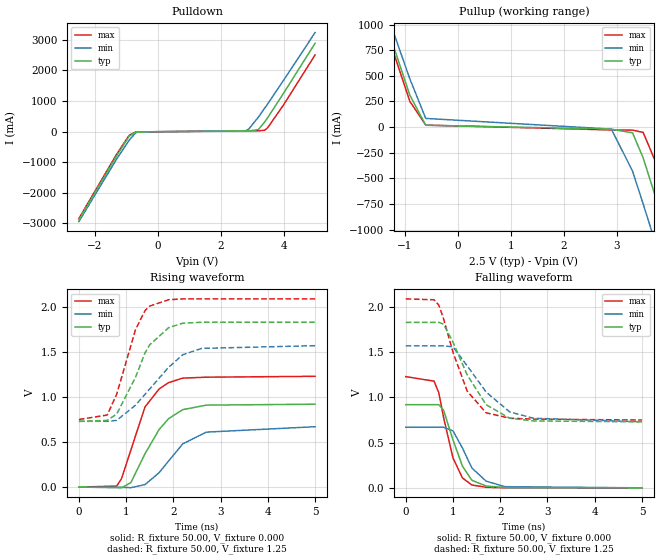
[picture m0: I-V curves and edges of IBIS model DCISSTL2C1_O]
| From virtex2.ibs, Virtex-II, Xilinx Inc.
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|   Model DCISSTL2C1_O
[Model]   DCISSTL2C1_O
Model_type   Output
Polarity   Non-Inverting
Vmeas =   1.25V
Cref =  0pF
Rref =  50.00
Vref =   1.25V
C_comp   10.00pF   10.00pF   10.00pF
[Temperature Range]   25.00   100.00   0.000
[Voltage Range]   2.50V   2.30V   2.70V
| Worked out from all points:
|   slope of the pulldown table from 0 to 0.375 V, typ, clamps not added: 62.4 ohm
|   slope of the pullup table from 0 to 0.375 V, typ, clamps not added: 51.8 ohm
|   rising waveform, R_fixture 50.00, V_fixture 0.000: 20-80 % time 606ps typ, 763ps min, 504ps max; typ from 0 V to 0.92 V
|   rising waveform, R_fixture 50.00, V_fixture 1.25: 20-80 % time 600ps typ, 864ps min, 469ps max; typ from 0.73 V to 1.83 V
|   falling waveform, R_fixture 50.00, V_fixture 0.000: 20-80 % time 380ps typ, 427ps min, 336ps max; typ from 0.92 V to 0 V
|   falling waveform, R_fixture 50.00, V_fixture 1.25: 20-80 % time 650ps typ, 813ps min, 522ps max; typ from 1.83 V to 0.73 V
[Pulldown]
| voltage   I(typ)   I(min)   I(max)
-2.5V     -2.88A     -2.94A     -2.84A
-1.3V     -790mA     -900mA     -740mA
-900mV    -150mA     -280mA     -120mA
-700mV    -18.33mA   -45.94mA   -20.52mA
-600mV    -11.26mA   -12.82mA   -12.87mA
2.8V      17.05mA    24.31mA    21.82mA
2.9V      17.1mA     87.6mA     21.85mA
3.2V      63.97mA    470mA      22.14mA
3.4V      310mA      760mA      40.63mA
3.5V      460mA      910mA      130mA
4V        1.25A      1.67A      870mA
5V        2.88A      3.23A      2.5A
[Pullup]
| voltage   I(typ)   I(min)   I(max)
-2.5V     2.87A      2.91A      2.82A
-1.5V     1.25A      1.36A      1.19A
-1.3V     930mA      1.06A      870mA
-900mV    310mA      470mA      250mA
-600mV    17.75mA    84.39mA    19mA
2.9V      -20.4mA    -19.7mA    -28.22mA
3.3V      -56.22mA   -430mA     -29.9mA
3.5V      -300mA     -750mA     -52.03mA
3.8V      -790mA     -1.24A     -420mA
4V        -1.13A     -1.58A     -750mA
4.2V      -1.48A     -1.92A     -1.09A
5V        -2.89A     -3.28A     -2.49A
[Ramp]
| variable   typ   min   max
dV/dt_r   0.55/0.61n   0.40/0.75n   0.74/0.52n
dV/dt_f   0.49/0.94n   0.35/1.16n   0.62/0.80n
R_load = 50.00
[Rising Waveform]
R_fixture = 50.00
V_fixture = 0.000
| time   V(typ)   V(min)   V(max)
0s        0V         0V         0V
800ps     -7.39mV    -1.54mV    10.39mV
900ps     -8.96mV    -3.11mV    89.52mV
1.1ns     48.63mV    -7.21mV    410mV
1.4ns     370mV      27.13mV    890mV
1.7ns     640mV      160mV      1.09V
1.9ns     760mV      290mV      1.16V
2.2ns     860mV      480mV      1.21V
2.7ns     910mV      610mV      1.22V
5ns       920mV      670mV      1.23V
[Rising Waveform]
R_fixture = 50.00
V_fixture = 1.25
V_fixture_min = 1.11
V_fixture_max = 1.39
| time   V(typ)   V(min)   V(max)
0s        730mV      730mV      750mV
600ps     740mV      730mV      800mV
800ps     810mV      740mV      1.03V
1.2ns     1.22V      910mV      1.75V
1.4ns     1.49V      1.03V      1.96V
1.5ns     1.58V      1.09V      2.01V
1.9ns     1.77V      1.33V      2.08V
2.2ns     1.82V      1.47V      2.09V
2.6ns     1.83V      1.54V      2.09V
5ns       1.83V      1.57V      2.09V
[Falling Waveform]
R_fixture = 50.00
V_fixture = 0.000
| time   V(typ)   V(min)   V(max)
0s        920mV      670mV      1.23V
600ps     920mV      670mV      1.18V
700ps     920mV      670mV      1.05V
800ps     860mV      670mV      780mV
1ns       530mV      630mV      330mV
1.2ns     240mV      440mV      110mV
1.4ns     83.63mV    220mV      31.23mV
1.7ns     20.5mV     74.09mV    6.38mV
2.1ns     2.65mV     13.04mV    730uV
5ns       -8.79uV    3.4uV      -9.26uV
[Falling Waveform]
R_fixture = 50.00
V_fixture = 1.25
V_fixture_min = 1.11
V_fixture_max = 1.39
| time   V(typ)   V(min)   V(max)
0s        1.83V      1.57V      2.09V
600ps     1.83V      1.57V      2.08V
700ps     1.83V      1.57V      2.02V
800ps     1.81V      1.57V      1.87V
1ns       1.61V      1.56V      1.5V
1.3ns     1.25V      1.35V      1.07V
1.7ns     920mV      1.06V      830mV
2.2ns     770mV      840mV      770mV
2.7ns     740mV      770mV      760mV
5ns       730mV      730mV      750mV
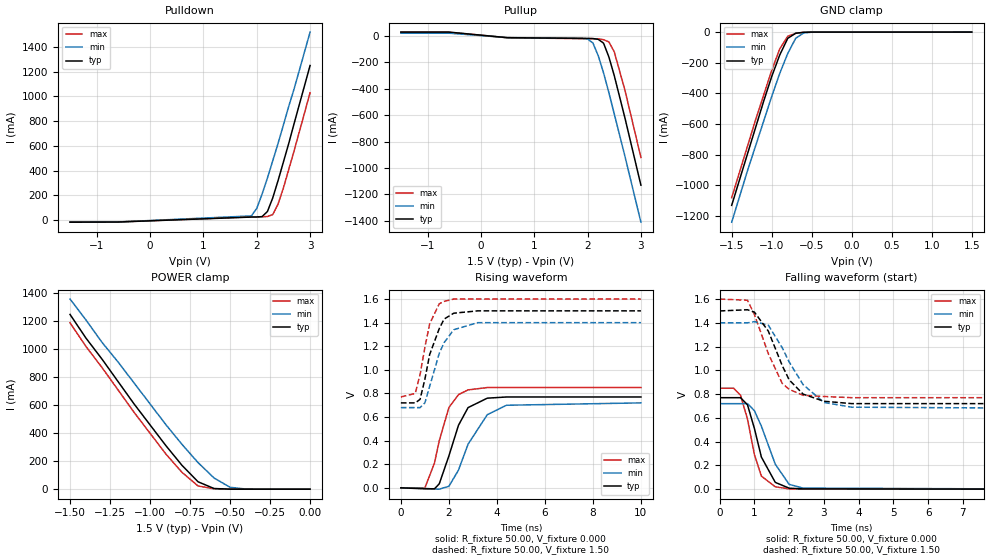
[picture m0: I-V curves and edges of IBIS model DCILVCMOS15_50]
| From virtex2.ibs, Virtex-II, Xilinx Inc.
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|   Model DCILVCMOS15_50
[Model]   DCILVCMOS15_50
Model_type   I/O
Polarity   Non-Inverting
Enable   Active-Low
Vinh = 1.05V
Vinl = 0.3V
Vmeas =   0.75V
Cref =  0pF
Rref =   1.00M
Vref =  0.000V
C_comp   10.00pF   10.00pF   10.00pF
[Temperature Range]   25.00   100.00   0.000
[Voltage Range]   1.50V   1.40V   1.60V
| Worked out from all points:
|   slope of the pulldown table from 0 to 0.225 V, typ, clamps not added: 39.1 ohm
|   slope of the pullup table from 0 to 0.225 V, typ, clamps not added: 29.7 ohm
|   GND clamp passes 1 mA (typ) near -0.57 V on its own axis
|   POWER clamp passes 1 mA (typ) near -0.52 V on its own axis
|   rising waveform, R_fixture 50.00, V_fixture 0.000: 20-80 % time 796ps typ, 1.04ns min, 661ps max; typ from 0 V to 0.77 V
|   rising waveform, R_fixture 50.00, V_fixture 1.50: 20-80 % time 641ps typ, 726ps min, 518ps max; typ from 0.72 V to 1.5 V
|   falling waveform, R_fixture 50.00, V_fixture 0.000: 20-80 % time 499ps typ, 585ps min, 423ps max; typ from 0.77 V to 0 V
|   falling waveform, R_fixture 50.00, V_fixture 1.50: 20-80 % time 738ps typ, 907ps min, 670ps max; typ from 1.5 V to 0.72 V
[Pulldown]
| voltage   I(typ)   I(min)   I(max)
-1.5V     -16.4mA    -14.51mA   -15.81mA
-600mV    -15.01mA   -14.51mA   -14.37mA
1.9V      25.12mA    34.44mA    26.86mA
2V        25.44mA    94.87mA    27.03mA
2.1V      28.77mA    210mA      27.33mA
2.2V      69.51mA    340mA      29.2mA
2.3V      180mA      480mA      45.06mA
2.4V      320mA      620mA      130mA
2.5V      470mA      770mA      260mA
2.6V      620mA      920mA      410mA
2.7V      780mA      1.06A      560mA
3V        1.25A      1.52A      1.03A
[Pullup]
| voltage   I(typ)   I(min)   I(max)
-1.5V     29.07mA    20.91mA    27.8mA
-600mV    29.07mA    20.91mA    27.8mA
500mV     -13.29mA   -12.71mA   -13.96mA
1.9V      -18.55mA   -18.09mA   -20.65mA
2V        -18.77mA   -22.46mA   -20.8mA
2.1V      -19.97mA   -53.36mA   -21.02mA
2.2V      -25.62mA   -150mA     -22.37mA
2.3V      -54.91mA   -280mA     -28.44mA
2.4V      -160mA     -430mA     -45.39mA
2.5V      -300mA     -590mA     -120mA
2.7V      -620mA     -910mA     -410mA
3V        -1.13A     -1.41A     -920mA
[GND_clamp]
| voltage   I(typ)   I(min)   I(max)
-1.5V     -1.13A     -1.24A     -1.08A
-1.3V     -790mA     -900mA     -740mA
-1.2V     -620mA     -740mA     -570mA
-1.1V     -450mA     -580mA     -410mA
-1V       -290mA     -420mA     -250mA
-900mV    -150mA     -270mA     -110mA
-800mV    -40.96mA   -140mA     -27.15mA
-700mV    -7.52mA    -40.16mA   -8.06mA
-600mV    -1.38mA    -5.56mA    -1.57mA
-500mV    -120uA     -650uA     -120uA
1.5V      27.96pA    98.69nA    16.96pA
[POWER_clamp]
| voltage   I(typ)   I(min)   I(max)
-1.5V     1.25A      1.36A      1.19A
-1.4V     1.08A      1.21A      1.02A
-1.3V     930mA      1.05A      870mA
-1.2V     770mA      910mA      710mA
-1.1V     610mA      760mA      550mA
-900mV    310mA      460mA      250mA
-800mV    170mA      320mA      120mA
-700mV    52.75mA    190mA      22.81mA
-600mV    4.57mA     79.88mA    2.44mA
-500mV    270uA      13.45mA    250uA
-400mV    16.38uA    820uA      14.46uA
0V        27.96pA    880pA      24.27pA
[Ramp]
| variable   typ   min   max
dV/dt_r   0.46/0.78n   0.43/1.01n   0.51/0.64n
dV/dt_f   0.47/0.72n   0.43/0.91n   0.50/0.61n
R_load = 50.00
[Rising Waveform]
R_fixture = 50.00
V_fixture = 0.000
| time   V(typ)   V(min)   V(max)
0s        0V         0V         0V
1ns       -8.48mV    -4.59mV    -780uV
1.4ns     -8.35mV    -10.38mV   210mV
1.6ns     34.03mV    -11.35mV   400mV
2ns       270mV      12.59mV    680mV
2.4ns     530mV      150mV      790mV
2.8ns     680mV      370mV      830mV
3.6ns     760mV      620mV      850mV
4.4ns     770mV      700mV      850mV
10ns      770mV      720mV      850mV
[Rising Waveform]
R_fixture = 50.00
V_fixture = 1.50
V_fixture_min = 1.40
V_fixture_max = 1.60
| time   V(typ)   V(min)   V(max)
0s        720mV      680mV      770mV
600ps     720mV      680mV      800mV
800ps     750mV      680mV      960mV
1ns       920mV      720mV      1.19V
1.2ns     1.13V      860mV      1.39V
1.6ns     1.35V      1.14V      1.56V
1.8ns     1.43V      1.23V      1.58V
2.2ns     1.48V      1.34V      1.6V
3.2ns     1.5V       1.4V       1.6V
10ns      1.5V       1.4V       1.6V
[Falling Waveform]
R_fixture = 50.00
V_fixture = 0.000
| time   V(typ)   V(min)   V(max)
0s        770mV      720mV      850mV
400ps     770mV      720mV      850mV
600ps     770mV      720mV      790mV
800ps     710mV      720mV      590mV
1ns       510mV      660mV      290mV
1.2ns     270mV      530mV      110mV
1.6ns     57.15mV    210mV      19.88mV
2ns       8.17mV     40.21mV    2.48mV
2.4ns     2.41mV     9.02mV     600uV
10ns      36.42uV    26.57uV    22.29uV
[Falling Waveform]
R_fixture = 50.00
V_fixture = 1.50
V_fixture_min = 1.40
V_fixture_max = 1.60
| time   V(typ)   V(min)   V(max)
0s        1.5V       1.4V       1.6V
800ps     1.51V      1.4V       1.59V
1ns       1.49V      1.41V      1.47V
1.4ns     1.33V      1.38V      1.14V
1.8ns     1.04V      1.19V      890mV
2ns       920mV      1.07V      840mV
2.4ns     800mV      880mV      790mV
3ns       740mV      730mV      780mV
3.8ns     720mV      690mV      770mV
10ns      720mV      680mV      770mV
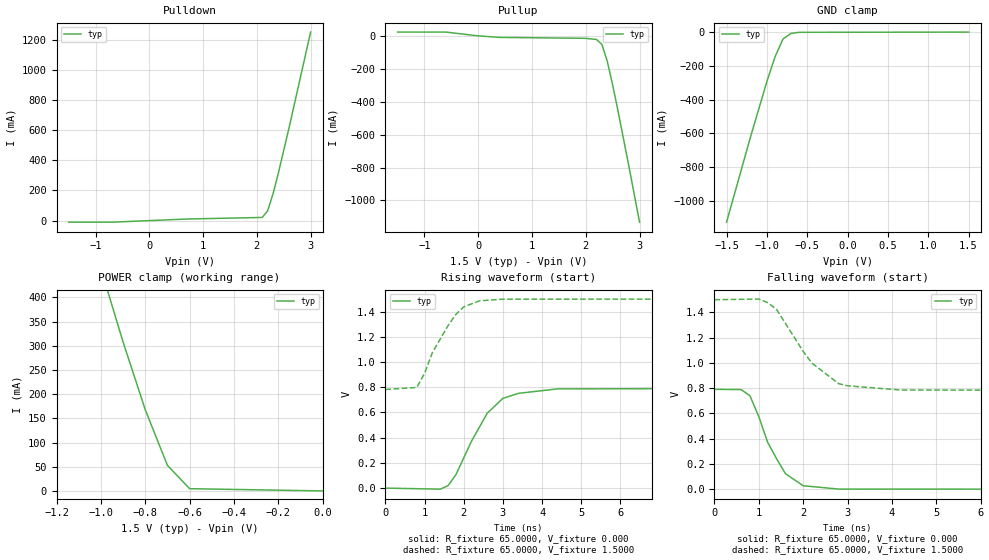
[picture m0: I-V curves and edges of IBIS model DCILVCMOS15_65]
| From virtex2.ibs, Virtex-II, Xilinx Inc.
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|   Model DCILVCMOS15_65
[Model]   DCILVCMOS15_65
Model_type   I/O
Polarity   Non-Inverting
Enable   Active-Low
Vinh = 1.05V
Vinl = 0.3V
Vmeas =   0.75V
Cref =  0pF
Rref =   1.00M
Vref =  0.000V
C_comp   7.0000pF   NA   NA
[Temperature Range]   25.0000   NA   NA
[Voltage Range]   1.5000V   NA   NA
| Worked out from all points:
|   slope of the pulldown table from 0 to 0.225 V, typ, clamps not added: 58.8 ohm
|   slope of the pullup table from 0 to 0.225 V, typ, clamps not added: 37.5 ohm
|   GND clamp passes 1 mA (typ) near -0.57 V on its own axis
|   POWER clamp passes 1 mA (typ) near -0.52 V on its own axis
|   rising waveform, R_fixture 65.0000, V_fixture 0.000: 20-80 % time 819ps typ, NA min, NA max; typ from 0 V to 0.79 V
|   rising waveform, R_fixture 65.0000, V_fixture 1.5000: 20-80 % time 732ps typ, NA min, NA max; typ from 0.782 V to 1.5 V
|   falling waveform, R_fixture 65.0000, V_fixture 0.000: 20-80 % time 611ps typ, NA min, NA max; typ from 0.79 V to 0 V
|   falling waveform, R_fixture 65.0000, V_fixture 1.5000: 20-80 % time 911ps typ, NA min, NA max; typ from 1.5 V to 0.782 V
[Pulldown]
| voltage   I(typ)   I(min)   I(max)
-1.5V     -10.89mA   NA         NA
-700mV    -10.89mA   NA         NA
700mV     10.17mA    NA         NA
2.1V      20.64mA    NA         NA
2.2V      63.82mA    NA         NA
2.3V      175.9mA    NA         NA
2.4V      314.8mA    NA         NA
2.6V      617.3mA    NA         NA
3V        1.252A     NA         NA
[Pullup]
| voltage   I(typ)   I(min)   I(max)
-1.5V     22.99mA    NA         NA
-600mV    22.99mA    NA         NA
0V        -4.6nA     NA         NA
400mV     -9.254mA   NA         NA
2V        -14.9mA    NA         NA
2.2V      -21.92mA   NA         NA
2.3V      -52.01mA   NA         NA
2.4V      -155.2mA   NA         NA
2.5V      -299.2mA   NA         NA
2.6V      -457.5mA   NA         NA
2.8V      -790.2mA   NA         NA
3V        -1.132A    NA         NA
[GND_clamp]
| voltage   I(typ)   I(min)   I(max)
-1.5V     -1.127A    NA         NA
-1.2V     -617mA     NA         NA
-1V       -293.4mA   NA         NA
-900mV    -148mA     NA         NA
-800mV    -41mA      NA         NA
-700mV    -7.588mA   NA         NA
-600mV    -1.413mA   NA         NA
1.5V      218.4nA    NA         NA
[POWER_clamp]
| voltage   I(typ)   I(min)   I(max)
-1.5V     1.246A     NA         NA
-1.1V     610.9mA    NA         NA
-900mV    307.7mA    NA         NA
-800mV    167.8mA    NA         NA
-700mV    52.78mA    NA         NA
-600mV    4.607mA    NA         NA
0V        218.4nA    NA         NA
[Ramp]
| variable   typ   min   max
dV/dt_r   0.4743/0.8211n   NA   NA
dV/dt_f   0.4305/0.9045n   NA   NA
R_load = 65.0000
[Rising Waveform]
R_fixture = 65.0000
V_fixture = 0.000
| time   V(typ)   V(min)   V(max)
0s        10.73uV    NA         NA
1.4ns     -8.408mV   NA         NA
1.6ns     20.23mV    NA         NA
1.8ns     106.7mV    NA         NA
2.2ns     373.9mV    NA         NA
2.6ns     594.6mV    NA         NA
3ns       712.4mV    NA         NA
3.4ns     752.2mV    NA         NA
4.4ns     787.3mV    NA         NA
10ns      790.5mV    NA         NA
[Rising Waveform]
R_fixture = 65.0000
V_fixture = 1.5000
V_fixture_min = 1.4000
V_fixture_max = 1.6000
| time   V(typ)   V(min)   V(max)
0s        782.5mV    NA         NA
800ps     798.9mV    NA         NA
1ns       911.4mV    NA         NA
1.2ns     1.077V     NA         NA
1.6ns     1.29V      NA         NA
1.8ns     1.379V     NA         NA
2ns       1.438V     NA         NA
2.4ns     1.486V     NA         NA
3ns       1.499V     NA         NA
10ns      1.5V       NA         NA
[Falling Waveform]
R_fixture = 65.0000
V_fixture = 0.000
| time   V(typ)   V(min)   V(max)
0s        790.5mV    NA         NA
600ps     788.2mV    NA         NA
800ps     739.8mV    NA         NA
1ns       573.8mV    NA         NA
1.2ns     371.1mV    NA         NA
1.4ns     241.4mV    NA         NA
1.6ns     122.7mV    NA         NA
2ns       27.27mV    NA         NA
2.8ns     594.3uV    NA         NA
10ns      -6.526uV   NA         NA
[Falling Waveform]
R_fixture = 65.0000
V_fixture = 1.5000
V_fixture_min = 1.4000
V_fixture_max = 1.6000
| time   V(typ)   V(min)   V(max)
0s        1.5V       NA         NA
1ns       1.505V     NA         NA
1.2ns     1.477V     NA         NA
1.4ns     1.423V     NA         NA
2ns       1.091V     NA         NA
2.2ns     997.3mV    NA         NA
2.8ns     835.1mV    NA         NA
3ns       818.2mV    NA         NA
4.2ns     785mV      NA         NA
10ns      782.5mV    NA         NA
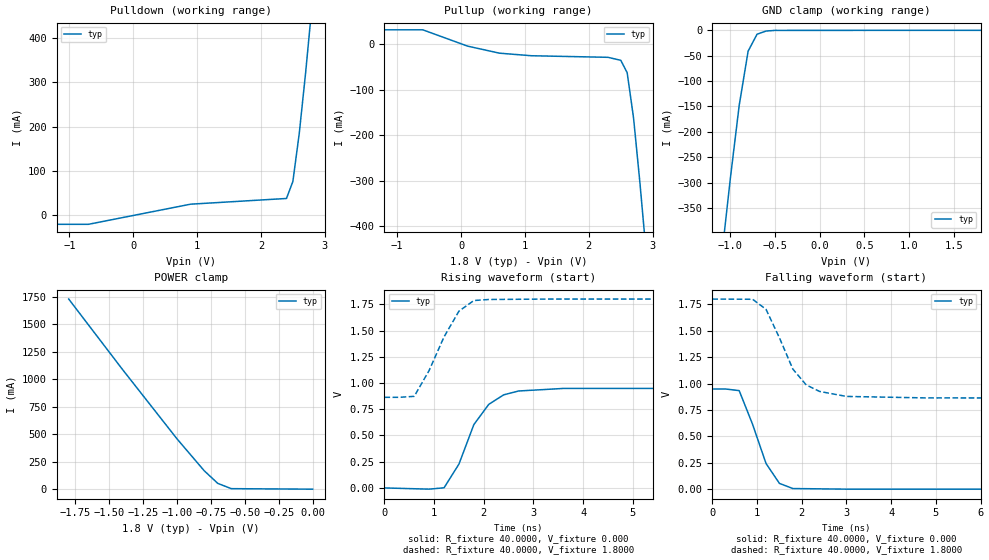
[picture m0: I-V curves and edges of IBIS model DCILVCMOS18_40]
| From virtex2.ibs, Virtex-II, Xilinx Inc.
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|   Model DCILVCMOS18_40
[Model]   DCILVCMOS18_40
Model_type   I/O
Polarity   Non-Inverting
Enable   Active-Low
Vinh = 1.19V
Vinl = 0.4V
Vmeas = 0.9V
Cref =  0pF
Rref =  1.0000M
Vref =  0.000V
C_comp   7.0000pF   NA   NA
[Temperature Range]   25.0000   NA   NA
[Voltage Range]   1.8000V   NA   NA
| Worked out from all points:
|   slope of the pulldown table from 0 to 0.27 V, typ, clamps not added: 30.2 ohm
|   slope of the pullup table from 0 to 0.27 V, typ, clamps not added: 24.6 ohm
|   GND clamp passes 1 mA (typ) near -0.57 V on its own axis
|   POWER clamp passes 1 mA (typ) near -0.52 V on its own axis
|   rising waveform, R_fixture 40.0000, V_fixture 0.000: 20-80 % time 591ps typ, NA min, NA max; typ from 0 V to 0.948 V
|   rising waveform, R_fixture 40.0000, V_fixture 1.8000: 20-80 % time 595ps typ, NA min, NA max; typ from 0.864 V to 1.8 V
|   falling waveform, R_fixture 40.0000, V_fixture 0.000: 20-80 % time 522ps typ, NA min, NA max; typ from 0.948 V to 0 V
|   falling waveform, R_fixture 40.0000, V_fixture 1.8000: 20-80 % time 671ps typ, NA min, NA max; typ from 1.8 V to 0.864 V
[Pulldown]
| voltage   I(typ)   I(min)   I(max)
-1.8V     -21.54mA   NA         NA
-700mV    -21.54mA   NA         NA
900mV     24.08mA    NA         NA
2.4V      36.97mA    NA         NA
2.5V      75.31mA    NA         NA
2.6V      184.1mA    NA         NA
2.7V      322.1mA    NA         NA
3V        780.2mA    NA         NA
3.6V      1.743A     NA         NA
[Pullup]
| voltage   I(typ)   I(min)   I(max)
-1.8V     31.33mA    NA         NA
-600mV    31.33mA    NA         NA
100mV     -4.464mA   NA         NA
600mV     -20.01mA   NA         NA
1.1V      -25.66mA   NA         NA
2.3V      -29.13mA   NA         NA
2.5V      -35.71mA   NA         NA
2.6V      -62.88mA   NA         NA
2.7V      -162.2mA   NA         NA
2.8V      -304.9mA   NA         NA
2.9V      -462.6mA   NA         NA
3.6V      -1.658A    NA         NA
[GND_clamp]
| voltage   I(typ)   I(min)   I(max)
-1.8V     -1.649A    NA         NA
-1.1V     -452.1mA   NA         NA
-1V       -293.4mA   NA         NA
-900mV    -148mA     NA         NA
-800mV    -41.01mA   NA         NA
-700mV    -7.602mA   NA         NA
-600mV    -1.419mA   NA         NA
-500mV    -128.9uA   NA         NA
1.8V      272.1nA    NA         NA
[POWER_clamp]
| voltage   I(typ)   I(min)   I(max)
-1.8V     1.731A     NA         NA
-1.4V     1.085A     NA         NA
-1V       456.9mA    NA         NA
-800mV    167.8mA    NA         NA
-700mV    52.78mA    NA         NA
-600mV    4.607mA    NA         NA
0V        272.1nA    NA         NA
[Ramp]
| variable   typ   min   max
dV/dt_r   0.5690/0.6206n   NA   NA
dV/dt_f   0.5618/0.7239n   NA   NA
R_load = 40.0000
[Rising Waveform]
R_fixture = 40.0000
V_fixture = 0.000
| time   V(typ)   V(min)   V(max)
0s        6.403uV    NA         NA
900ps     -11.78mV   NA         NA
1.2ns     1.417mV    NA         NA
1.5ns     227.4mV    NA         NA
1.8ns     604mV      NA         NA
2.1ns     796.6mV    NA         NA
2.4ns     887.3mV    NA         NA
2.7ns     923.8mV    NA         NA
3.6ns     948.2mV    NA         NA
15ns      948.3mV    NA         NA
[Rising Waveform]
R_fixture = 40.0000
V_fixture = 1.8000
V_fixture_min = 1.7000
V_fixture_max = 1.9000
| time   V(typ)   V(min)   V(max)
0s        863.6mV    NA         NA
300ps     863.6mV    NA         NA
600ps     873mV      NA         NA
900ps     1.12V      NA         NA
1.2ns     1.44V      NA         NA
1.5ns     1.685V     NA         NA
1.8ns     1.786V     NA         NA
2.1ns     1.796V     NA         NA
3.3ns     1.8V       NA         NA
15ns      1.8V       NA         NA
[Falling Waveform]
R_fixture = 40.0000
V_fixture = 0.000
| time   V(typ)   V(min)   V(max)
0s        948.4mV    NA         NA
300ps     948.3mV    NA         NA
600ps     933.1mV    NA         NA
900ps     613.5mV    NA         NA
1.2ns     243.4mV    NA         NA
1.5ns     54.75mV    NA         NA
1.8ns     5.899mV    NA         NA
3ns       222.7uV    NA         NA
15ns      -13.91uV   NA         NA
[Falling Waveform]
R_fixture = 40.0000
V_fixture = 1.8000
V_fixture_min = 1.7000
V_fixture_max = 1.9000
| time   V(typ)   V(min)   V(max)
0s        1.8V       NA         NA
900ps     1.798V     NA         NA
1.2ns     1.703V     NA         NA
1.5ns     1.433V     NA         NA
1.8ns     1.137V     NA         NA
2.1ns     986.6mV    NA         NA
2.4ns     925.1mV    NA         NA
3ns       878.1mV    NA         NA
4.8ns     863.9mV    NA         NA
15ns      863.6mV    NA         NA
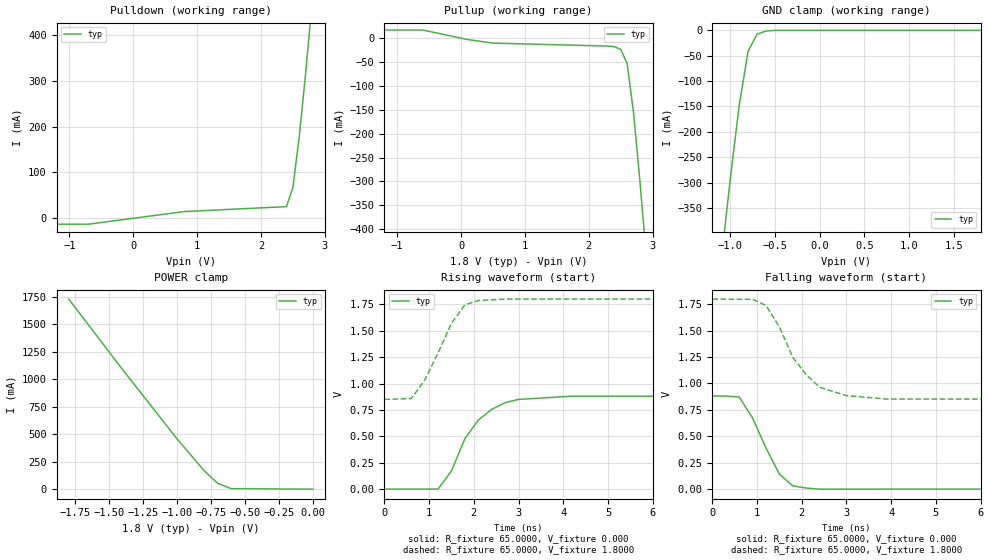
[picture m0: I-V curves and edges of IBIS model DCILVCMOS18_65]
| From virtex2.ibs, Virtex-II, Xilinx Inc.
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|   Model DCILVCMOS18_65
[Model]   DCILVCMOS18_65
Model_type   I/O
Polarity   Non-Inverting
Enable   Active-Low
Vinh = 1.19V
Vinl = 0.4V
Vmeas =   0.9V
Cref =  0pF
Rref =  1.0000M
Vref =  0.000V
C_comp   7.0000pF   NA   NA
[Temperature Range]   25.0000   NA   NA
[Voltage Range]   1.8000V   NA   NA
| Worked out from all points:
|   slope of the pulldown table from 0 to 0.27 V, typ, clamps not added: 47.8 ohm
|   slope of the pullup table from 0 to 0.27 V, typ, clamps not added: 44 ohm
|   GND clamp passes 1 mA (typ) near -0.57 V on its own axis
|   POWER clamp passes 1 mA (typ) near -0.52 V on its own axis
|   rising waveform, R_fixture 65.0000, V_fixture 0.000: 20-80 % time 747ps typ, NA min, NA max; typ from 0 V to 0.881 V
|   rising waveform, R_fixture 65.0000, V_fixture 1.8000: 20-80 % time 657ps typ, NA min, NA max; typ from 0.85 V to 1.8 V
|   falling waveform, R_fixture 65.0000, V_fixture 0.000: 20-80 % time 606ps typ, NA min, NA max; typ from 0.881 V to 0 V
|   falling waveform, R_fixture 65.0000, V_fixture 1.8000: 20-80 % time 818ps typ, NA min, NA max; typ from 1.8 V to 0.85 V
[Pulldown]
| voltage   I(typ)   I(min)   I(max)
-1.8V     -13.61mA   NA         NA
-700mV    -13.61mA   NA         NA
800mV     14.01mA    NA         NA
2.4V      24.86mA    NA         NA
2.5V      66.76mA    NA         NA
2.6V      178mA      NA         NA
2.7V      316.7mA    NA         NA
3V        775.5mA    NA         NA
3.6V      1.738A     NA         NA
[Pullup]
| voltage   I(typ)   I(min)   I(max)
-1.8V     17.46mA    NA         NA
-600mV    17.46mA    NA         NA
100mV     -2.499mA   NA         NA
500mV     -9.941mA   NA         NA
2.3V      -16.24mA   NA         NA
2.4V      -17.46mA   NA         NA
2.5V      -23.2mA    NA         NA
2.6V      -53.01mA   NA         NA
2.7V      -155.8mA   NA         NA
2.8V      -299.8mA   NA         NA
2.9V      -457.9mA   NA         NA
3.6V      -1.654A    NA         NA
[GND_clamp]
| voltage   I(typ)   I(min)   I(max)
-1.8V     -1.649A    NA         NA
-1.1V     -452.1mA   NA         NA
-1V       -293.4mA   NA         NA
-900mV    -148mA     NA         NA
-800mV    -41.01mA   NA         NA
-700mV    -7.602mA   NA         NA
-600mV    -1.419mA   NA         NA
-500mV    -128.9uA   NA         NA
1.8V      272.1nA    NA         NA
[POWER_clamp]
| voltage   I(typ)   I(min)   I(max)
-1.8V     1.731A     NA         NA
-1.4V     1.085A     NA         NA
-1V       456.9mA    NA         NA
-800mV    167.8mA    NA         NA
-700mV    52.78mA    NA         NA
-600mV    4.607mA    NA         NA
0V        272.1nA    NA         NA
[Ramp]
| variable   typ   min   max
dV/dt_r   0.5285/0.7909n   NA   NA
dV/dt_f   0.5699/0.8767n   NA   NA
R_load = 65.0000
[Rising Waveform]
R_fixture = 65.0000
V_fixture = 0.000
| time   V(typ)   V(min)   V(max)
0s        10.53uV    NA         NA
1.2ns     889.7uV    NA         NA
1.5ns     173.2mV    NA         NA
1.8ns     478.8mV    NA         NA
2.1ns     653.8mV    NA         NA
2.4ns     755.9mV    NA         NA
2.7ns     819.2mV    NA         NA
3ns       850.1mV    NA         NA
4.2ns     880.4mV    NA         NA
15ns      880.9mV    NA         NA
[Rising Waveform]
R_fixture = 65.0000
V_fixture = 1.8000
V_fixture_min = 1.7000
V_fixture_max = 1.9000
| time   V(typ)   V(min)   V(max)
0s        850.1mV    NA         NA
600ps     857.7mV    NA         NA
900ps     1.032V     NA         NA
1.2ns     1.29V      NA         NA
1.5ns     1.571V     NA         NA
1.8ns     1.746V     NA         NA
2.1ns     1.786V     NA         NA
2.7ns     1.8V       NA         NA
3ns       1.8V       NA         NA
15ns      1.8V       NA         NA
[Falling Waveform]
R_fixture = 65.0000
V_fixture = 0.000
| time   V(typ)   V(min)   V(max)
0s        880.9mV    NA         NA
300ps     880.9mV    NA         NA
600ps     871.8mV    NA         NA
900ps     672.2mV    NA         NA
1.2ns     388.4mV    NA         NA
1.5ns     140.5mV    NA         NA
1.8ns     29.17mV    NA         NA
2.1ns     9.371mV    NA         NA
2.4ns     -1.481mV   NA         NA
15ns      -7.201uV   NA         NA
[Falling Waveform]
R_fixture = 65.0000
V_fixture = 1.8000
V_fixture_min = 1.7000
V_fixture_max = 1.9000
| time   V(typ)   V(min)   V(max)
0s        1.8V       NA         NA
900ps     1.798V     NA         NA
1.2ns     1.739V     NA         NA
1.5ns     1.535V     NA         NA
1.8ns     1.248V     NA         NA
2.1ns     1.083V     NA         NA
2.4ns     964mV      NA         NA
3ns       884.7mV    NA         NA
3.9ns     852.8mV    NA         NA
15ns      850.1mV    NA         NA
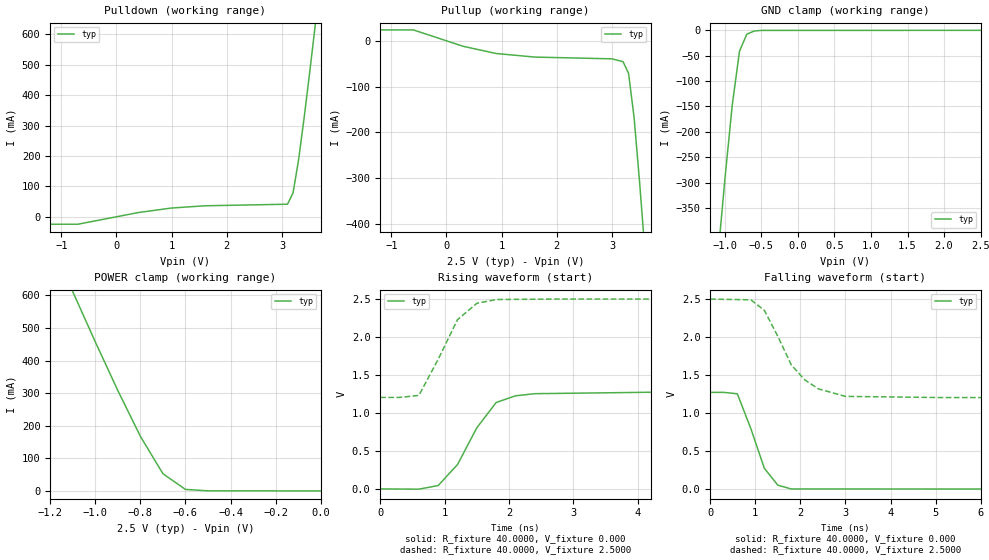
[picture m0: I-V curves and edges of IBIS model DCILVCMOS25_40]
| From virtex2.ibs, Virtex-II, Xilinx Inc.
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|   Model DCILVCMOS25_40
[Model]   DCILVCMOS25_40
Model_type   I/O
Polarity   Non-Inverting
Enable   Active-Low
Vinh = 1.7V
Vinl = 0.7V
Vmeas =   1.25V
Cref =  0pF
Rref =   1.00M
Vref =  0.000V
C_comp   7.0000pF   NA   NA
[Temperature Range]   25.0000   NA   NA
[Voltage Range]   2.5000V   NA   NA
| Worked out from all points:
|   slope of the pulldown table from 0 to 0.375 V, typ, clamps not added: 27.8 ohm
|   slope of the pullup table from 0 to 0.375 V, typ, clamps not added: 27.7 ohm
|   GND clamp passes 1 mA (typ) near -0.57 V on its own axis
|   POWER clamp passes 1 mA (typ) near -0.52 V on its own axis
|   rising waveform, R_fixture 40.0000, V_fixture 0.000: 20-80 % time 564ps typ, NA min, NA max; typ from 0 V to 1.27 V
|   rising waveform, R_fixture 40.0000, V_fixture 2.5000: 20-80 % time 470ps typ, NA min, NA max; typ from 1.21 V to 2.5 V
|   falling waveform, R_fixture 40.0000, V_fixture 0.000: 20-80 % time 472ps typ, NA min, NA max; typ from 1.27 V to 0 V
|   falling waveform, R_fixture 40.0000, V_fixture 2.5000: 20-80 % time 760ps typ, NA min, NA max; typ from 2.5 V to 1.21 V
[Pulldown]
| voltage   I(typ)   I(min)   I(max)
-2.5V     -24.24mA   NA         NA
-700mV    -24.24mA   NA         NA
400mV     14.29mA    NA         NA
1V        29.01mA    NA         NA
1.6V      36.31mA    NA         NA
3.1V      41.57mA    NA         NA
3.2V      78.58mA    NA         NA
3.3V      186.4mA    NA         NA
3.4V      324.1mA    NA         NA
3.5V      472.2mA    NA         NA
3.6V      625.7mA    NA         NA
5V        2.888A     NA         NA
[Pullup]
| voltage   I(typ)   I(min)   I(max)
-2.5V     24.74mA    NA         NA
-600mV    24.74mA    NA         NA
300mV     -11.11mA   NA         NA
900mV     -26.96mA   NA         NA
1.6V      -34.79mA   NA         NA
3V        -38.65mA   NA         NA
3.2V      -44.91mA   NA         NA
3.3V      -70.25mA   NA         NA
3.4V      -166.8mA   NA         NA
3.5V      -308.7mA   NA         NA
3.6V      -466mA     NA         NA
5V        -2.893A    NA         NA
[GND_clamp]
| voltage   I(typ)   I(min)   I(max)
-2.5V     -2.881A    NA         NA
-1.1V     -452.1mA   NA         NA
-1V       -293.4mA   NA         NA
-900mV    -148.1mA   NA         NA
-800mV    -41.04mA   NA         NA
-700mV    -7.632mA   NA         NA
-600mV    -1.432mA   NA         NA
-500mV    -131.2uA   NA         NA
2.5V      397.5nA    NA         NA
[POWER_clamp]
| voltage   I(typ)   I(min)   I(max)
-2.5V     2.874A     NA         NA
-1.1V     610.9mA    NA         NA
-1V       456.9mA    NA         NA
-900mV    307.7mA    NA         NA
-800mV    167.5mA    NA         NA
-700mV    52.78mA    NA         NA
-600mV    4.607mA    NA         NA
-500mV    279.3uA    NA         NA
0V        397.5nA    NA         NA
[Ramp]
| variable   typ   min   max
dV/dt_r   0.7638/0.5264n   NA   NA
dV/dt_f   0.7770/0.8296n   NA   NA
R_load = 40.0000
[Rising Waveform]
R_fixture = 40.0000
V_fixture = 0.000
| time   V(typ)   V(min)   V(max)
0s        7.936uV    NA         NA
600ps     -3.2mV     NA         NA
900ps     44.76mV    NA         NA
1.2ns     321mV      NA         NA
1.5ns     805mV      NA         NA
1.8ns     1.138V     NA         NA
2.1ns     1.226V     NA         NA
2.4ns     1.254V     NA         NA
4.2ns     1.273V     NA         NA
15ns      1.273V     NA         NA
[Rising Waveform]
R_fixture = 40.0000
V_fixture = 2.5000
V_fixture_min = 2.3000
V_fixture_max = 2.7000
| time   V(typ)   V(min)   V(max)
0s        1.205V     NA         NA
300ps     1.205V     NA         NA
600ps     1.231V     NA         NA
900ps     1.708V     NA         NA
1.2ns     2.229V     NA         NA
1.5ns     2.444V     NA         NA
1.8ns     2.494V     NA         NA
2.7ns     2.5V       NA         NA
15ns      2.5V       NA         NA
[Falling Waveform]
R_fixture = 40.0000
V_fixture = 0.000
| time   V(typ)   V(min)   V(max)
0s        1.273V     NA         NA
300ps     1.273V     NA         NA
600ps     1.254V     NA         NA
900ps     797.5mV    NA         NA
1.2ns     274.1mV    NA         NA
1.5ns     52.08mV    NA         NA
1.8ns     2.714mV    NA         NA
15ns      35.61uV    NA         NA
[Falling Waveform]
R_fixture = 40.0000
V_fixture = 2.5000
V_fixture_min = 2.3000
V_fixture_max = 2.7000
| time   V(typ)   V(min)   V(max)
0s        2.5V       NA         NA
900ps     2.49V      NA         NA
1.2ns     2.352V     NA         NA
1.5ns     2.009V     NA         NA
1.8ns     1.632V     NA         NA
2.1ns     1.436V     NA         NA
2.4ns     1.319V     NA         NA
3ns       1.22V      NA         NA
5.1ns     1.205V     NA         NA
15ns      1.205V     NA         NA
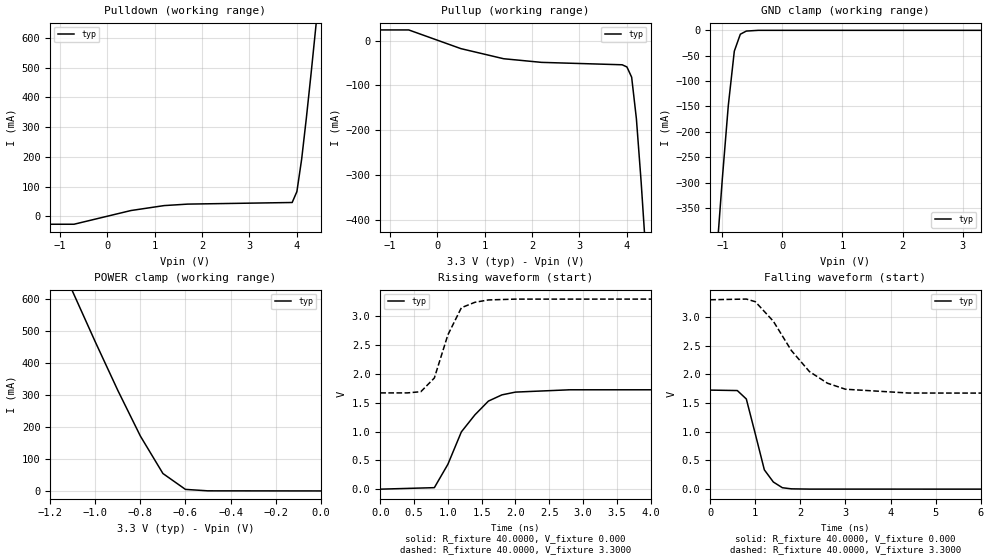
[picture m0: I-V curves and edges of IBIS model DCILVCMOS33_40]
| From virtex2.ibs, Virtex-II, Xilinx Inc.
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|   Model DCILVCMOS33_40
[Model]   DCILVCMOS33_40
Model_type   I/O
Polarity   Non-Inverting
Enable   Active-Low
Vinh = 2.0V
Vinl = 0.8V
Vmeas =   1.65V
Cref =  0pF
Rref =   1.00M
Vref =  0.000V
C_comp   7.0000pF   NA   NA
[Temperature Range]   25.0000   NA   NA
[Voltage Range]   3.3000V   NA   NA
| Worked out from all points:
|   slope of the pulldown table from 0 to 0.495 V, typ, clamps not added: 26 ohm
|   slope of the pullup table from 0 to 0.495 V, typ, clamps not added: 27.6 ohm
|   GND clamp passes 1 mA (typ) near -0.57 V on its own axis
|   POWER clamp passes 1 mA (typ) near -0.52 V on its own axis
|   rising waveform, R_fixture 40.0000, V_fixture 0.000: 20-80 % time 519ps typ, NA min, NA max; typ from 0 V to 1.73 V
|   rising waveform, R_fixture 40.0000, V_fixture 3.3000: 20-80 % time 308ps typ, NA min, NA max; typ from 1.67 V to 3.3 V
|   falling waveform, R_fixture 40.0000, V_fixture 0.000: 20-80 % time 335ps typ, NA min, NA max; typ from 1.73 V to 0 V
|   falling waveform, R_fixture 40.0000, V_fixture 3.3000: 20-80 % time 940ps typ, NA min, NA max; typ from 3.3 V to 1.67 V
[Pulldown]
| voltage   I(typ)   I(min)   I(max)
-3.3V     -26.92mA   NA         NA
-700mV    -26.92mA   NA         NA
500mV     19.2mA     NA         NA
1.2V      35.85mA    NA         NA
1.7V      40.85mA    NA         NA
3.9V      46.25mA    NA         NA
4V        83.11mA    NA         NA
4.1V      192mA      NA         NA
4.2V      331.6mA    NA         NA
4.3V      481.9mA    NA         NA
4.5V      796.2mA    NA         NA
6.6V      4.268A     NA         NA
[Pullup]
| voltage   I(typ)   I(min)   I(max)
-3.3V     23.49mA    NA         NA
-600mV    23.49mA    NA         NA
500mV     -18.08mA   NA         NA
1.4V      -40.51mA   NA         NA
2.2V      -48.62mA   NA         NA
3.9V      -53.96mA   NA         NA
4V        -58.78mA   NA         NA
4.1V      -81.59mA   NA         NA
4.2V      -174mA     NA         NA
4.3V      -314.4mA   NA         NA
4.5V      -635mA     NA         NA
6.6V      -4.317A    NA         NA
[GND_clamp]
| voltage   I(typ)   I(min)   I(max)
-3.3V     -4.301A    NA         NA
-1.1V     -452.1mA   NA         NA
-1V       -293.4mA   NA         NA
-900mV    -148.1mA   NA         NA
-800mV    -41.07mA   NA         NA
-700mV    -7.668mA   NA         NA
-600mV    -1.449mA   NA         NA
-400mV    -8.141uA   NA         NA
3.3V      540.8nA    NA         NA
[POWER_clamp]
| voltage   I(typ)   I(min)   I(max)
-3.3V     4.254A     NA         NA
-1.1V     621.4mA    NA         NA
-1V       465.1mA    NA         NA
-900mV    313.6mA    NA         NA
-800mV    171.2mA    NA         NA
-700mV    54.37mA    NA         NA
-600mV    4.797mA    NA         NA
-500mV    289.2uA    NA         NA
0V        540.8nA    NA         NA
[Ramp]
| variable   typ   min   max
dV/dt_r   1.0356/0.4397n   NA   NA
dV/dt_f   0.9774/0.9182n   NA   NA
R_load = 40.0000
[Rising Waveform]
R_fixture = 40.0000
V_fixture = 0.000
| time   V(typ)   V(min)   V(max)
0s        10.36uV    NA         NA
800ps     26.21mV    NA         NA
1ns       431.1mV    NA         NA
1.2ns     994.9mV    NA         NA
1.4ns     1.29V      NA         NA
1.6ns     1.529V     NA         NA
1.8ns     1.637V     NA         NA
2ns       1.685V     NA         NA
2.8ns     1.725V     NA         NA
10ns      1.726V     NA         NA
[Rising Waveform]
R_fixture = 40.0000
V_fixture = 3.3000
V_fixture_min = 3.0000
V_fixture_max = 3.6000
| time   V(typ)   V(min)   V(max)
0s        1.671V     NA         NA
400ps     1.671V     NA         NA
600ps     1.692V     NA         NA
800ps     1.93V      NA         NA
1ns       2.678V     NA         NA
1.2ns     3.15V      NA         NA
1.4ns     3.244V     NA         NA
1.6ns     3.285V     NA         NA
2ns       3.299V     NA         NA
10ns      3.3V       NA         NA
[Falling Waveform]
R_fixture = 40.0000
V_fixture = 0.000
| time   V(typ)   V(min)   V(max)
0s        1.726V     NA         NA
600ps     1.718V     NA         NA
800ps     1.571V     NA         NA
1ns       959.9mV    NA         NA
1.2ns     336.5mV    NA         NA
1.4ns     124.5mV    NA         NA
1.6ns     25.14mV    NA         NA
1.8ns     5.577mV    NA         NA
2.2ns     1.174mV    NA         NA
10ns      2.961uV    NA         NA
[Falling Waveform]
R_fixture = 40.0000
V_fixture = 3.3000
V_fixture_min = 3.0000
V_fixture_max = 3.6000
| time   V(typ)   V(min)   V(max)
0s        3.3V       NA         NA
800ps     3.312V     NA         NA
1ns       3.266V     NA         NA
1.4ns     2.925V     NA         NA
1.8ns     2.415V     NA         NA
2.2ns     2.049V     NA         NA
2.6ns     1.846V     NA         NA
3ns       1.741V     NA         NA
4.4ns     1.675V     NA         NA
10ns      1.671V     NA         NA
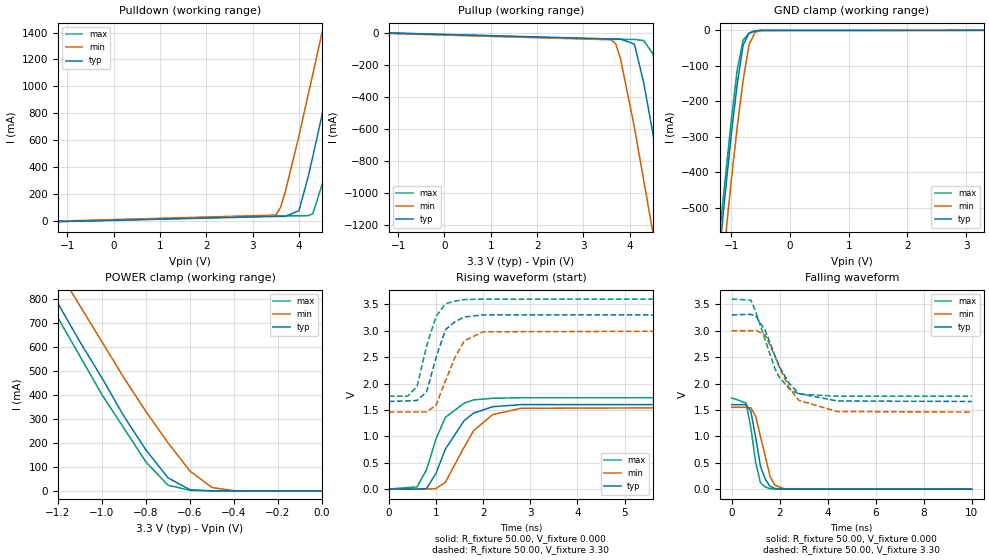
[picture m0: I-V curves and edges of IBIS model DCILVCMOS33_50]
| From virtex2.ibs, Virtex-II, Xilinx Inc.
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|   Model DCILVCMOS33_50
[Model]   DCILVCMOS33_50
Model_type   I/O
Polarity   Non-Inverting
Enable   Active-Low
Vinh = 2.0V
Vinl = 0.8V
Vmeas =   1.65V
Cref =  0pF
Rref =   1.00M
Vref =  0.000V
C_comp   10.00pF   10.00pF   10.00pF
[Temperature Range]   25.00   100.00   0.000
[Voltage Range]   3.30V   3.00V   3.60V
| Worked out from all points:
|   slope of the pulldown table from 0 to 0.495 V, typ, clamps not added: 32.3 ohm
|   slope of the pullup table from 0 to 0.495 V, typ, clamps not added: 38.4 ohm
|   GND clamp passes 1 mA (typ) near -0.57 V on its own axis
|   POWER clamp passes 1 mA (typ) near -0.52 V on its own axis
|   rising waveform, R_fixture 50.00, V_fixture 0.000: 20-80 % time 576ps typ, 604ps min, 445ps max; typ from 0 V to 1.6 V
|   rising waveform, R_fixture 50.00, V_fixture 3.30: 20-80 % time 336ps typ, 449ps min, 340ps max; typ from 1.66 V to 3.3 V
|   falling waveform, R_fixture 50.00, V_fixture 0.000: 20-80 % time 416ps typ, 491ps min, 376ps max; typ from 1.6 V to 0 V
|   falling waveform, R_fixture 50.00, V_fixture 3.30: 20-80 % time 1ns typ, 996ps min, 893ps max; typ from 3.3 V to 1.66 V
[Pulldown]
| voltage   I(typ)   I(min)   I(max)
-3.3V     -21.65mA   -19.86mA   -21.8mA
3.5V      34.6mA     44.62mA    38.71mA
3.6V      34.64mA    100mA      38.74mA
3.7V      34.69mA    210mA      38.78mA
4V        77.2mA     630mA      38.89mA
4.2V      330mA      940mA      40.79mA
4.3V      480mA      1.09A      55.46mA
4.5V      790mA      1.4A       270mA
4.9V      1.44A      2.02A      890mA
5.1V      1.77A      2.33A      1.22A
5.3V      2.1A       2.65A      1.55A
6.6V      4.27A      4.71A      3.71A
[Pullup]
| voltage   I(typ)   I(min)   I(max)
-3.3V     16.86mA    13.72mA    16.49mA
3.6V      -37.66mA   -42.86mA   -40.19mA
3.7V      -37.77mA   -69.63mA   -40.32mA
3.8V      -37.96mA   -160mA     -40.45mA
4.1V      -69.61mA   -590mA     -40.87mA
4.3V      -310mA     -920mA     -47.66mA
4.5V      -630mA     -1.25A     -130mA
4.7V      -970mA     -1.58A     -420mA
4.9V      -1.31A     -1.92A     -750mA
5.1V      -1.66A     -2.26A     -1.09A
5.3V      -2.01A     -2.61A     -1.44A
6.6V      -4.31A     -4.84A     -3.74A
[GND_clamp]
| voltage   I(typ)   I(min)   I(max)
-3.3V     -4.3A      -4.31A     -4.26A
-1.2V     -620mA     -740mA     -570mA
-1.1V     -450mA     -580mA     -410mA
-1V       -290mA     -420mA     -250mA
-900mV    -150mA     -270mA     -110mA
-800mV    -41.03mA   -140mA     -27.28mA
-700mV    -7.6mA     -40.21mA   -8.18mA
-600mV    -1.42mA    -5.61mA    -1.62mA
-500mV    -130uA     -670uA     -130uA
3.3V      67.85pA    43.48uA    45.6pA
[POWER_clamp]
| voltage   I(typ)   I(min)   I(max)
-3.3V     4.25A      4.22A      4.2A
-1.3V     940mA      1.07A      880mA
-1.2V     780mA      920mA      720mA
-1.1V     620mA      770mA      560mA
-1V       470mA      620mA      400mA
-900mV    310mA      470mA      260mA
-800mV    170mA      330mA      120mA
-700mV    54.34mA    200mA      23.62mA
-600mV    4.76mA     82.21mA    2.52mA
-500mV    280uA      14.02mA    260uA
-400mV    16.9uA     860uA      14.85uA
0V        67.85pA    2.04nA     61.89pA
[Ramp]
| variable   typ   min   max
dV/dt_r   0.96/0.52n   0.93/0.57n   1.04/0.43n
dV/dt_f   0.98/0.99n   0.92/0.98n   1.11/0.83n
R_load = 50.00
[Rising Waveform]
R_fixture = 50.00
V_fixture = 0.000
| time   V(typ)   V(min)   V(max)
0s        0V         0V         0V
600ps     -2.17mV    46.96uV    42.03mV
800ps     8.09mV     -900uV     370mV
1ns       300mV      10.79mV    950mV
1.2ns     760mV      130mV      1.36V
1.6ns     1.3V       800mV      1.63V
1.8ns     1.44V      1.11V      1.69V
2.2ns     1.56V      1.41V      1.72V
2.8ns     1.6V       1.53V      1.73V
10ns      1.6V       1.55V      1.73V
[Rising Waveform]
R_fixture = 50.00
V_fixture = 3.30
V_fixture_min = 3.00
V_fixture_max = 3.60
| time   V(typ)   V(min)   V(max)
0s        1.66V      1.46V      1.76V
400ps     1.67V      1.46V      1.76V
600ps     1.68V      1.46V      1.95V
800ps     1.84V      1.46V      2.71V
1ns       2.49V      1.59V      3.27V
1.2ns     3.02V      2.05V      3.51V
1.4ns     3.17V      2.49V      3.56V
1.6ns     3.26V      2.81V      3.59V
2ns       3.3V       2.98V      3.6V
10ns      3.3V       3V         3.6V
[Falling Waveform]
R_fixture = 50.00
V_fixture = 0.000
| time   V(typ)   V(min)   V(max)
0s        1.6V       1.55V      1.73V
600ps     1.6V       1.55V      1.63V
800ps     1.47V      1.54V      1.16V
1ns       970mV      1.38V      500mV
1.2ns     430mV      990mV      120mV
1.4ns     190mV      620mV      42.64mV
1.6ns     52.11mV    240mV      8.09mV
1.8ns     12.91mV    74.61mV    2.16mV
2.2ns     1.53mV     6.55mV     590uV
10ns      2.72uV     3.42uV     1.92uV
[Falling Waveform]
R_fixture = 50.00
V_fixture = 3.30
V_fixture_min = 3.00
V_fixture_max = 3.60
| time   V(typ)   V(min)   V(max)
0s        3.3V       3V         3.6V
800ps     3.31V      3V         3.58V
1ns       3.28V      3.01V      3.36V
1.4ns     3V         2.92V      2.82V
1.8ns     2.53V      2.52V      2.28V
2ns       2.31V      2.29V      2.11V
2.4ns     2V         1.92V      1.9V
2.8ns     1.81V      1.68V      1.8V
4.4ns     1.67V      1.47V      1.76V
10ns      1.66V      1.46V      1.76V
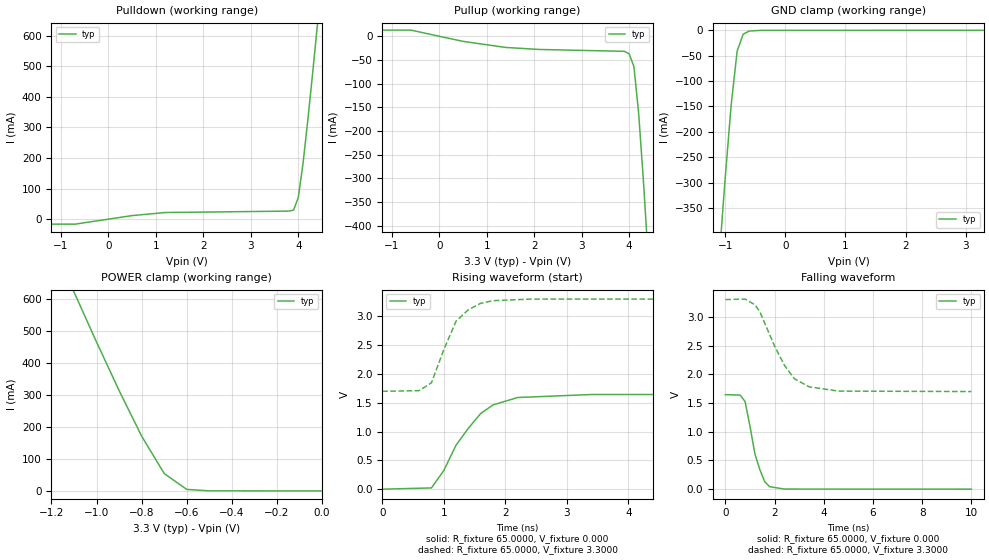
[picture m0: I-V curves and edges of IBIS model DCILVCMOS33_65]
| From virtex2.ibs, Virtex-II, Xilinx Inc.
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|   Model DCILVCMOS33_65
[Model]   DCILVCMOS33_65
Model_type   I/O
Polarity   Non-Inverting
Enable   Active-Low
Vinh = 2.0V
Vinl = 0.8V
Vmeas =   1.65V
Cref =  0pF
Rref =   1.00M
Vref =  0.000V
C_comp   7.0000pF   NA   NA
[Temperature Range]   25.0000   NA   NA
[Voltage Range]   3.3000V   NA   NA
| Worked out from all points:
|   slope of the pulldown table from 0 to 0.495 V, typ, clamps not added: 42.9 ohm
|   slope of the pullup table from 0 to 0.495 V, typ, clamps not added: 48.1 ohm
|   GND clamp passes 1 mA (typ) near -0.57 V on its own axis
|   POWER clamp passes 1 mA (typ) near -0.52 V on its own axis
|   rising waveform, R_fixture 65.0000, V_fixture 0.000: 20-80 % time 601ps typ, NA min, NA max; typ from 0 V to 1.65 V
|   rising waveform, R_fixture 65.0000, V_fixture 3.3000: 20-80 % time 404ps typ, NA min, NA max; typ from 1.7 V to 3.3 V
|   falling waveform, R_fixture 65.0000, V_fixture 0.000: 20-80 % time 514ps typ, NA min, NA max; typ from 1.65 V to 0 V
|   falling waveform, R_fixture 65.0000, V_fixture 3.3000: 20-80 % time 1.11ns typ, NA min, NA max; typ from 3.3 V to 1.7 V
[Pulldown]
| voltage   I(typ)   I(min)   I(max)
-3.3V     -16.31mA   NA         NA
-700mV    -16.31mA   NA         NA
500mV     11.65mA    NA         NA
1.2V      21.67mA    NA         NA
3.8V      26.28mA    NA         NA
3.9V      29.65mA    NA         NA
4V        71.39mA    NA         NA
4.1V      183.8mA    NA         NA
4.2V      324.4mA    NA         NA
4.3V      475.2mA    NA         NA
4.5V      789.9mA    NA         NA
6.6V      4.263A     NA         NA
[Pullup]
| voltage   I(typ)   I(min)   I(max)
-3.3V     13.45mA    NA         NA
-600mV    13.45mA    NA         NA
500mV     -10.39mA   NA         NA
1.4V      -23.22mA   NA         NA
2.1V      -27.49mA   NA         NA
3.9V      -31.44mA   NA         NA
4V        -36.8mA    NA         NA
4.1V      -63.72mA   NA         NA
4.2V      -162.7mA   NA         NA
4.3V      -305.3mA   NA         NA
4.5V      -627.3mA   NA         NA
6.6V      -4.31A     NA         NA
[GND_clamp]
| voltage   I(typ)   I(min)   I(max)
-3.3V     -4.301A    NA         NA
-1.1V     -452.1mA   NA         NA
-1V       -293.4mA   NA         NA
-900mV    -148.1mA   NA         NA
-800mV    -41.07mA   NA         NA
-700mV    -7.668mA   NA         NA
-600mV    -1.449mA   NA         NA
-400mV    -8.141uA   NA         NA
3.3V      540.8nA    NA         NA
[POWER_clamp]
| voltage   I(typ)   I(min)   I(max)
-3.3V     4.254A     NA         NA
-1.1V     621.4mA    NA         NA
-1V       465.1mA    NA         NA
-900mV    313.6mA    NA         NA
-800mV    171.2mA    NA         NA
-700mV    54.37mA    NA         NA
-600mV    4.797mA    NA         NA
-500mV    289.2uA    NA         NA
0V        540.8nA    NA         NA
[Ramp]
| variable   typ   min   max
dV/dt_r   0.9870/0.5441n   NA   NA
dV/dt_f   0.9606/1.1061n   NA   NA
R_load = 65.0000
[Rising Waveform]
R_fixture = 65.0000
V_fixture = 0.000
| time   V(typ)   V(min)   V(max)
0s        17.08uV    NA         NA
800ps     21.59mV    NA         NA
1ns       323.1mV    NA         NA
1.2ns     763.9mV    NA         NA
1.4ns     1.057V     NA         NA
1.6ns     1.313V     NA         NA
1.8ns     1.462V     NA         NA
2.2ns     1.591V     NA         NA
3.4ns     1.643V     NA         NA
10ns      1.645V     NA         NA
[Rising Waveform]
R_fixture = 65.0000
V_fixture = 3.3000
V_fixture_min = 3.0000
V_fixture_max = 3.6000
| time   V(typ)   V(min)   V(max)
0s        1.699V     NA         NA
600ps     1.71V      NA         NA
800ps     1.847V     NA         NA
1ns       2.42V      NA         NA
1.2ns     2.916V     NA         NA
1.4ns     3.115V     NA         NA
1.6ns     3.226V     NA         NA
1.8ns     3.272V     NA         NA
2.4ns     3.299V     NA         NA
10ns      3.3V       NA         NA
[Falling Waveform]
R_fixture = 65.0000
V_fixture = 0.000
| time   V(typ)   V(min)   V(max)
0s        1.645V     NA         NA
600ps     1.638V     NA         NA
800ps     1.526V     NA         NA
1ns       1.097V     NA         NA
1.2ns     611.8mV    NA         NA
1.4ns     341.1mV    NA         NA
1.6ns     129.7mV    NA         NA
1.8ns     43.4mV     NA         NA
2.4ns     1.764mV    NA         NA
10ns      2.586uV    NA         NA
[Falling Waveform]
R_fixture = 65.0000
V_fixture = 3.3000
V_fixture_min = 3.0000
V_fixture_max = 3.6000
| time   V(typ)   V(min)   V(max)
0s        3.3V       NA         NA
800ps     3.309V     NA         NA
1.2ns     3.209V     NA         NA
1.4ns     3.09V      NA         NA
2ns       2.49V      NA         NA
2.4ns     2.156V     NA         NA
2.8ns     1.922V     NA         NA
3.4ns     1.782V     NA         NA
4.6ns     1.707V     NA         NA
10ns      1.699V     NA         NA
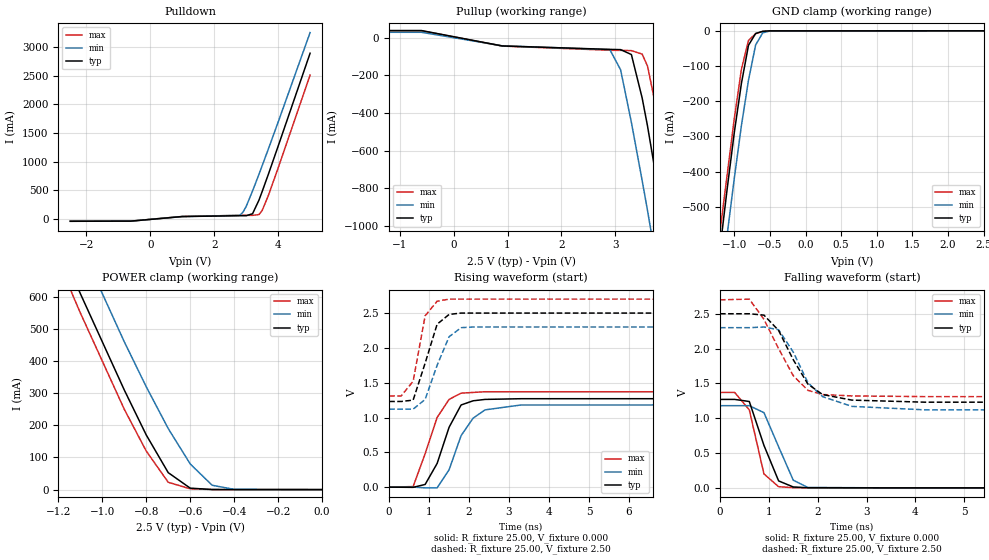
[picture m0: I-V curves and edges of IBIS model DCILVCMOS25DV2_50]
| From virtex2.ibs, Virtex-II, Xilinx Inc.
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|   Model DCILVCMOS25DV2_50
[Model]   DCILVCMOS25DV2_50
Model_type   I/O
Polarity   Non-Inverting
Enable   Active-Low
Vinh = 1.7V
Vinl = 0.7V
Vmeas =   1.25V
Cref =  0pF
Rref =   1.00M
Vref =  0.000V
C_comp   10.00pF   10.00pF   10.00pF
[Temperature Range]   25.00   100.00   0.000
[Voltage Range]   2.50V   2.30V   2.70V
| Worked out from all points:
|   slope of the pulldown table from 0 to 0.375 V, typ, clamps not added: 17.9 ohm
|   slope of the pullup table from 0 to 0.375 V, typ, clamps not added: 17.5 ohm
|   GND clamp passes 1 mA (typ) near -0.57 V on its own axis
|   POWER clamp passes 1 mA (typ) near -0.52 V on its own axis
|   rising waveform, R_fixture 25.00, V_fixture 0.000: 20-80 % time 532ps typ, 561ps min, 542ps max; typ from 0 V to 1.27 V
|   rising waveform, R_fixture 25.00, V_fixture 2.50: 20-80 % time 417ps typ, 471ps min, 266ps max; typ from 1.23 V to 2.5 V
|   falling waveform, R_fixture 25.00, V_fixture 0.000: 20-80 % time 403ps typ, 438ps min, 268ps max; typ from 1.27 V to 0 V
|   falling waveform, R_fixture 25.00, V_fixture 2.50: 20-80 % time 602ps typ, 638ps min, 633ps max; typ from 2.5 V to 1.23 V
[Pulldown]
| voltage   I(typ)   I(min)   I(max)
-2.5V     -37.66mA   -34.1mA    -37.09mA
-600mV    -34.29mA   -34.1mA    -33.64mA
1V        45.1mA     44.22mA    46.86mA
2.8V      59.9mA     66.29mA    65.7mA
2.9V      60.01mA    120mA      65.8mA
3V        60.24mA    220mA      65.89mA
3.2V      93.83mA    490mA      66.18mA
3.4V      330mA      780mA      78.51mA
3.5V      480mA      930mA      150mA
3.7V      790mA      1.23A      420mA
4V        1.27A      1.69A      890mA
5V        2.89A      3.25A      2.51A
[Pullup]
| voltage   I(typ)   I(min)   I(max)
-2.5V     39.29mA    30.07mA    38.18mA
-600mV    39.29mA    30.07mA    38.18mA
900mV     -42.78mA   -42.07mA   -43.49mA
2.9V      -61.15mA   -62.42mA   -65.81mA
3.1V      -62.44mA   -170mA     -66.34mA
3.3V      -88.52mA   -450mA     -67.7mA
3.5V      -320mA     -760mA     -86.3mA
3.6V      -470mA     -920mA     -150mA
3.8V      -810mA     -1.26A     -430mA
4V        -1.15A     -1.59A     -760mA
4.2V      -1.49A     -1.93A     -1.1A
5V        -2.9A      -3.3A      -2.5A
[GND_clamp]
| voltage   I(typ)   I(min)   I(max)
-2.5V     -2.88A     -2.94A     -2.84A
-1.2V     -620mA     -740mA     -570mA
-1.1V     -450mA     -580mA     -410mA
-1V       -290mA     -420mA     -250mA
-900mV    -150mA     -270mA     -110mA
-800mV    -41mA      -140mA     -27.22mA
-700mV    -7.57mA    -40.19mA   -8.13mA
-600mV    -1.4mA     -5.59mA    -1.6mA
-500mV    -130uA     -660uA     -120uA
2.5V      49.34pA    2.1uA      32.91pA
[POWER_clamp]
| voltage   I(typ)   I(min)   I(max)
-2.5V     2.87A      2.91A      2.82A
-1.3V     930mA      1.05A      870mA
-1.2V     770mA      910mA      710mA
-1.1V     610mA      760mA      550mA
-900mV    310mA      460mA      250mA
-800mV    170mA      320mA      120mA
-700mV    52.75mA    190mA      22.81mA
-600mV    4.57mA     79.88mA    2.44mA
-500mV    270uA      13.45mA    250uA
-400mV    16.38uA    820uA      14.46uA
0V        49.34pA    1.47nA     44.79pA
[Ramp]
| variable   typ   min   max
dV/dt_r   0.76/0.46n   0.71/0.59n   0.82/0.38n
dV/dt_f   0.76/0.68n   0.71/0.66n   0.83/0.55n
R_load = 25.00
[Rising Waveform]
R_fixture = 25.00
V_fixture = 0.000
| time   V(typ)   V(min)   V(max)
0s        0V         0V         0V
600ps     -2.7mV     130uV      8.45mV
900ps     38.59mV    -9.51mV    480mV
1.2ns     340mV      -10.17mV   1V
1.5ns     860mV      250mV      1.26V
1.8ns     1.18V      740mV      1.35V
2.1ns     1.24V      990mV      1.36V
2.4ns     1.26V      1.11V      1.37V
3.3ns     1.27V      1.18V      1.37V
15ns      1.27V      1.18V      1.37V
[Rising Waveform]
R_fixture = 25.00
V_fixture = 2.50
V_fixture_min = 2.30
V_fixture_max = 2.70
| time   V(typ)   V(min)   V(max)
0s        1.23V      1.12V      1.31V
300ps     1.23V      1.12V      1.31V
600ps     1.25V      1.12V      1.52V
900ps     1.78V      1.26V      2.46V
1.2ns     2.34V      1.75V      2.67V
1.5ns     2.48V      2.16V      2.7V
1.8ns     2.5V       2.29V      2.7V
2.1ns     2.5V       2.3V       2.7V
15ns      2.5V       2.3V       2.7V
[Falling Waveform]
R_fixture = 25.00
V_fixture = 0.000
| time   V(typ)   V(min)   V(max)
0s        1.27V      1.18V      1.37V
300ps     1.27V      1.18V      1.37V
600ps     1.24V      1.18V      1.12V
900ps     610mV      1.08V      200mV
1.2ns     100mV      590mV      16.52mV
1.5ns     12.69mV    110mV      3.17mV
1.8ns     1.59mV     5.98mV     850uV
3.3ns     110uV      150uV      2.01uV
15ns      5.16uV     -21uV      -14.66uV
[Falling Waveform]
R_fixture = 25.00
V_fixture = 2.50
V_fixture_min = 2.30
V_fixture_max = 2.70
| time   V(typ)   V(min)   V(max)
0s        2.5V       2.3V       2.7V
600ps     2.5V       2.3V       2.71V
900ps     2.48V      2.31V      2.42V
1.2ns     2.26V      2.27V      2V
1.5ns     1.84V      1.95V      1.61V
1.8ns     1.49V      1.51V      1.4V
2.1ns     1.34V      1.31V      1.34V
2.7ns     1.26V      1.17V      1.32V
4.2ns     1.23V      1.12V      1.31V
15ns      1.23V      1.12V      1.31V
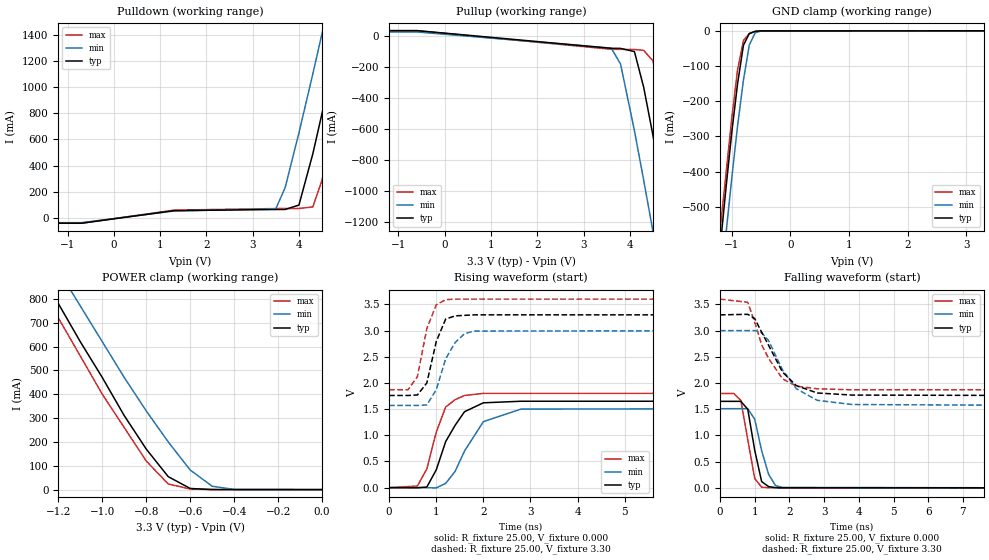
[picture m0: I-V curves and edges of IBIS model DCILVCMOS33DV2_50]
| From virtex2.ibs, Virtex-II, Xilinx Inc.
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|   Model DCILVCMOS33DV2_50
[Model]   DCILVCMOS33DV2_50
Model_type   I/O
Polarity   Non-Inverting
Enable   Active-Low
Vinh = 2.0V
Vinl = 0.8V
Vmeas =   1.65V
Cref =  0pF
Rref =   1.00M
Vref =  0.000V
C_comp   10.00pF   10.00pF   10.00pF
[Temperature Range]   25.00   100.00   0.000
[Voltage Range]   3.30V   3.00V   3.60V
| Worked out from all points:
|   slope of the pulldown table from 0 to 0.495 V, typ, clamps not added: 17.5 ohm
|   slope of the pullup table from 0 to 0.495 V, typ, clamps not added: 18.5 ohm
|   GND clamp passes 1 mA (typ) near -0.57 V on its own axis
|   POWER clamp passes 1 mA (typ) near -0.52 V on its own axis
|   rising waveform, R_fixture 25.00, V_fixture 0.000: 20-80 % time 506ps typ, 562ps min, 358ps max; typ from 0 V to 1.65 V
|   rising waveform, R_fixture 25.00, V_fixture 3.30: 20-80 % time 277ps typ, 374ps min, 274ps max; typ from 1.76 V to 3.3 V
|   falling waveform, R_fixture 25.00, V_fixture 0.000: 20-80 % time 284ps typ, 347ps min, 290ps max; typ from 1.65 V to 0 V
|   falling waveform, R_fixture 25.00, V_fixture 3.30: 20-80 % time 794ps typ, 802ps min, 679ps max; typ from 3.3 V to 1.76 V
[Pulldown]
| voltage   I(typ)   I(min)   I(max)
-3.3V     -40.16mA   -35.89mA   -40.18mA
-700mV    -40.16mA   -35.89mA   -40.18mA
1.3V      55.88mA    53.38mA    59.94mA
3.5V      64.69mA    70.42mA    71.84mA
3.7V      64.84mA    230mA      71.98mA
4V        98.38mA    650mA      72.17mA
4.3V      490mA      1.1A       84.39mA
4.5V      800mA      1.41A      290mA
4.9V      1.45A      2.03A      910mA
5.1V      1.78A      2.35A      1.23A
5.3V      2.11A      2.66A      1.56A
6.6V      4.28A      4.72A      3.72A
[Pullup]
| voltage   I(typ)   I(min)   I(max)
-3.3V     35.26mA    26.59mA    34.69mA
-600mV    35.26mA    26.59mA    34.69mA
3.6V      -79.04mA   -77.8mA    -85.36mA
3.8V      -79.55mA   -180mA     -85.91mA
4.1V      -100mA     -610mA     -86.68mA
4.3V      -330mA     -930mA     -92.25mA
4.5V      -640mA     -1.26A     -160mA
4.7V      -980mA     -1.6A      -440mA
4.9V      -1.32A     -1.93A     -770mA
5.1V      -1.67A     -2.28A     -1.11A
5.3V      -2.02A     -2.62A     -1.46A
6.6V      -4.32A     -4.86A     -3.75A
[GND_clamp]
| voltage   I(typ)   I(min)   I(max)
-3.3V     -4.3A      -4.31A     -4.26A
-1.2V     -620mA     -740mA     -570mA
-1.1V     -450mA     -580mA     -410mA
-1V       -290mA     -420mA     -250mA
-900mV    -150mA     -270mA     -110mA
-800mV    -41.03mA   -140mA     -27.28mA
-700mV    -7.6mA     -40.21mA   -8.18mA
-600mV    -1.42mA    -5.61mA    -1.62mA
-500mV    -130uA     -670uA     -130uA
3.3V      67.85pA    43.48uA    45.6pA
[POWER_clamp]
| voltage   I(typ)   I(min)   I(max)
-3.3V     4.25A      4.22A      4.2A
-1.3V     940mA      1.07A      880mA
-1.2V     780mA      920mA      720mA
-1.1V     620mA      770mA      560mA
-1V       470mA      620mA      400mA
-900mV    310mA      470mA      260mA
-800mV    170mA      330mA      120mA
-700mV    54.34mA    200mA      23.62mA
-600mV    4.76mA     82.21mA    2.52mA
-500mV    280uA      14.02mA    260uA
-400mV    16.9uA     860uA      14.85uA
0V        67.85pA    2.04nA     61.89pA
[Ramp]
| variable   typ   min   max
dV/dt_r   0.99/0.43n   0.91/0.55n   1.08/0.35n
dV/dt_f   0.92/0.74n   0.86/0.79n   1.04/0.61n
R_load = 25.00
[Rising Waveform]
R_fixture = 25.00
V_fixture = 0.000
| time   V(typ)   V(min)   V(max)
0s        0V         0V         0V
600ps     -1.87mV    47.93uV    31.12mV
800ps     11.93mV    -1.3mV     360mV
1ns       340mV      -4.03mV    1.06V
1.2ns     880mV      81.83mV    1.54V
1.4ns     1.19V      310mV      1.68V
1.6ns     1.45V      700mV      1.76V
2ns       1.62V      1.26V      1.8V
2.8ns     1.65V      1.5V       1.8V
10ns      1.65V      1.51V      1.8V
[Rising Waveform]
R_fixture = 25.00
V_fixture = 3.30
V_fixture_min = 3.00
V_fixture_max = 3.60
| time   V(typ)   V(min)   V(max)
0s        1.76V      1.57V      1.87V
400ps     1.76V      1.57V      1.87V
600ps     1.77V      1.57V      2.12V
800ps     2V         1.58V      3.04V
1ns       2.79V      1.87V      3.49V
1.2ns     3.22V      2.46V      3.59V
1.4ns     3.28V      2.77V      3.6V
1.6ns     3.29V      2.94V      3.6V
1.8ns     3.3V       2.99V      3.6V
10ns      3.3V       3V         3.6V
[Falling Waveform]
R_fixture = 25.00
V_fixture = 0.000
| time   V(typ)   V(min)   V(max)
0s        1.65V      1.51V      1.8V
400ps     1.65V      1.51V      1.8V
600ps     1.65V      1.51V      1.67V
800ps     1.5V       1.51V      920mV
1ns       720mV      1.31V      180mV
1.2ns     120mV      710mV      11.92mV
1.4ns     23.92mV    260mV      3.97mV
1.6ns     4.58mV     43.06mV    1.51mV
1.8ns     1.81mV     8.31mV     860uV
10ns      0V         3.04uV     2.09uV
[Falling Waveform]
R_fixture = 25.00
V_fixture = 3.30
V_fixture_min = 3.00
V_fixture_max = 3.60
| time   V(typ)   V(min)   V(max)
0s        3.3V       3V         3.6V
800ps     3.31V      3V         3.54V
1ns       3.23V      3V         3.16V
1.2ns     2.97V      2.96V      2.73V
1.4ns     2.72V      2.81V      2.47V
1.8ns     2.21V      2.25V      2.08V
2.2ns     1.95V      1.89V      1.94V
2.8ns     1.81V      1.67V      1.89V
3.8ns     1.77V      1.59V      1.87V
10ns      1.76V      1.57V      1.87V
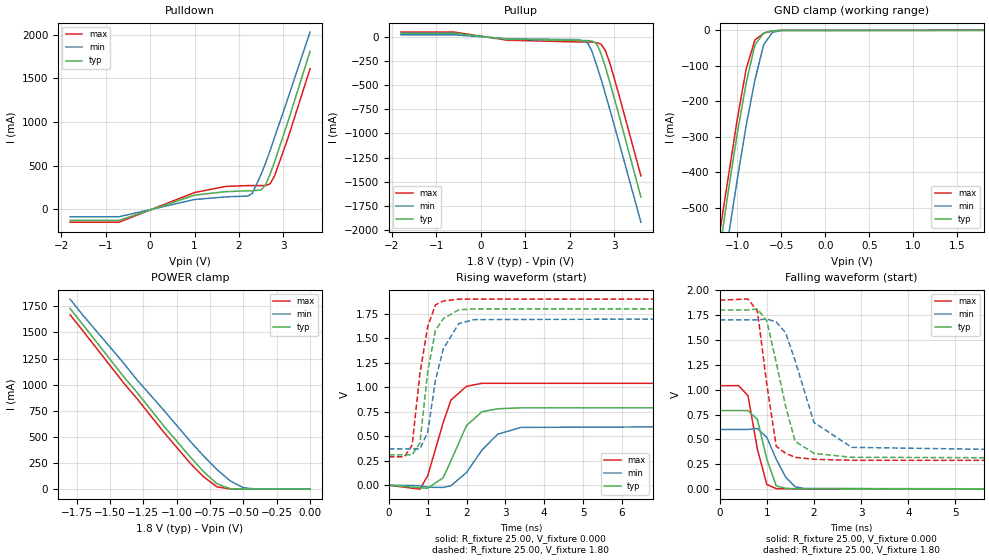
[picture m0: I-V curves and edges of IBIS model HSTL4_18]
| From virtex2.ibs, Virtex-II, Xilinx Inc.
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|   Model HSTL4_18
[Model]   HSTL4_18
Model_type   I/O
Polarity   Non-Inverting
Enable   Active-Low
Vinh = 1.2V
Vinl = 1.0V
Vmeas =   1.10V
Cref =  0pF
Rref =  25.00
Vref =   1.80V
C_comp   10.00pF   10.00pF   10.00pF
[Temperature Range]   25.00   100.00   0.000
[Voltage Range]   1.80V   1.70V   1.90V
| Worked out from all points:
|   slope of the pulldown table from 0 to 0.27 V, typ, clamps not added: 5.17 ohm
|   slope of the pullup table from 0 to 0.27 V, typ, clamps not added: 19.5 ohm
|   GND clamp passes 1 mA (typ) near -0.57 V on its own axis
|   POWER clamp passes 1 mA (typ) near -0.52 V on its own axis
|   rising waveform, R_fixture 25.00, V_fixture 0.000: 20-80 % time 555ps typ, 708ps min, 491ps max; typ from 0 V to 0.79 V
|   rising waveform, R_fixture 25.00, V_fixture 1.80: 20-80 % time 314ps typ, 413ps min, 327ps max; typ from 0.31 V to 1.8 V
|   falling waveform, R_fixture 25.00, V_fixture 0.000: 20-80 % time 272ps typ, 364ps min, 269ps max; typ from 0.79 V to 0 V
|   falling waveform, R_fixture 25.00, V_fixture 1.80: 20-80 % time 437ps typ, 551ps min, 284ps max; typ from 1.8 V to 0.31 V
[Pulldown]
| voltage   I(typ)   I(min)   I(max)
-1.8V     -130mA     -87.54mA   -150mA
-700mV    -130mA     -87.54mA   -150mA
1V        160mA      110mA      190mA
1.7V      200mA      140mA      260mA
2.2V      210mA      150mA      270mA
2.3V      210mA      180mA      270mA
2.5V      220mA      400mA      270mA
2.6V      280mA      530mA      270mA
2.7V      400mA      670mA      290mA
2.8V      540mA      820mA      380mA
3.1V      1A         1.27A      810mA
3.6V      1.81A      2.03A      1.61A
[Pullup]
| voltage   I(typ)   I(min)   I(max)
-1.8V     39.53mA    22.35mA    50.25mA
-600mV    39.53mA    22.35mA    50.25mA
600mV     -25.23mA   -18.99mA   -34.06mA
2.2V      -36.44mA   -27.71mA   -51.87mA
2.4V      -37.84mA   -60.77mA   -52.52mA
2.5V      -43.04mA   -150mA     -53.71mA
2.6V      -68.77mA   -290mA     -59.14mA
2.7V      -170mA     -430mA     -73.59mA
2.8V      -310mA     -590mA     -140mA
2.9V      -470mA     -750mA     -270mA
3.1V      -800mA     -1.08A     -590mA
3.6V      -1.66A     -1.92A     -1.44A
[GND_clamp]
| voltage   I(typ)   I(min)   I(max)
-1.8V     -1.65A     -1.74A     -1.6A
-1.2V     -620mA     -740mA     -570mA
-1.1V     -450mA     -580mA     -410mA
-1V       -290mA     -420mA     -250mA
-900mV    -150mA     -270mA     -110mA
-800mV    -40.97mA   -140mA     -27.17mA
-700mV    -7.54mA    -40.17mA   -8.08mA
-600mV    -1.39mA    -5.57mA    -1.57mA
-500mV    -120uA     -660uA     -120uA
1.8V      34.27pA    98.88nA    22.46pA
[POWER_clamp]
| voltage   I(typ)   I(min)   I(max)
-1.8V     1.73A      1.82A      1.67A
-1.7V     1.57A      1.66A      1.51A
-1.4V     1.08A      1.21A      1.02A
-1.3V     930mA      1.05A      870mA
-1.1V     610mA      760mA      550mA
-900mV    310mA      460mA      250mA
-800mV    170mA      320mA      120mA
-700mV    52.75mA    190mA      22.81mA
-600mV    4.57mA     79.88mA    2.44mA
-500mV    270uA      13.45mA    250uA
-400mV    16.38uA    820uA      14.46uA
0V        34.27pA    1.07nA     29.84pA
[Ramp]
| variable   typ   min   max
dV/dt_r   0.47/0.54n   0.36/0.71n   0.62/0.41n
dV/dt_f   0.89/0.33n   0.80/0.52n   0.97/0.25n
R_load = 25.00
[Rising Waveform]
R_fixture = 25.00
V_fixture = 0.000
| time   V(typ)   V(min)   V(max)
0s        0V         0V         0V
800ps     -25.6mV    -4.61mV    -40.36mV
1ns       -31.45mV   -20.26mV   95.89mV
1.4ns     77.16mV    -22.8mV    640mV
1.6ns     250mV      -5.11mV    870mV
2ns       610mV      130mV      1.01V
2.4ns     750mV      360mV      1.04V
2.8ns     780mV      520mV      1.04V
3.4ns     790mV      590mV      1.04V
10ns      790mV      600mV      1.04V
[Rising Waveform]
R_fixture = 25.00
V_fixture = 1.80
V_fixture_min = 1.70
V_fixture_max = 1.90
| time   V(typ)   V(min)   V(max)
0s        310mV      370mV      290mV
400ps     310mV      370mV      290mV
600ps     310mV      370mV      410mV
800ps     430mV      370mV      1.14V
1ns       1.16V      540mV      1.62V
1.2ns     1.58V      1.07V      1.84V
1.4ns     1.7V       1.39V      1.88V
1.8ns     1.79V      1.65V      1.9V
2.2ns     1.8V       1.69V      1.9V
10ns      1.8V       1.7V       1.9V
[Falling Waveform]
R_fixture = 25.00
V_fixture = 0.000
| time   V(typ)   V(min)   V(max)
0s        790mV      600mV      1.04V
400ps     790mV      600mV      1.04V
600ps     790mV      600mV      940mV
800ps     700mV      610mV      400mV
1ns       300mV      520mV      47.06mV
1.2ns     32.48mV    300mV      5.04mV
1.4ns     8.29mV     120mV      3.92mV
1.6ns     4.5mV      23.67mV    2.63mV
1.8ns     2.99mV     7.06mV     1.78mV
10ns      0V         0V         -770nV
[Falling Waveform]
R_fixture = 25.00
V_fixture = 1.80
V_fixture_min = 1.70
V_fixture_max = 1.90
| time   V(typ)   V(min)   V(max)
0s        1.8V       1.7V       1.9V
600ps     1.8V       1.7V       1.91V
800ps     1.81V      1.7V       1.79V
1ns       1.69V      1.71V      1.05V
1.2ns     1.27V      1.68V      430mV
1.4ns     830mV      1.57V      360mV
1.6ns     480mV      1.29V      320mV
2ns       360mV      670mV      300mV
2.8ns     320mV      420mV      290mV
10ns      310mV      370mV      290mV
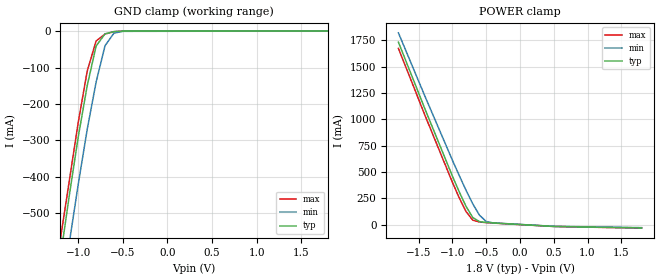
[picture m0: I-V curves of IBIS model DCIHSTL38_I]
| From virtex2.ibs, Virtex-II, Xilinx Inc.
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|   Model DCIHSTL38_I
[Model]   DCIHSTL38_I
Model_type   Input
Vinh = 1.2V
Vinl = 1.0V
Polarity   Non-Inverting
C_comp   10.00pF   10.00pF   10.00pF
[Temperature Range]   25.00   100.00   0.000
[Voltage Range]   1.80V   1.70V   1.90V
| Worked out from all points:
|   GND clamp passes 1 mA (typ) near -0.57 V on its own axis
|   POWER clamp passes 1 mA (typ) near -0.02 V on its own axis
[GND_clamp]
| voltage   I(typ)   I(min)   I(max)
-1.8V     -1.65A     -1.74A     -1.6A
-1.2V     -620mA     -740mA     -570mA
-1.1V     -450mA     -580mA     -410mA
-1V       -290mA     -420mA     -250mA
-900mV    -150mA     -270mA     -110mA
-800mV    -40.97mA   -140mA     -27.17mA
-700mV    -7.54mA    -40.17mA   -8.08mA
-600mV    -1.39mA    -5.57mA    -1.57mA
-500mV    -120uA     -660uA     -120uA
1.8V      34.27pA    98.88nA    22.46pA
[POWER_clamp]
| voltage   I(typ)   I(min)   I(max)
-1.8V     1.732A     1.82A      1.673A
-1.4V     1.087A     1.208A     1.027A
-1V       460.5mA    611.5mA    401.8mA
-900mV    312.7mA    467.7mA    256.1mA
-800mV    176mA      328.8mA    126.3mA
-700mV    69.28mA    199.2mA    44.33mA
-600mV    29.76mA    90.8mA     26.43mA
-500mV    22.34mA    31.4mA     20.7mA
-400mV    17.48mA    17.72mA    16.35mA
500mV     -15.81mA   -14.66mA   -16.03mA
1.8V      -29.89mA   -27.07mA   -32.03mA
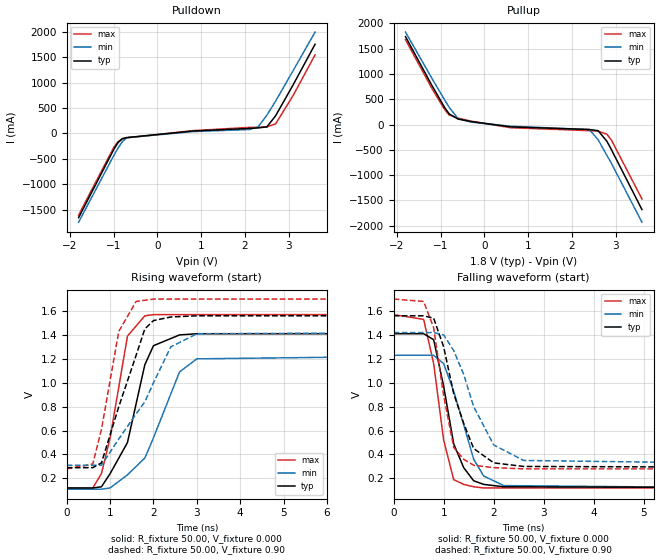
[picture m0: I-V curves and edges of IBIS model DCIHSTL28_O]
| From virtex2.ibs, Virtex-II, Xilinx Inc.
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|   Model DCIHSTL28_O
[Model]   DCIHSTL28_O
Model_type   Output
Polarity   Non-Inverting
Vmeas =   0.90V
Cref =  0pF
Rref =  50.00
Vref =   0.90V
C_comp   10.00pF   10.00pF   10.00pF
[Temperature Range]   25.00   100.00   0.000
[Voltage Range]   1.80V   1.70V   1.90V
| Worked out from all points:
|   slope of the pulldown table from 0 to 0.27 V, typ, clamps not added: 11.1 ohm
|   slope of the pullup table from 0 to 0.27 V, typ, clamps not added: 8.43 ohm
|   rising waveform, R_fixture 50.00, V_fixture 0.000: 20-80 % time 577ps typ, 760ps min, 420ps max; typ from 0.12 V to 1.41 V
|   rising waveform, R_fixture 50.00, V_fixture 0.90: 20-80 % time 716ps typ, 1.04ns min, 426ps max; typ from 0.29 V to 1.56 V
|   falling waveform, R_fixture 50.00, V_fixture 0.000: 20-80 % time 405ps typ, 503ps min, 332ps max; typ from 1.41 V to 0.12 V
|   falling waveform, R_fixture 50.00, V_fixture 0.90: 20-80 % time 515ps typ, 648ps min, 336ps max; typ from 1.56 V to 0.29 V
[Pulldown]
| voltage   I(typ)   I(min)   I(max)
-1.8V     -1.66A     -1.75A     -1.61A
-1V       -320mA     -440mA     -280mA
-900mV    -180mA     -290mA     -160mA
-800mV    -100mA     -160mA     -110mA
-700mV    -80.55mA   -83.71mA   -86.86mA
800mV     47.46mA    36.92mA    55.65mA
2.1V      99.38mA    77.68mA    120mA
2.3V      110mA      130mA      120mA
2.5V      130mA      360mA      130mA
2.7V      350mA      640mA      190mA
3.1V      960mA      1.24A      750mA
3.6V      1.76A      2A         1.55A
[Pullup]
| voltage   I(typ)   I(min)   I(max)
-1.8V     1.74A      1.83A      1.68A
-1.2V     780mA      920mA      720mA
-900mV    330mA      480mA      290mA
-800mV    210mA      340mA      190mA
-600mV    110mA      120mA      130mA
-300mV    60.47mA    49.43mA    67.86mA
600mV     -44.21mA   -31.9mA    -60.97mA
2.4V      -96.76mA   -98.15mA   -120mA
2.6V      -120mA     -300mA     -130mA
2.8V      -330mA     -610mA     -190mA
2.9V      -490mA     -760mA     -300mA
3.6V      -1.68A     -1.93A     -1.47A
[Ramp]
| variable   typ   min   max
dV/dt_r   0.77/0.53n   0.67/0.73n   0.88/0.35n
dV/dt_f   0.73/0.53n   0.64/0.78n   0.82/0.38n
R_load = 50.00
[Rising Waveform]
R_fixture = 50.00
V_fixture = 0.000
| time   V(typ)   V(min)   V(max)
0s        120mV      110mV      120mV
600ps     120mV      110mV      120mV
800ps     130mV      110mV      240mV
1ns       240mV      120mV      540mV
1.4ns     500mV      230mV      1.39V
1.8ns     1.15V      370mV      1.56V
2ns       1.31V      540mV      1.57V
2.6ns     1.4V       1.09V      1.57V
3ns       1.41V      1.2V       1.57V
10ns      1.41V      1.23V      1.57V
[Rising Waveform]
R_fixture = 50.00
V_fixture = 0.90
V_fixture_min = 0.85
V_fixture_max = 0.95
| time   V(typ)   V(min)   V(max)
0s        290mV      310mV      280mV
600ps     290mV      310mV      320mV
800ps     330mV      310mV      610mV
1.2ns     800mV      530mV      1.43V
1.6ns     1.23V      740mV      1.68V
1.8ns     1.45V      840mV      1.69V
2ns       1.52V      1V         1.7V
2.4ns     1.55V      1.3V       1.7V
3ns       1.56V      1.41V      1.7V
10ns      1.56V      1.42V      1.7V
[Falling Waveform]
R_fixture = 50.00
V_fixture = 0.000
| time   V(typ)   V(min)   V(max)
0s        1.41V      1.23V      1.57V
600ps     1.41V      1.23V      1.53V
800ps     1.36V      1.23V      1.16V
1ns       970mV      1.16V      520mV
1.2ns     490mV      930mV      190mV
1.4ns     290mV      650mV      150mV
1.6ns     180mV      360mV      130mV
1.8ns     150mV      220mV      120mV
2.2ns     130mV      140mV      120mV
10ns      120mV      110mV      120mV
[Falling Waveform]
R_fixture = 50.00
V_fixture = 0.90
V_fixture_min = 0.85
V_fixture_max = 0.95
| time   V(typ)   V(min)   V(max)
0s        1.56V      1.42V      1.7V
600ps     1.56V      1.42V      1.68V
800ps     1.54V      1.42V      1.46V
1ns       1.3V       1.4V       890mV
1.2ns     910mV      1.27V      460mV
1.4ns     660mV      1.07V      360mV
1.6ns     450mV      800mV      310mV
2ns       330mV      480mV      290mV
2.6ns     300mV      350mV      280mV
10ns      290mV      310mV      280mV
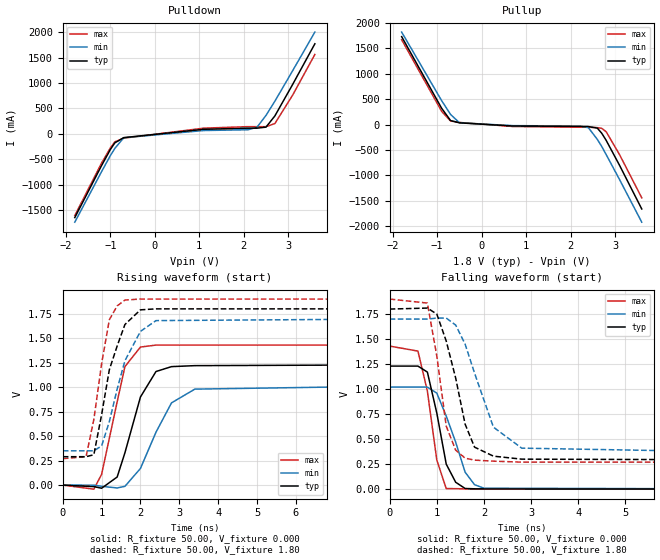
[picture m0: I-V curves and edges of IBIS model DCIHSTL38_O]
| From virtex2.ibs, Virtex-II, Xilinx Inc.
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|   Model DCIHSTL38_O
[Model]   DCIHSTL38_O
Model_type   Output
Polarity   Non-Inverting
Vmeas =   1.10V
Cref =  0pF
Rref =  50.00
Vref =   1.80V
C_comp   10.00pF   10.00pF   10.00pF
[Temperature Range]   25.00   100.00   0.000
[Voltage Range]   1.80V   1.70V   1.90V
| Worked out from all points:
|   slope of the pulldown table from 0 to 0.27 V, typ, clamps not added: 9.58 ohm
|   slope of the pullup table from 0 to 0.27 V, typ, clamps not added: 19.5 ohm
|   rising waveform, R_fixture 50.00, V_fixture 0.000: 20-80 % time 567ps typ, 728ps min, 471ps max; typ from 0 V to 1.23 V
|   rising waveform, R_fixture 50.00, V_fixture 1.80: 20-80 % time 533ps typ, 602ps min, 387ps max; typ from 0.29 V to 1.8 V
|   falling waveform, R_fixture 50.00, V_fixture 0.000: 20-80 % time 314ps typ, 452ps min, 285ps max; typ from 1.23 V to 0 V
|   falling waveform, R_fixture 50.00, V_fixture 1.80: 20-80 % time 464ps typ, 586ps min, 320ps max; typ from 1.8 V to 0.29 V
[Pulldown]
| voltage   I(typ)   I(min)   I(max)
-1.8V     -1.65A     -1.74A     -1.61A
-1.2V     -630mA     -750mA     -580mA
-1V       -310mA     -430mA     -280mA
-900mV    -180mA     -290mA     -160mA
-700mV    -76.35mA   -79.32mA   -86.73mA
1.1V      87.62mA    63.65mA    110mA
2.1V      110mA      78.46mA    140mA
2.3V      110mA      130mA      140mA
2.5V      130mA      360mA      140mA
2.7V      350mA      640mA      200mA
3.1V      970mA      1.24A      760mA
3.6V      1.77A      2A         1.56A
[Pullup]
| voltage   I(typ)   I(min)   I(max)
-1.8V     1.73A      1.82A      1.67A
-900mV    320mA      470mA      260mA
-700mV    79.53mA    200mA      70.09mA
-500mV    34.54mA    35.8mA     42.57mA
700mV     -27.45mA   -20.6mA    -37.46mA
2.2V      -36.44mA   -27.71mA   -51.87mA
2.4V      -37.84mA   -60.77mA   -52.52mA
2.6V      -68.77mA   -290mA     -59.14mA
2.7V      -170mA     -430mA     -73.59mA
2.8V      -310mA     -590mA     -140mA
3.1V      -800mA     -1.08A     -590mA
3.6V      -1.66A     -1.92A     -1.44A
[Ramp]
| variable   typ   min   max
dV/dt_r   0.74/0.54n   0.61/0.75n   0.86/0.38n
dV/dt_f   0.91/0.39n   0.81/0.59n   0.98/0.29n
R_load = 50.00
[Rising Waveform]
R_fixture = 50.00
V_fixture = 0.000
| time   V(typ)   V(min)   V(max)
0s        0V         0V         0V
800ps     -15.56mV   -680uV     -41.64mV
1ns       -32.05mV   -12.26mV   110mV
1.4ns     82.36mV    -29.35mV   850mV
1.6ns     330mV      -12.73mV   1.21V
2ns       900mV      170mV      1.41V
2.4ns     1.16V      540mV      1.43V
2.8ns     1.21V      840mV      1.43V
3.4ns     1.22V      980mV      1.43V
10ns      1.23V      1.02V      1.43V
[Rising Waveform]
R_fixture = 50.00
V_fixture = 1.80
V_fixture_min = 1.70
V_fixture_max = 1.90
| time   V(typ)   V(min)   V(max)
0s        290mV      350mV      270mV
600ps     290mV      350mV      290mV
800ps     310mV      350mV      670mV
1ns       720mV      400mV      1.24V
1.2ns     1.18V      650mV      1.69V
1.4ns     1.42V      980mV      1.83V
1.6ns     1.64V      1.27V      1.89V
2ns       1.79V      1.57V      1.9V
2.4ns     1.8V       1.68V      1.9V
10ns      1.8V       1.7V       1.9V
[Falling Waveform]
R_fixture = 50.00
V_fixture = 0.000
| time   V(typ)   V(min)   V(max)
0s        1.23V      1.02V      1.43V
600ps     1.23V      1.02V      1.38V
800ps     1.17V      1.02V      980mV
1ns       760mV      960mV      290mV
1.2ns     250mV      730mV      6.41mV
1.4ns     69.18mV    470mV      4.99mV
1.6ns     6.78mV     170mV      3.02mV
1.8ns     3.67mV     44.62mV    2.02mV
2ns       2.45mV     9.6mV      1.41mV
10ns      -1.27uV    -640nV     550nV
[Falling Waveform]
R_fixture = 50.00
V_fixture = 1.80
V_fixture_min = 1.70
V_fixture_max = 1.90
| time   V(typ)   V(min)   V(max)
0s        1.8V       1.7V       1.9V
800ps     1.81V      1.7V       1.86V
1ns       1.75V      1.71V      1.33V
1.2ns     1.48V      1.71V      630mV
1.4ns     1.11V      1.64V      390mV
1.6ns     650mV      1.45V      310mV
1.8ns     420mV      1.16V      290mV
2.2ns     330mV      620mV      280mV
2.8ns     300mV      410mV      270mV
10ns      290mV      350mV      270mV
